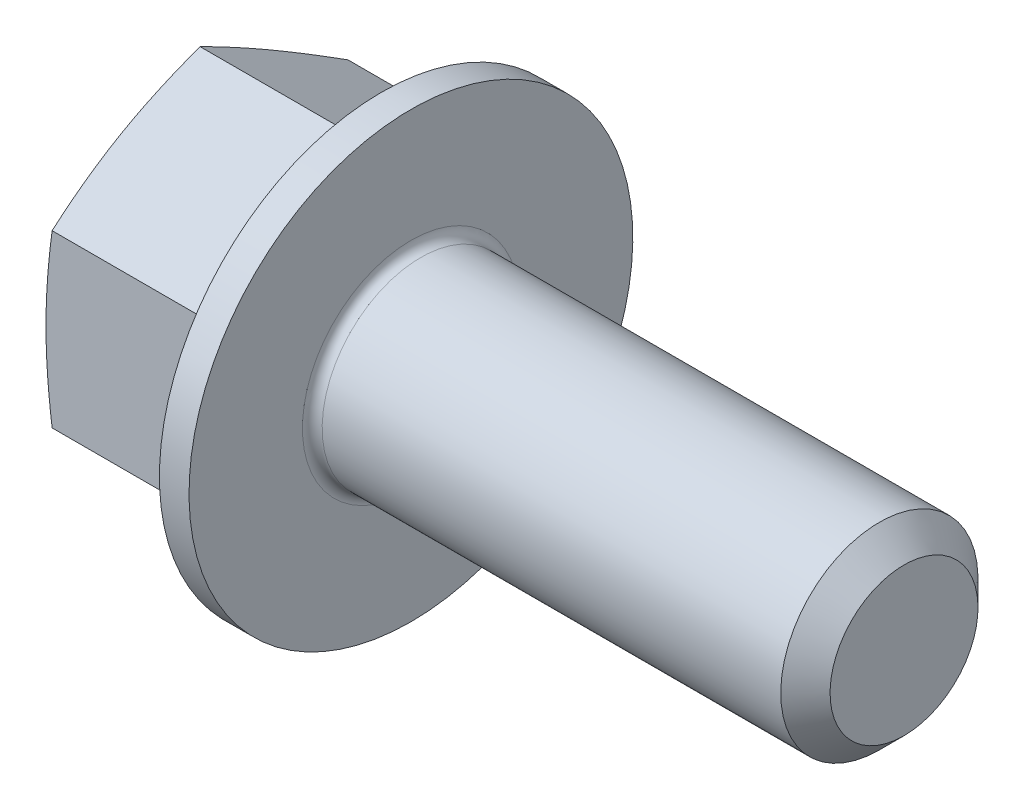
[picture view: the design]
ISO-10303-21;
HEADER;
FILE_DESCRIPTION(('STEP AP214'),'2;1');
FILE_NAME('part.step','',(''),(''),'','','');
FILE_SCHEMA(('AUTOMOTIVE_DESIGN { 1 0 10303 214 1 1 1 1 }'));
ENDSEC;
DATA;
#1=APPLICATION_CONTEXT('core data for automotive mechanical design processes');
#2=APPLICATION_PROTOCOL_DEFINITION('international standard','automotive_design',2000,#1);
#3=PRODUCT_CONTEXT('',#1,'mechanical');
#4=PRODUCT('Part','Part','',(#3));
#5=PRODUCT_RELATED_PRODUCT_CATEGORY('part','',(#4));
#6=PRODUCT_DEFINITION_FORMATION('','',#4);
#7=PRODUCT_DEFINITION_CONTEXT('part definition',#1,'design');
#8=PRODUCT_DEFINITION('design','',#6,#7);
#9=PRODUCT_DEFINITION_SHAPE('','',#8);
#10=(LENGTH_UNIT() NAMED_UNIT(*) SI_UNIT(.MILLI.,.METRE.));
#11=(NAMED_UNIT(*) PLANE_ANGLE_UNIT() SI_UNIT($,.RADIAN.));
#12=(NAMED_UNIT(*) SI_UNIT($,.STERADIAN.) SOLID_ANGLE_UNIT());
#13=UNCERTAINTY_MEASURE_WITH_UNIT(LENGTH_MEASURE(1.E-05),#10,'distance_accuracy_value','');
#14=(GEOMETRIC_REPRESENTATION_CONTEXT(3) GLOBAL_UNCERTAINTY_ASSIGNED_CONTEXT((#13)) GLOBAL_UNIT_ASSIGNED_CONTEXT((#10,
#11,#12)) REPRESENTATION_CONTEXT('',''));
#15=CARTESIAN_POINT('',(0.,0.,0.));
#16=DIRECTION('',(0.,0.,1.));
#17=DIRECTION('',(1.,0.,0.));
#18=AXIS2_PLACEMENT_3D('',#15,#16,#17);
#19=CARTESIAN_POINT('',(-0.3,0.,0.));
#20=DIRECTION('',(1.,0.,0.));
#21=DIRECTION('',(0.,1.,0.));
#22=AXIS2_PLACEMENT_3D('',#19,#20,#21);
#23=CONICAL_SURFACE('',#22,2.25,1.30899693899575);
#24=CARTESIAN_POINT('',(1.16852533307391,-2.67982443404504,7.64159207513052));
#25=CARTESIAN_POINT('',(1.26042918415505,-2.6677532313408,7.62068413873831));
#26=CARTESIAN_POINT('',(1.26511791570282,-2.58495311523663,7.66706657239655));
#27=CARTESIAN_POINT('',(1.08120608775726,-2.51357832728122,7.35364537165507));
#28=CARTESIAN_POINT('',(1.17299052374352,-2.50166546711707,7.3330116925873));
#29=CARTESIAN_POINT('',(1.17779867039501,-2.41890785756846,7.37905319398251));
#30=CARTESIAN_POINT('',(0.994043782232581,-2.34731143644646,7.06566266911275));
#31=CARTESIAN_POINT('',(1.08567092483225,-2.33552666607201,7.04525084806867));
#32=CARTESIAN_POINT('',(1.09063636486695,-2.25286120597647,7.09099799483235));
#33=CARTESIAN_POINT('',(0.820261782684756,-2.0145973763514,6.48938501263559));
#34=CARTESIAN_POINT('',(0.91144791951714,-2.00295342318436,6.46921709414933));
#35=CARTESIAN_POINT('',(0.916854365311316,-1.9206620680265,6.51456185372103));
#36=CARTESIAN_POINT('',(0.733642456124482,-1.84815015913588,6.20108997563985));
#37=CARTESIAN_POINT('',(0.824601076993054,-1.83662898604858,6.18113471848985));
#38=CARTESIAN_POINT('',(0.830235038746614,-1.75450957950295,6.22618082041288));
#39=CARTESIAN_POINT('',(0.559145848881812,-1.51101153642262,5.6171487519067));
#40=CARTESIAN_POINT('',(0.649509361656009,-1.49966816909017,5.59750146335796));
#41=CARTESIAN_POINT('',(0.655738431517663,-1.41807903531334,5.64205001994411));
#42=CARTESIAN_POINT('',(0.471290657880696,-1.34031726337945,5.32149759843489));
#43=CARTESIAN_POINT('',(0.561360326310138,-1.32918114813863,5.30220928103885));
#44=CARTESIAN_POINT('',(0.567883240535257,-1.24780087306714,5.34629490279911));
#45=CARTESIAN_POINT('',(0.297201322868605,-0.998834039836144,4.73003130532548));
#46=CARTESIAN_POINT('',(0.38644593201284,-0.987956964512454,4.71119165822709));
#47=CARTESIAN_POINT('',(0.393793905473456,-0.907344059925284,4.75460965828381));
#48=CARTESIAN_POINT('',(0.210966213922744,-0.828045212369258,4.43421637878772));
#49=CARTESIAN_POINT('',(0.299811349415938,-0.817490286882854,4.41593471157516));
#50=CARTESIAN_POINT('',(0.307558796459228,-0.737165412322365,4.45867975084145));
#51=CARTESIAN_POINT('',(0.0457052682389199,-0.494940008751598,3.85726124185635));
#52=CARTESIAN_POINT('',(0.133379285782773,-0.484748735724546,3.83960943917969));
#53=CARTESIAN_POINT('',(0.142297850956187,-0.405587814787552,3.88151329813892));
#54=CARTESIAN_POINT('',(-0.0334628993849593,-0.332641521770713,3.5761520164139));
#55=CARTESIAN_POINT('',(0.0536678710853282,-0.322953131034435,3.55937123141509));
#56=CARTESIAN_POINT('',(0.0631296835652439,-0.244189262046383,3.60030708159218));
#57=CARTESIAN_POINT('',(-0.148311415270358,-0.0885639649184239,3.15339728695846));
#58=CARTESIAN_POINT('',(-0.0626738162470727,-0.0788132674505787,3.13650858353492));
#59=CARTESIAN_POINT('',(-0.0517188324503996,-0.00191934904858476,3.17750894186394));
#60=CARTESIAN_POINT('',(-0.185978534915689,-0.00701979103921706,3.01215863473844));
#61=CARTESIAN_POINT('',(-0.100766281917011,0.0024789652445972,2.99570630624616));
#62=CARTESIAN_POINT('',(-0.0893859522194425,0.0789450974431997,3.03627288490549));
#63=CARTESIAN_POINT('',(-0.25925503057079,0.156298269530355,2.72928345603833));
#64=CARTESIAN_POINT('',(-0.175024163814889,0.165307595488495,2.71367884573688));
#65=CARTESIAN_POINT('',(-0.162662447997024,0.240685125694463,2.75348409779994));
#66=CARTESIAN_POINT('',(-0.294864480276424,0.238072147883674,2.58764694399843));
#67=CARTESIAN_POINT('',(-0.211154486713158,0.246741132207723,2.57263182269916));
#68=CARTESIAN_POINT('',(-0.19827189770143,0.321560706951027,2.61193137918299));
#69=CARTESIAN_POINT('',(-0.362403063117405,0.400818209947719,2.30576249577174));
#70=CARTESIAN_POINT('',(-0.279864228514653,0.408806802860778,2.29192584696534));
#71=CARTESIAN_POINT('',(-0.265810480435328,0.482225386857,2.33038553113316));
#72=CARTESIAN_POINT('',(-0.394376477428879,0.481785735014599,2.1655226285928));
#73=CARTESIAN_POINT('',(-0.312456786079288,0.489314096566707,2.1524831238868));
#74=CARTESIAN_POINT('',(-0.297783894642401,0.562013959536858,2.19039807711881));
#75=CARTESIAN_POINT('',(-0.453314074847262,0.644206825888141,1.88420104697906));
#76=CARTESIAN_POINT('',(-0.372713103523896,0.650745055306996,1.87287650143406));
#77=CARTESIAN_POINT('',(-0.356721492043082,0.721717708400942,1.90992625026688));
#78=CARTESIAN_POINT('',(-0.480277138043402,0.725660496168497,1.74311915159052));
#79=CARTESIAN_POINT('',(-0.400383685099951,0.731580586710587,1.73286525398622));
#80=CARTESIAN_POINT('',(-0.383684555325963,0.801632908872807,1.76944177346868));
#81=CARTESIAN_POINT('',(-0.526067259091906,0.888881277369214,1.4604124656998));
#82=CARTESIAN_POINT('',(-0.447482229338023,0.893400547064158,1.45258486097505));
#83=CARTESIAN_POINT('',(-0.429474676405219,0.961477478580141,1.48856472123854));
#84=CARTESIAN_POINT('',(-0.544921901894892,0.970646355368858,1.31879119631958));
#85=CARTESIAN_POINT('',(-0.467016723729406,0.974422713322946,1.31225035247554));
#86=CARTESIAN_POINT('',(-0.448329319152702,1.04140585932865,1.348173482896));
#87=CARTESIAN_POINT('',(-0.570718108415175,1.13462632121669,1.03476956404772));
#88=CARTESIAN_POINT('',(-0.493671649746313,1.13649888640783,1.03152618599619));
#89=CARTESIAN_POINT('',(-0.474125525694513,1.20184772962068,1.06745641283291));
#90=CARTESIAN_POINT('',(-0.577669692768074,1.21684077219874,0.892369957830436));
#91=CARTESIAN_POINT('',(-0.500930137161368,1.2179038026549,0.890528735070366));
#92=CARTESIAN_POINT('',(-0.48107711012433,1.28236066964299,0.92713062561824));
#93=CARTESIAN_POINT('',(-0.577704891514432,1.33303362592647,0.69111803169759));
#94=CARTESIAN_POINT('',(-0.500975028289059,1.33259321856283,0.691880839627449));
#95=CARTESIAN_POINT('',(-0.481112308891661,1.3966709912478,0.729127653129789));
#96=CARTESIAN_POINT('',(-0.57653036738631,1.36702621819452,0.63224113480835));
#97=CARTESIAN_POINT('',(-0.499753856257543,1.36616942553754,0.633725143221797));
#98=CARTESIAN_POINT('',(-0.479937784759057,1.43017604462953,0.671239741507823));
#99=CARTESIAN_POINT('',(-0.571921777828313,1.43498768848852,0.51452841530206));
#100=CARTESIAN_POINT('',(-0.494976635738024,1.4332771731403,0.517491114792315));
#101=CARTESIAN_POINT('',(-0.47532919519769,1.49730148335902,0.555523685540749));
#102=CARTESIAN_POINT('',(-0.568486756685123,1.46895655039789,0.455692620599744));
#103=CARTESIAN_POINT('',(-0.491414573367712,1.46684337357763,0.459352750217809));
#104=CARTESIAN_POINT('',(-0.471894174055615,1.53092191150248,0.497695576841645));
#105=CARTESIAN_POINT('',(-0.554993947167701,1.57088921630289,0.279140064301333));
#106=CARTESIAN_POINT('',(-0.477436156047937,1.56765525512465,0.284741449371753));
#107=CARTESIAN_POINT('',(-0.458401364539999,1.6320177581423,0.324121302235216));
#108=CARTESIAN_POINT('',(-0.541749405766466,1.63874915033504,0.161603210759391));
#109=CARTESIAN_POINT('',(-0.463703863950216,1.63485041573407,0.168356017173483));
#110=CARTESIAN_POINT('',(-0.445156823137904,1.69959991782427,0.208506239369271));
#111=CARTESIAN_POINT('',(-0.508739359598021,1.77462324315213,-0.0737376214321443));
#112=CARTESIAN_POINT('',(-0.429692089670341,1.76940488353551,-0.0646991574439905));
#113=CARTESIAN_POINT('',(-0.412146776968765,1.83528458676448,-0.0233483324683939));
#114=CARTESIAN_POINT('',(-0.48892003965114,1.84263391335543,-0.191535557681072));
#115=CARTESIAN_POINT('',(-0.40929760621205,1.83683303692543,-0.181488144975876));
#116=CARTESIAN_POINT('',(-0.392327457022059,1.90338670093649,-0.139584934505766));
#117=CARTESIAN_POINT('',(-0.444775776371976,1.97811547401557,-0.426196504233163));
#118=CARTESIAN_POINT('',(-0.364005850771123,1.97135383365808,-0.414484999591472));
#119=CARTESIAN_POINT('',(-0.348183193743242,2.039233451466,-0.371492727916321));
#120=CARTESIAN_POINT('',(-0.420462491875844,2.04558730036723,-0.543061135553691));
#121=CARTESIAN_POINT('',(-0.339090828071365,2.03843783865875,-0.530677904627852));
#122=CARTESIAN_POINT('',(-0.323869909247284,2.10697855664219,-0.48716460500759));
#123=CARTESIAN_POINT('',(-0.394836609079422,2.11290400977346,-0.659657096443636));
#124=CARTESIAN_POINT('',(-0.313077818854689,2.10509238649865,-0.646126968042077));
#125=CARTESIAN_POINT('',(-0.298244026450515,2.17456502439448,-0.602743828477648));
#126=(BOUNDED_SURFACE() B_SPLINE_SURFACE(3,2,((#24,#25,#26),(#27,#28,#29),(#30,#31,#32),(#33,
#34,#35),(#36,#37,#38),(#39,#40,#41),(#42,#43,#44),(#45,#46,#47),(#48,#49,#50),(#51,#52,#53),
(#54,#55,#56),(#57,#58,#59),(#60,#61,#62),(#63,#64,#65),(#66,#67,#68),(#69,#70,#71),(#72,#73,
#74),(#75,#76,#77),(#78,#79,#80),(#81,#82,#83),(#84,#85,#86),(#87,#88,#89),(#90,#91,#92),(#93,
#94,#95),(#96,#97,#98),(#99,#100,#101),(#102,#103,#104),(#105,#106,#107),(#108,#109,#110),(#111,
#112,#113),(#114,#115,#116),(#117,#118,#119),(#120,#121,#122),(#123,#124,#125)),.UNSPECIFIED.,
.F.,.F.,.F.) B_SPLINE_SURFACE_WITH_KNOTS((4,2,2,2,2,2,2,2,2,2,2,2,2,2,2,2,4),(3,3),(0.,
1.03130129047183,2.06323808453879,3.12077118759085,4.17765305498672,5.17996149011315,
5.6820983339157,6.18421718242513,6.67935566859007,7.17460469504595,7.66815528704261,
8.1612901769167,8.36524298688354,8.56928208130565,8.97813846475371,9.39042752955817,
9.80166162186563),(0.,1.),
.UNSPECIFIED.) GEOMETRIC_REPRESENTATION_ITEM() RATIONAL_B_SPLINE_SURFACE(((1.,0.724919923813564,
1.),(1.,0.725634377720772,1.),(1.,0.726416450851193,1.),(1.,0.728221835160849,1.),(1.,
0.729245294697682,1.),(1.,0.731668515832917,1.),(1.,0.733076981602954,1.),(1.,0.736473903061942,
1.),(1.,0.738462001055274,1.),(1.,0.74328290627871,1.),(1.,0.746066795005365,1.),(1.,
0.751359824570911,1.),(1.,0.75331282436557,1.),(1.,0.757692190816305,1.),(1.,0.760118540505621,
1.),(1.,0.765471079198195,1.),(1.,0.768389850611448,1.),(1.,0.774638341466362,1.),(1.,
0.777968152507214,1.),(1.,0.784396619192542,1.),(1.,0.78749602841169,1.),(1.,0.791967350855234,
1.),(1.,0.793340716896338,1.),(1.,0.793358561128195,1.),(1.,0.79313102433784,1.),(1.,
0.792266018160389,1.),(1.,0.791628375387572,1.),(1.,0.789211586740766,1.),(1.,0.786929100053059,
1.),(1.,0.781896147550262,1.),(1.,0.779141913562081,1.),(1.,0.773692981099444,1.),(1.,
0.770998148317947,1.),(1.,0.768581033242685,1.))) REPRESENTATION_ITEM('') SURFACE());
#127=CARTESIAN_POINT('',(-0.298244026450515,2.17456502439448,-0.602743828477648));
#128=CARTESIAN_POINT('',(-0.323869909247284,2.10697855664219,-0.48716460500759));
#129=CARTESIAN_POINT('',(-0.348183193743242,2.039233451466,-0.371492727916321));
#130=CARTESIAN_POINT('',(-0.392327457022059,1.90338670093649,-0.139584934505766));
#131=CARTESIAN_POINT('',(-0.412146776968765,1.83528458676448,-0.0233483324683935));
#132=CARTESIAN_POINT('',(-0.445156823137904,1.69959991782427,0.208506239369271));
#133=CARTESIAN_POINT('',(-0.458401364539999,1.6320177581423,0.324121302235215));
#134=CARTESIAN_POINT('',(-0.471894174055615,1.53092191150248,0.497695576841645));
#135=CARTESIAN_POINT('',(-0.47532919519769,1.49730148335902,0.555523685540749));
#136=CARTESIAN_POINT('',(-0.479937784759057,1.43017604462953,0.671239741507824));
#137=CARTESIAN_POINT('',(-0.481112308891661,1.3966709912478,0.729127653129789));
#138=CARTESIAN_POINT('',(-0.48107711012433,1.28236066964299,0.92713062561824));
#139=CARTESIAN_POINT('',(-0.474125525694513,1.20184772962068,1.06745641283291));
#140=CARTESIAN_POINT('',(-0.448329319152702,1.04140585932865,1.348173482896));
#141=CARTESIAN_POINT('',(-0.429474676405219,0.961477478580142,1.48856472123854));
#142=CARTESIAN_POINT('',(-0.383684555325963,0.801632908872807,1.76944177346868));
#143=CARTESIAN_POINT('',(-0.356721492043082,0.721717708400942,1.90992625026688));
#144=CARTESIAN_POINT('',(-0.297783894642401,0.562013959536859,2.19039807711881));
#145=CARTESIAN_POINT('',(-0.265810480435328,0.482225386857,2.33038553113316));
#146=CARTESIAN_POINT('',(-0.19827189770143,0.321560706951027,2.61193137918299));
#147=CARTESIAN_POINT('',(-0.162662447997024,0.240685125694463,2.75348409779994));
#148=CARTESIAN_POINT('',(-0.0893859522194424,0.0789450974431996,3.03627288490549));
#149=CARTESIAN_POINT('',(-0.0517188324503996,-0.0019193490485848,3.17750894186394));
#150=CARTESIAN_POINT('',(0.0631296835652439,-0.244189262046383,3.60030708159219));
#151=CARTESIAN_POINT('',(0.142297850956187,-0.405587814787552,3.88151329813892));
#152=CARTESIAN_POINT('',(0.307558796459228,-0.737165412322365,4.45867975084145));
#153=CARTESIAN_POINT('',(0.393793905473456,-0.907344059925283,4.75460965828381));
#154=CARTESIAN_POINT('',(0.567883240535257,-1.24780087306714,5.34629490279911));
#155=CARTESIAN_POINT('',(0.655738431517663,-1.41807903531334,5.64205001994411));
#156=CARTESIAN_POINT('',(0.830235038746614,-1.75450957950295,6.22618082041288));
#157=CARTESIAN_POINT('',(0.916854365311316,-1.9206620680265,6.51456185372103));
#158=CARTESIAN_POINT('',(1.09063636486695,-2.25286120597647,7.09099799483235));
#159=CARTESIAN_POINT('',(1.17779867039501,-2.41890785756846,7.37905319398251));
#160=CARTESIAN_POINT('',(1.26511791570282,-2.58495311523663,7.66706657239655));
#161=B_SPLINE_CURVE_WITH_KNOTS('',3,(#127,#128,#129,#130,#131,#132,#133,#134,#135,#136,#137,
#138,#139,#140,#141,#142,#143,#144,#145,#146,#147,#148,#149,#150,#151,#152,#153,#154,#155,#156,
#157,#158,#159,#160),.UNSPECIFIED.,.F.,.F.,(4,2,2,2,2,2,2,2,2,2,2,2,2,2,2,2,4),(0.,
0.411234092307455,0.823523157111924,1.23237954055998,1.43641863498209,1.64037144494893,
2.13350633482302,2.62705692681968,3.12230595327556,3.6174444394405,4.11956328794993,
4.62170013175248,5.62400856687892,6.68089043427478,7.73842353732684,8.7703603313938,
9.80166162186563),.UNSPECIFIED.);
#162=CARTESIAN_POINT('',(-0.414778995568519,1.82163895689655,0.));
#163=VERTEX_POINT('',#162);
#164=CARTESIAN_POINT('',(-0.414778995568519,0.910819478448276,1.5775856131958));
#165=VERTEX_POINT('',#164);
#166=EDGE_CURVE('E454',#163,#165,#161,.T.);
#167=ORIENTED_EDGE('',*,*,#166,.T.);
#168=CARTESIAN_POINT('',(1.16815629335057,-7.95632023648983,1.5));
#169=CARTESIAN_POINT('',(1.26005938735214,-7.93217819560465,1.5));
#170=CARTESIAN_POINT('',(1.26474887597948,-7.93094631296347,1.59489735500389));
#171=CARTESIAN_POINT('',(1.08083726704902,-7.62382649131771,1.5));
#172=CARTESIAN_POINT('',(1.17262089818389,-7.60000121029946,1.5));
#173=CARTESIAN_POINT('',(1.1774298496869,-7.59849527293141,1.59469000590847));
#174=CARTESIAN_POINT('',(0.993675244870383,-7.29129116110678,1.5));
#175=CARTESIAN_POINT('',(1.08530154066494,-7.26772219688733,1.5));
#176=CARTESIAN_POINT('',(1.09026782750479,-7.26600730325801,1.594462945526));
#177=CARTESIAN_POINT('',(0.819894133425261,-6.62585972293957,1.5));
#178=CARTESIAN_POINT('',(0.911079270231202,-6.6025725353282,1.5));
#179=CARTESIAN_POINT('',(0.91648671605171,-6.6006961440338,1.59393756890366));
#180=CARTESIAN_POINT('',(0.733275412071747,-6.29296351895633,1.5));
#181=CARTESIAN_POINT('',(0.82423295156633,-6.26992201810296,1.5));
#182=CARTESIAN_POINT('',(0.829867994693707,-6.26787287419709,1.59363920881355));
#183=CARTESIAN_POINT('',(0.558777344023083,-5.61866988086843,1.5));
#184=CARTESIAN_POINT('',(0.649139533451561,-5.59598422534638,1.5));
#185=CARTESIAN_POINT('',(0.65536992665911,-5.59376922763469,1.59293088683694));
#186=CARTESIAN_POINT('',(0.470920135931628,-5.27726669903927,1.5));
#187=CARTESIAN_POINT('',(0.560988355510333,-5.25499582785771,1.5));
#188=CARTESIAN_POINT('',(0.567512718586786,-5.2524841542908,1.59251833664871));
#189=CARTESIAN_POINT('',(0.296828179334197,-4.59427079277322,1.5));
#190=CARTESIAN_POINT('',(0.38607092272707,-4.57251836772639,1.5));
#191=CARTESIAN_POINT('',(0.393420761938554,-4.56981210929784,1.59151941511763));
#192=CARTESIAN_POINT('',(0.210592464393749,-4.25267831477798,1.5));
#193=CARTESIAN_POINT('',(0.299435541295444,-4.2315707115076,1.5));
#194=CARTESIAN_POINT('',(0.307185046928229,-4.22842533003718,1.59093315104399));
#195=CARTESIAN_POINT('',(0.0453368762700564,-3.58645304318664,1.5));
#196=CARTESIAN_POINT('',(0.133008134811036,-3.56607324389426,1.5));
#197=CARTESIAN_POINT('',(0.141929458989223,-3.56278144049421,1.5895036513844));
#198=CARTESIAN_POINT('',(-0.0338255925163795,-3.26185609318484,1.5));
#199=CARTESIAN_POINT('',(0.0533021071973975,-3.2424828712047,1.5));
#200=CARTESIAN_POINT('',(0.0627669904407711,-3.23855083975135,1.58867526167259));
#201=CARTESIAN_POINT('',(-0.148660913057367,-2.7736997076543,1.5));
#202=CARTESIAN_POINT('',(-0.0630272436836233,-2.7542021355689,1.5));
#203=CARTESIAN_POINT('',(-0.0520683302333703,-2.7512617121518,1.58708701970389));
#204=CARTESIAN_POINT('',(-0.18632288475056,-2.61061056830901,1.5));
#205=CARTESIAN_POINT('',(-0.101114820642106,-2.59161735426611,1.5));
#206=CARTESIAN_POINT('',(-0.089730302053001,-2.58851510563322,1.58649925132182));
#207=CARTESIAN_POINT('',(-0.25958637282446,-2.28397234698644,1.5));
#208=CARTESIAN_POINT('',(-0.175360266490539,-2.26595901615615,1.5));
#209=CARTESIAN_POINT('',(-0.162993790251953,-2.26274184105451,1.58517492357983));
#210=CARTESIAN_POINT('',(-0.2951879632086,-2.12042328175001,1.5));
#211=CARTESIAN_POINT('',(-0.211483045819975,-2.10309130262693,1.5));
#212=CARTESIAN_POINT('',(-0.198595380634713,-2.09971519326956,1.58443836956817));
#213=CARTESIAN_POINT('',(-0.362705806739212,-1.79493051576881,1.5));
#214=CARTESIAN_POINT('',(-0.280172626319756,-1.77896083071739,1.5));
#215=CARTESIAN_POINT('',(-0.266113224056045,-1.7755582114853,1.58280412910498));
#216=CARTESIAN_POINT('',(-0.39466645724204,-1.63299615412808,1.5));
#217=CARTESIAN_POINT('',(-0.312752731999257,-1.61794780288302,1.5));
#218=CARTESIAN_POINT('',(-0.298073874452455,-1.61443306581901,1.58190882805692));
#219=CARTESIAN_POINT('',(-0.453571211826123,-1.30815460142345,1.5));
#220=CARTESIAN_POINT('',(-0.372976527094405,-1.29508872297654,1.5));
#221=CARTESIAN_POINT('',(-0.356978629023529,-1.29168904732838,1.57997967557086));
#222=CARTESIAN_POINT('',(-0.480514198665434,-1.14524720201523,1.5));
#223=CARTESIAN_POINT('',(-0.400627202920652,-1.13341855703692,1.5));
#224=CARTESIAN_POINT('',(-0.383921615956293,-1.13007007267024,1.57894579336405));
#225=CARTESIAN_POINT('',(-0.526253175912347,-0.81880561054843,1.5));
#226=CARTESIAN_POINT('',(-0.447673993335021,-0.80978145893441,1.5));
#227=CARTESIAN_POINT('',(-0.429660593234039,-0.806905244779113,1.57693729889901));
#228=CARTESIAN_POINT('',(-0.545076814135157,-0.655275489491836,1.5));
#229=CARTESIAN_POINT('',(-0.467176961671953,-0.647737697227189,1.5));
#230=CARTESIAN_POINT('',(-0.448484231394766,-0.645361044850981,1.57596249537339));
#231=CARTESIAN_POINT('',(-0.570800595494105,-0.327317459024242,1.5));
#232=CARTESIAN_POINT('',(-0.493757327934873,-0.323590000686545,1.5));
#233=CARTESIAN_POINT('',(-0.474208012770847,-0.322037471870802,1.57455395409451));
#234=CARTESIAN_POINT('',(-0.577710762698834,-0.162890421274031,1.5));
#235=CARTESIAN_POINT('',(-0.500972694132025,-0.160782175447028,1.5));
#236=CARTESIAN_POINT('',(-0.481118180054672,-0.160258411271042,1.57411976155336));
#237=CARTESIAN_POINT('',(-0.577687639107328,0.0694902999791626,1.5));
#238=CARTESIAN_POINT('',(-0.500957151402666,0.0685905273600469,1.5));
#239=CARTESIAN_POINT('',(-0.481095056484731,0.0683674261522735,1.57411742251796));
#240=CARTESIAN_POINT('',(-0.576496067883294,0.13747391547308,1.5));
#241=CARTESIAN_POINT('',(-0.499718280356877,0.135741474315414,1.5));
#242=CARTESIAN_POINT('',(-0.479903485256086,0.135251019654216,1.57419072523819));
#243=CARTESIAN_POINT('',(-0.57185435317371,0.273393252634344,1.5));
#244=CARTESIAN_POINT('',(-0.494906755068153,0.269953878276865,1.5));
#245=CARTESIAN_POINT('',(-0.475261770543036,0.269023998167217,1.57446693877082));
#246=CARTESIAN_POINT('',(-0.568403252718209,0.341328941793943,1.5));
#247=CARTESIAN_POINT('',(-0.491328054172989,0.337084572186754,1.5));
#248=CARTESIAN_POINT('',(-0.471810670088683,0.335913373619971,1.57466990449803));
#249=CARTESIAN_POINT('',(-0.554864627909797,0.545188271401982,1.5));
#250=CARTESIAN_POINT('',(-0.477302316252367,0.538704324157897,1.5));
#251=CARTESIAN_POINT('',(-0.45827204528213,0.536777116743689,1.57543658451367));
#252=CARTESIAN_POINT('',(-0.541592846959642,0.680903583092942,1.5));
#253=CARTESIAN_POINT('',(-0.463542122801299,0.673090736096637,1.5));
#254=CARTESIAN_POINT('',(-0.445000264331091,0.67069107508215,1.57615790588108));
#255=CARTESIAN_POINT('',(-0.508536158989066,0.952643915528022,1.5));
#256=CARTESIAN_POINT('',(-0.429482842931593,0.942194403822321,1.5));
#257=CARTESIAN_POINT('',(-0.4119435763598,0.93932106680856,1.57773806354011));
#258=CARTESIAN_POINT('',(-0.488697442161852,1.08866195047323,1.5));
#259=CARTESIAN_POINT('',(-0.409068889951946,1.0770483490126,1.5));
#260=CARTESIAN_POINT('',(-0.392104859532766,1.07403438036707,1.5785980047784));
#261=CARTESIAN_POINT('',(-0.444520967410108,1.35961767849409,1.5));
#262=CARTESIAN_POINT('',(-0.363744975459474,1.34608444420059,1.5));
#263=CARTESIAN_POINT('',(-0.347928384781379,1.34279142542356,1.58029056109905));
#264=CARTESIAN_POINT('',(-0.42019489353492,1.49455724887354,1.5));
#265=CARTESIAN_POINT('',(-0.338817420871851,1.48024883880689,1.5));
#266=CARTESIAN_POINT('',(-0.32360231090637,1.47683598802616,1.58112324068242));
#267=CARTESIAN_POINT('',(-0.394558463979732,1.62918706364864,1.5));
#268=CARTESIAN_POINT('',(-0.312793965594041,1.61355586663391,1.5));
#269=CARTESIAN_POINT('',(-0.297965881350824,1.61072113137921,1.58186488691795));
#270=(BOUNDED_SURFACE() B_SPLINE_SURFACE(3,2,((#168,#169,#170),(#171,#172,#173),(#174,#175,
#176),(#177,#178,#179),(#180,#181,#182),(#183,#184,#185),(#186,#187,#188),(#189,#190,#191),
(#192,#193,#194),(#195,#196,#197),(#198,#199,#200),(#201,#202,#203),(#204,#205,#206),(#207,#208,
#209),(#210,#211,#212),(#213,#214,#215),(#216,#217,#218),(#219,#220,#221),(#222,#223,#224),
(#225,#226,#227),(#228,#229,#230),(#231,#232,#233),(#234,#235,#236),(#237,#238,#239),(#240,#241,
#242),(#243,#244,#245),(#246,#247,#248),(#249,#250,#251),(#252,#253,#254),(#255,#256,#257),
(#258,#259,#260),(#261,#262,#263),(#264,#265,#266),(#267,#268,#269)),.UNSPECIFIED.,.F.,.F.,
.F.) B_SPLINE_SURFACE_WITH_KNOTS((4,2,2,2,2,2,2,2,2,2,2,2,2,2,2,2,4),(3,3),(0.,1.03130556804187,
2.06324704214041,3.12082417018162,4.17774959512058,5.1800538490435,5.68218951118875,
6.18430712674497,6.67943603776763,7.17467506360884,7.66821413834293,8.16133774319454,
8.36528677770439,8.56932224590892,8.97817344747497,9.39046133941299,9.80169050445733),(0.,1.),
.UNSPECIFIED.) GEOMETRIC_REPRESENTATION_ITEM() RATIONAL_B_SPLINE_SURFACE(((1.,0.724922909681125,
1.),(1.,0.725637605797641,1.),(1.,0.726419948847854,1.),(1.,0.728226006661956,1.),(1.,
0.72924986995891,1.),(1.,0.731674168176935,1.),(1.,0.733083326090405,1.),(1.,0.736482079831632,
1.),(1.,0.738471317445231,1.),(1.,0.743295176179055,1.),(1.,0.746080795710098,1.),(1.,
0.751377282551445,1.),(1.,0.753331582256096,1.),(1.,0.757713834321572,1.),(1.,0.760141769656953,
1.),(1.,0.765497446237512,1.),(1.,0.768417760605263,1.),(1.,0.774668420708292,1.),(1.,
0.777998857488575,1.),(1.,0.784425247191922,1.),(1.,0.787521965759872,1.),(1.,0.791982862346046,
1.),(1.,0.793348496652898,1.),(1.,0.793355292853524,1.),(1.,0.793124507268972,1.),(1.,
0.792253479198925,1.),(1.,0.791613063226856,1.),(1.,0.789189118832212,1.),(1.,0.786903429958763,
1.),(1.,0.781866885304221,1.),(1.,0.779112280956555,1.),(1.,0.773664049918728,1.),(1.,
0.770970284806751,1.),(1.,0.768554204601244,1.))) REPRESENTATION_ITEM('') SURFACE());
#271=CARTESIAN_POINT('',(-0.297965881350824,1.61072113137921,1.58186488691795));
#272=CARTESIAN_POINT('',(-0.32360231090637,1.47683598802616,1.58112324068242));
#273=CARTESIAN_POINT('',(-0.347928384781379,1.34279142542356,1.58029056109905));
#274=CARTESIAN_POINT('',(-0.392104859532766,1.07403438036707,1.5785980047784));
#275=CARTESIAN_POINT('',(-0.4119435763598,0.939321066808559,1.57773806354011));
#276=CARTESIAN_POINT('',(-0.445000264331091,0.67069107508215,1.57615790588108));
#277=CARTESIAN_POINT('',(-0.45827204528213,0.53677711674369,1.57543658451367));
#278=CARTESIAN_POINT('',(-0.471810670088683,0.335913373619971,1.57466990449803));
#279=CARTESIAN_POINT('',(-0.475261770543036,0.269023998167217,1.57446693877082));
#280=CARTESIAN_POINT('',(-0.479903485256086,0.135251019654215,1.57419072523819));
#281=CARTESIAN_POINT('',(-0.481095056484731,0.0683674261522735,1.57411742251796));
#282=CARTESIAN_POINT('',(-0.481118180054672,-0.160258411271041,1.57411976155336));
#283=CARTESIAN_POINT('',(-0.474208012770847,-0.322037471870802,1.57455395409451));
#284=CARTESIAN_POINT('',(-0.448484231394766,-0.645361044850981,1.57596249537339));
#285=CARTESIAN_POINT('',(-0.429660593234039,-0.806905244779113,1.57693729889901));
#286=CARTESIAN_POINT('',(-0.383921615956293,-1.13007007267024,1.57894579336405));
#287=CARTESIAN_POINT('',(-0.356978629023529,-1.29168904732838,1.57997967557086));
#288=CARTESIAN_POINT('',(-0.298073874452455,-1.61443306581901,1.58190882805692));
#289=CARTESIAN_POINT('',(-0.266113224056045,-1.7755582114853,1.58280412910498));
#290=CARTESIAN_POINT('',(-0.198595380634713,-2.09971519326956,1.58443836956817));
#291=CARTESIAN_POINT('',(-0.162993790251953,-2.26274184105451,1.58517492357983));
#292=CARTESIAN_POINT('',(-0.0897303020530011,-2.58851510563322,1.58649925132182));
#293=CARTESIAN_POINT('',(-0.0520683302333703,-2.7512617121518,1.58708701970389));
#294=CARTESIAN_POINT('',(0.0627669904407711,-3.23855083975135,1.58867526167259));
#295=CARTESIAN_POINT('',(0.141929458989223,-3.56278144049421,1.5895036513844));
#296=CARTESIAN_POINT('',(0.307185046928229,-4.22842533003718,1.59093315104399));
#297=CARTESIAN_POINT('',(0.393420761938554,-4.56981210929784,1.59151941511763));
#298=CARTESIAN_POINT('',(0.567512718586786,-5.2524841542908,1.59251833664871));
#299=CARTESIAN_POINT('',(0.65536992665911,-5.59376922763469,1.59293088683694));
#300=CARTESIAN_POINT('',(0.829867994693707,-6.26787287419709,1.59363920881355));
#301=CARTESIAN_POINT('',(0.91648671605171,-6.6006961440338,1.59393756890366));
#302=CARTESIAN_POINT('',(1.09026782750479,-7.26600730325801,1.594462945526));
#303=CARTESIAN_POINT('',(1.1774298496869,-7.59849527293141,1.59469000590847));
#304=CARTESIAN_POINT('',(1.26474887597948,-7.93094631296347,1.59489735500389));
#305=B_SPLINE_CURVE_WITH_KNOTS('',3,(#271,#272,#273,#274,#275,#276,#277,#278,#279,#280,#281,
#282,#283,#284,#285,#286,#287,#288,#289,#290,#291,#292,#293,#294,#295,#296,#297,#298,#299,#300,
#301,#302,#303,#304),.UNSPECIFIED.,.F.,.F.,(4,2,2,2,2,2,2,2,2,2,2,2,2,2,2,2,4),(0.,
0.41122916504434,0.823517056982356,1.23236825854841,1.43640372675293,1.64035276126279,
2.1334763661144,2.62701544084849,3.1222544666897,3.61738337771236,4.11950099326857,
4.62163665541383,5.62394090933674,6.68086633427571,7.73844346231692,8.77038493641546,
9.80169050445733),.UNSPECIFIED.);
#306=CARTESIAN_POINT('',(-0.414778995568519,-0.910819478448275,1.5775856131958));
#307=VERTEX_POINT('',#306);
#308=EDGE_CURVE('E376',#165,#307,#305,.T.);
#309=ORIENTED_EDGE('',*,*,#308,.T.);
#310=CARTESIAN_POINT('',(1.16852533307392,-5.27790064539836,-6.14159207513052));
#311=CARTESIAN_POINT('',(1.26042918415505,-5.26582944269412,-6.12068413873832));
#312=CARTESIAN_POINT('',(1.26511791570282,-5.34739786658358,-6.07216835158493));
#313=CARTESIAN_POINT('',(1.08120608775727,-5.11165453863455,-5.85364537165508));
#314=CARTESIAN_POINT('',(1.17299052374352,-5.09974167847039,-5.8330116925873));
#315=CARTESIAN_POINT('',(1.17779867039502,-5.18099359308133,-5.78436225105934));
#316=CARTESIAN_POINT('',(0.994043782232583,-4.94538764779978,-5.56566266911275));
#317=CARTESIAN_POINT('',(1.08567092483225,-4.93360287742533,-5.54525084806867));
#318=CARTESIAN_POINT('',(1.09063636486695,-5.0145537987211,-5.49653403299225));
#319=CARTESIAN_POINT('',(0.820261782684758,-4.61267358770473,-4.9893850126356));
#320=CARTESIAN_POINT('',(0.911447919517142,-4.60102963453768,-4.96921709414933));
#321=CARTESIAN_POINT('',(0.916854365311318,-4.68144502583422,-4.92062306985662));
#322=CARTESIAN_POINT('',(0.733642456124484,-4.4462263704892,-4.70108997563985));
#323=CARTESIAN_POINT('',(0.824601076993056,-4.4347051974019,-4.68113471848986));
#324=CARTESIAN_POINT('',(0.830235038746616,-4.51477596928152,-4.63254027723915));
#325=CARTESIAN_POINT('',(0.559145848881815,-4.10908774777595,-4.11714875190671));
#326=CARTESIAN_POINT('',(0.649509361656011,-4.09774438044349,-4.09750146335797));
#327=CARTESIAN_POINT('',(0.655738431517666,-4.17711912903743,-4.04911747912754));
#328=CARTESIAN_POINT('',(0.471290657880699,-3.93839347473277,-3.82149759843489));
#329=CARTESIAN_POINT('',(0.561360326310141,-3.92725735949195,-3.80220928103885));
#330=CARTESIAN_POINT('',(0.567883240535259,-4.00612676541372,-3.75377470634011));
#331=CARTESIAN_POINT('',(0.297201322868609,-3.59691025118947,-3.23003130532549));
#332=CARTESIAN_POINT('',(0.386445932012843,-3.58603317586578,-3.2111916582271));
#333=CARTESIAN_POINT('',(0.393793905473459,-3.66394071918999,-3.16308783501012));
#334=CARTESIAN_POINT('',(0.210966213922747,-3.42612142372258,-2.93421637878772));
#335=CARTESIAN_POINT('',(0.299811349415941,-3.41556649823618,-2.91593471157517));
#336=CARTESIAN_POINT('',(0.307558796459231,-3.49274722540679,-2.86774384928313));
#337=CARTESIAN_POINT('',(0.045705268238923,-3.09301622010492,-2.35726124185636));
#338=CARTESIAN_POINT('',(0.133379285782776,-3.08282494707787,-2.3396094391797));
#339=CARTESIAN_POINT('',(0.14229785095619,-3.15869521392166,-2.29200600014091));
#340=CARTESIAN_POINT('',(-0.0334628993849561,-2.93071773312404,-2.07615201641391));
#341=CARTESIAN_POINT('',(0.0536678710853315,-2.92102934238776,-2.0593712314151));
#342=CARTESIAN_POINT('',(0.0631296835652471,-2.99586276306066,-2.01162764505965));
#343=CARTESIAN_POINT('',(-0.148311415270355,-2.68664017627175,-1.65339728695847));
#344=CARTESIAN_POINT('',(-0.0626738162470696,-2.6768894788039,-1.63650858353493));
#345=CARTESIAN_POINT('',(-0.0517188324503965,-2.7508437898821,-1.59041667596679));
#346=CARTESIAN_POINT('',(-0.185978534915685,-2.60509600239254,-1.51215863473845));
#347=CARTESIAN_POINT('',(-0.100766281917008,-2.59559724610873,-1.49570630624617));
#348=CARTESIAN_POINT('',(-0.0893859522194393,-2.66896199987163,-1.44976798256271));
#349=CARTESIAN_POINT('',(-0.259255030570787,-2.44177794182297,-1.22928345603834));
#350=CARTESIAN_POINT('',(-0.175024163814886,-2.43276861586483,-1.21367884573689));
#351=CARTESIAN_POINT('',(-0.162662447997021,-2.50492974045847,-1.16830261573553));
#352=CARTESIAN_POINT('',(-0.294864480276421,-2.36000406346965,-1.08764694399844));
#353=CARTESIAN_POINT('',(-0.211154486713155,-2.3513350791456,-1.07263182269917));
#354=CARTESIAN_POINT('',(-0.198271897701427,-2.42277928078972,-1.02748594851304));
#355=CARTESIAN_POINT('',(-0.362403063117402,-2.1972580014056,-0.805762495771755));
#356=CARTESIAN_POINT('',(-0.27986422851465,-2.18926940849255,-0.791925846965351));
#357=CARTESIAN_POINT('',(-0.265810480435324,-2.25928576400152,-0.747573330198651));
#358=CARTESIAN_POINT('',(-0.394376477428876,-2.11629047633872,-0.665522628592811));
#359=CARTESIAN_POINT('',(-0.312456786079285,-2.10876211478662,-0.652483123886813));
#360=CARTESIAN_POINT('',(-0.297783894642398,-2.17794735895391,-0.608480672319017));
#361=CARTESIAN_POINT('',(-0.45331407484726,-1.95386938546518,-0.384201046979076));
#362=CARTESIAN_POINT('',(-0.372713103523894,-1.94733115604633,-0.372876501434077));
#363=CARTESIAN_POINT('',(-0.356721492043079,-2.01490350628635,-0.329937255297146));
#364=CARTESIAN_POINT('',(-0.4802771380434,-1.87241571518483,-0.243119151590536));
#365=CARTESIAN_POINT('',(-0.400383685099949,-1.86649562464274,-0.232865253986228));
#366=CARTESIAN_POINT('',(-0.383684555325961,-1.93319798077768,-0.190486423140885));
#367=CARTESIAN_POINT('',(-0.526067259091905,-1.70919493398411,0.0395875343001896));
#368=CARTESIAN_POINT('',(-0.447482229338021,-1.70467566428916,0.0474151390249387));
#369=CARTESIAN_POINT('',(-0.429474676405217,-1.76987360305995,0.0883815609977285));
#370=CARTESIAN_POINT('',(-0.54492190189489,-1.62742985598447,0.181208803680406));
#371=CARTESIAN_POINT('',(-0.467016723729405,-1.62365349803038,0.187749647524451));
#372=CARTESIAN_POINT('',(-0.448329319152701,-1.68825541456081,0.227797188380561));
#373=CARTESIAN_POINT('',(-0.570718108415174,-1.46344989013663,0.465230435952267));
#374=CARTESIAN_POINT('',(-0.493671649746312,-1.4615773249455,0.468473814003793));
#375=CARTESIAN_POINT('',(-0.474125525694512,-1.52536823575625,0.507102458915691));
#376=CARTESIAN_POINT('',(-0.577669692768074,-1.38123543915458,0.60763004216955));
#377=CARTESIAN_POINT('',(-0.500930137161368,-1.38017240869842,0.609471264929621));
#378=CARTESIAN_POINT('',(-0.481077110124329,-1.44409900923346,0.646991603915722));
#379=CARTESIAN_POINT('',(-0.577704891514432,-1.26504258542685,0.808881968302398));
#380=CARTESIAN_POINT('',(-0.500975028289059,-1.2654829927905,0.808119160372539));
#381=CARTESIAN_POINT('',(-0.481112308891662,-1.32977856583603,0.844988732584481));
#382=CARTESIAN_POINT('',(-0.57653036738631,-1.2310499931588,0.86775886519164));
#383=CARTESIAN_POINT('',(-0.499753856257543,-1.23190678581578,0.866274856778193));
#384=CARTESIAN_POINT('',(-0.479937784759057,-1.29639869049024,0.902948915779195));
#385=CARTESIAN_POINT('',(-0.571921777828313,-1.1630885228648,0.98547158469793));
#386=CARTESIAN_POINT('',(-0.494976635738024,-1.16479903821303,0.982508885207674));
#387=CARTESIAN_POINT('',(-0.47532919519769,-1.22974836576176,1.01893927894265));
#388=CARTESIAN_POINT('',(-0.568486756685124,-1.12911966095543,1.04430737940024));
#389=CARTESIAN_POINT('',(-0.491414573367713,-1.13123283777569,1.04064724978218));
#390=CARTESIAN_POINT('',(-0.471894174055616,-1.19647796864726,1.07696947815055));
#391=CARTESIAN_POINT('',(-0.554993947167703,-1.02718699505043,1.22085993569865));
#392=CARTESIAN_POINT('',(-0.477436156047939,-1.03042095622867,1.21525855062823));
#393=CARTESIAN_POINT('',(-0.45840136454,-1.09670616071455,1.25130818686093));
#394=CARTESIAN_POINT('',(-0.541749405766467,-0.959327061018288,1.3383967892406));
#395=CARTESIAN_POINT('',(-0.463703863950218,-0.963225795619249,1.3316439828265));
#396=CARTESIAN_POINT('',(-0.445156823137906,-1.03037165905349,1.36764358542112));
#397=CARTESIAN_POINT('',(-0.508739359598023,-0.823452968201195,1.57373762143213));
#398=CARTESIAN_POINT('',(-0.429692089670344,-0.828671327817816,1.56469915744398));
#399=CARTESIAN_POINT('',(-0.412146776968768,-0.897422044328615,1.60107724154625));
#400=CARTESIAN_POINT('',(-0.488920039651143,-0.755442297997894,1.69153555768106));
#401=CARTESIAN_POINT('',(-0.409297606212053,-0.761243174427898,1.68148814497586));
#402=CARTESIAN_POINT('',(-0.392327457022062,-0.830809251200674,1.71817370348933));
#403=CARTESIAN_POINT('',(-0.444775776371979,-0.619960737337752,1.92619650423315));
#404=CARTESIAN_POINT('',(-0.364005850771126,-0.626722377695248,1.91448499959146));
#405=CARTESIAN_POINT('',(-0.348183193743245,-0.697894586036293,1.95177433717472));
#406=CARTESIAN_POINT('',(-0.420462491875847,-0.552488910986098,2.04306113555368));
#407=CARTESIAN_POINT('',(-0.339090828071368,-0.559638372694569,2.03067790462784));
#408=CARTESIAN_POINT('',(-0.323869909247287,-0.631592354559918,2.06827925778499));
#409=CARTESIAN_POINT('',(-0.394836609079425,-0.485172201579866,2.15965709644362));
#410=CARTESIAN_POINT('',(-0.313077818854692,-0.492983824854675,2.14612696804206));
#411=CARTESIAN_POINT('',(-0.298244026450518,-0.565291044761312,2.18460046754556));
#412=(BOUNDED_SURFACE() B_SPLINE_SURFACE(3,2,((#310,#311,#312),(#313,#314,#315),(#316,#317,
#318),(#319,#320,#321),(#322,#323,#324),(#325,#326,#327),(#328,#329,#330),(#331,#332,#333),
(#334,#335,#336),(#337,#338,#339),(#340,#341,#342),(#343,#344,#345),(#346,#347,#348),(#349,#350,
#351),(#352,#353,#354),(#355,#356,#357),(#358,#359,#360),(#361,#362,#363),(#364,#365,#366),
(#367,#368,#369),(#370,#371,#372),(#373,#374,#375),(#376,#377,#378),(#379,#380,#381),(#382,#383,
#384),(#385,#386,#387),(#388,#389,#390),(#391,#392,#393),(#394,#395,#396),(#397,#398,#399),
(#400,#401,#402),(#403,#404,#405),(#406,#407,#408),(#409,#410,#411)),.UNSPECIFIED.,.F.,.F.,
.F.) B_SPLINE_SURFACE_WITH_KNOTS((4,2,2,2,2,2,2,2,2,2,2,2,2,2,2,2,4),(3,3),(0.,1.03130129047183,
2.06323808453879,3.12077118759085,4.17765305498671,5.17996149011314,5.68209833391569,
6.18421718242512,6.67935566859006,7.17460469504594,7.6681552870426,8.16129017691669,
8.36524298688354,8.56928208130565,8.97813846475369,9.39042752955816,9.80166162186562),(0.,1.),
.UNSPECIFIED.) GEOMETRIC_REPRESENTATION_ITEM() RATIONAL_B_SPLINE_SURFACE(((1.,0.724919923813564,
1.),(1.,0.725634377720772,1.),(1.,0.726416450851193,1.),(1.,0.728221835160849,1.),(1.,
0.729245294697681,1.),(1.,0.731668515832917,1.),(1.,0.733076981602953,1.),(1.,0.736473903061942,
1.),(1.,0.738462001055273,1.),(1.,0.743282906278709,1.),(1.,0.746066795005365,1.),(1.,
0.751359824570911,1.),(1.,0.75331282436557,1.),(1.,0.757692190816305,1.),(1.,0.760118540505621,
1.),(1.,0.765471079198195,1.),(1.,0.768389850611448,1.),(1.,0.774638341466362,1.),(1.,
0.777968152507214,1.),(1.,0.784396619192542,1.),(1.,0.78749602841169,1.),(1.,0.791967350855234,
1.),(1.,0.793340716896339,1.),(1.,0.793358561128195,1.),(1.,0.79313102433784,1.),(1.,
0.792266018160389,1.),(1.,0.791628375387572,1.),(1.,0.789211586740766,1.),(1.,0.786929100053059,
1.),(1.,0.781896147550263,1.),(1.,0.779141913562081,1.),(1.,0.773692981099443,1.),(1.,
0.770998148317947,1.),(1.,0.768581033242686,1.))) REPRESENTATION_ITEM('') SURFACE());
#413=CARTESIAN_POINT('',(-0.298244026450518,-0.565291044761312,2.18460046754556));
#414=CARTESIAN_POINT('',(-0.323869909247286,-0.631592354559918,2.06827925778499));
#415=CARTESIAN_POINT('',(-0.348183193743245,-0.697894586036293,1.95177433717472));
#416=CARTESIAN_POINT('',(-0.392327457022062,-0.830809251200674,1.71817370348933));
#417=CARTESIAN_POINT('',(-0.412146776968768,-0.897422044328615,1.60107724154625));
#418=CARTESIAN_POINT('',(-0.445156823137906,-1.03037165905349,1.36764358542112));
#419=CARTESIAN_POINT('',(-0.45840136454,-1.09670616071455,1.25130818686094));
#420=CARTESIAN_POINT('',(-0.471894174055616,-1.19647796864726,1.07696947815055));
#421=CARTESIAN_POINT('',(-0.47532919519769,-1.22974836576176,1.01893927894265));
#422=CARTESIAN_POINT('',(-0.479937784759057,-1.29639869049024,0.902948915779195));
#423=CARTESIAN_POINT('',(-0.481112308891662,-1.32977856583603,0.844988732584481));
#424=CARTESIAN_POINT('',(-0.481077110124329,-1.44409900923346,0.646991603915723));
#425=CARTESIAN_POINT('',(-0.474125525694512,-1.52536823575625,0.507102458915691));
#426=CARTESIAN_POINT('',(-0.448329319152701,-1.68825541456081,0.22779718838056));
#427=CARTESIAN_POINT('',(-0.429474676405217,-1.76987360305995,0.0883815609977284));
#428=CARTESIAN_POINT('',(-0.383684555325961,-1.93319798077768,-0.190486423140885));
#429=CARTESIAN_POINT('',(-0.356721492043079,-2.01490350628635,-0.329937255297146));
#430=CARTESIAN_POINT('',(-0.297783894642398,-2.17794735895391,-0.608480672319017));
#431=CARTESIAN_POINT('',(-0.265810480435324,-2.25928576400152,-0.747573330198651));
#432=CARTESIAN_POINT('',(-0.198271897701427,-2.42277928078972,-1.02748594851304));
#433=CARTESIAN_POINT('',(-0.162662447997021,-2.50492974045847,-1.16830261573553));
#434=CARTESIAN_POINT('',(-0.0893859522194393,-2.66896199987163,-1.44976798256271));
#435=CARTESIAN_POINT('',(-0.0517188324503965,-2.7508437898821,-1.59041667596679));
#436=CARTESIAN_POINT('',(0.0631296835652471,-2.99586276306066,-2.01162764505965));
#437=CARTESIAN_POINT('',(0.14229785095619,-3.15869521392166,-2.29200600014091));
#438=CARTESIAN_POINT('',(0.307558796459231,-3.49274722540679,-2.86774384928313));
#439=CARTESIAN_POINT('',(0.393793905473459,-3.66394071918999,-3.16308783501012));
#440=CARTESIAN_POINT('',(0.567883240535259,-4.00612676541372,-3.75377470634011));
#441=CARTESIAN_POINT('',(0.655738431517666,-4.17711912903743,-4.04911747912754));
#442=CARTESIAN_POINT('',(0.830235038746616,-4.51477596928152,-4.63254027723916));
#443=CARTESIAN_POINT('',(0.916854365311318,-4.68144502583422,-4.92062306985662));
#444=CARTESIAN_POINT('',(1.09063636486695,-5.0145537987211,-5.49653403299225));
#445=CARTESIAN_POINT('',(1.17779867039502,-5.18099359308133,-5.78436225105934));
#446=CARTESIAN_POINT('',(1.26511791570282,-5.34739786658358,-6.07216835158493));
#447=B_SPLINE_CURVE_WITH_KNOTS('',3,(#413,#414,#415,#416,#417,#418,#419,#420,#421,#422,#423,
#424,#425,#426,#427,#428,#429,#430,#431,#432,#433,#434,#435,#436,#437,#438,#439,#440,#441,#442,
#443,#444,#445,#446),.UNSPECIFIED.,.F.,.F.,(4,2,2,2,2,2,2,2,2,2,2,2,2,2,2,2,4),(0.,
0.411234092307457,0.823523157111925,1.23237954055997,1.43641863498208,1.64037144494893,
2.13350633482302,2.62705692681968,3.12230595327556,3.6174444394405,4.11956328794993,
4.62170013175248,5.62400856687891,6.68089043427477,7.73842353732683,8.77036033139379,
9.80166162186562),.UNSPECIFIED.);
#448=CARTESIAN_POINT('',(-0.414778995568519,-1.82163895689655,0.));
#449=VERTEX_POINT('',#448);
#450=EDGE_CURVE('E364',#307,#449,#447,.T.);
#451=ORIENTED_EDGE('',*,*,#450,.T.);
#452=CARTESIAN_POINT('',(1.16852533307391,2.67982443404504,-7.64159207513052));
#453=CARTESIAN_POINT('',(1.26042918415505,2.6677532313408,-7.62068413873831));
#454=CARTESIAN_POINT('',(1.26511791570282,2.58495311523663,-7.66706657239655));
#455=CARTESIAN_POINT('',(1.08120608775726,2.51357832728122,-7.35364537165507));
#456=CARTESIAN_POINT('',(1.17299052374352,2.50166546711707,-7.3330116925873));
#457=CARTESIAN_POINT('',(1.17779867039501,2.41890785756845,-7.37905319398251));
#458=CARTESIAN_POINT('',(0.994043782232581,2.34731143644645,-7.06566266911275));
#459=CARTESIAN_POINT('',(1.08567092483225,2.33552666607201,-7.04525084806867));
#460=CARTESIAN_POINT('',(1.09063636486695,2.25286120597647,-7.09099799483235));
#461=CARTESIAN_POINT('',(0.820261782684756,2.0145973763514,-6.48938501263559));
#462=CARTESIAN_POINT('',(0.91144791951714,2.00295342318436,-6.46921709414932));
#463=CARTESIAN_POINT('',(0.916854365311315,1.92066206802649,-6.51456185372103));
#464=CARTESIAN_POINT('',(0.733642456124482,1.84815015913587,-6.20108997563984));
#465=CARTESIAN_POINT('',(0.824601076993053,1.83662898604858,-6.18113471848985));
#466=CARTESIAN_POINT('',(0.830235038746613,1.75450957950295,-6.22618082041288));
#467=CARTESIAN_POINT('',(0.559145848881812,1.51101153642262,-5.6171487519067));
#468=CARTESIAN_POINT('',(0.649509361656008,1.49966816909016,-5.59750146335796));
#469=CARTESIAN_POINT('',(0.655738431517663,1.41807903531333,-5.6420500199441));
#470=CARTESIAN_POINT('',(0.471290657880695,1.34031726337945,-5.32149759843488));
#471=CARTESIAN_POINT('',(0.561360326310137,1.32918114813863,-5.30220928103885));
#472=CARTESIAN_POINT('',(0.567883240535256,1.24780087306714,-5.34629490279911));
#473=CARTESIAN_POINT('',(0.297201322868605,0.998834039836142,-4.73003130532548));
#474=CARTESIAN_POINT('',(0.38644593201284,0.987956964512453,-4.71119165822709));
#475=CARTESIAN_POINT('',(0.393793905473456,0.907344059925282,-4.75460965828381));
#476=CARTESIAN_POINT('',(0.210966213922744,0.828045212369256,-4.43421637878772));
#477=CARTESIAN_POINT('',(0.299811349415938,0.817490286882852,-4.41593471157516));
#478=CARTESIAN_POINT('',(0.307558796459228,0.737165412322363,-4.45867975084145));
#479=CARTESIAN_POINT('',(0.04570526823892,0.494940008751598,-3.85726124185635));
#480=CARTESIAN_POINT('',(0.133379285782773,0.484748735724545,-3.83960943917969));
#481=CARTESIAN_POINT('',(0.142297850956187,0.405587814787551,-3.88151329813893));
#482=CARTESIAN_POINT('',(-0.0334628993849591,0.332641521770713,-3.57615201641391));
#483=CARTESIAN_POINT('',(0.0536678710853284,0.322953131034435,-3.55937123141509));
#484=CARTESIAN_POINT('',(0.063129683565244,0.244189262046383,-3.60030708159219));
#485=CARTESIAN_POINT('',(-0.148311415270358,0.0885639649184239,-3.15339728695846));
#486=CARTESIAN_POINT('',(-0.0626738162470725,0.0788132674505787,-3.13650858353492));
#487=CARTESIAN_POINT('',(-0.0517188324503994,0.00191934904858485,-3.17750894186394));
#488=CARTESIAN_POINT('',(-0.185978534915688,0.00701979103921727,-3.01215863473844));
#489=CARTESIAN_POINT('',(-0.100766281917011,-0.00247896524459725,-2.99570630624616));
#490=CARTESIAN_POINT('',(-0.0893859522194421,-0.0789450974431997,-3.03627288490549));
#491=CARTESIAN_POINT('',(-0.259255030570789,-0.156298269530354,-2.72928345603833));
#492=CARTESIAN_POINT('',(-0.175024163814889,-0.165307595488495,-2.71367884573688));
#493=CARTESIAN_POINT('',(-0.162662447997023,-0.240685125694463,-2.75348409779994));
#494=CARTESIAN_POINT('',(-0.294864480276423,-0.238072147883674,-2.58764694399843));
#495=CARTESIAN_POINT('',(-0.211154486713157,-0.246741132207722,-2.57263182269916));
#496=CARTESIAN_POINT('',(-0.19827189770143,-0.321560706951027,-2.61193137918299));
#497=CARTESIAN_POINT('',(-0.362403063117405,-0.400818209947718,-2.30576249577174));
#498=CARTESIAN_POINT('',(-0.279864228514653,-0.408806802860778,-2.29192584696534));
#499=CARTESIAN_POINT('',(-0.265810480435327,-0.482225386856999,-2.33038553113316));
#500=CARTESIAN_POINT('',(-0.394376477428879,-0.481785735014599,-2.1655226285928));
#501=CARTESIAN_POINT('',(-0.312456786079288,-0.489314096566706,-2.1524831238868));
#502=CARTESIAN_POINT('',(-0.2977838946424,-0.562013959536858,-2.19039807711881));
#503=CARTESIAN_POINT('',(-0.453314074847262,-0.64420682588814,-1.88420104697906));
#504=CARTESIAN_POINT('',(-0.372713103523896,-0.650745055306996,-1.87287650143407));
#505=CARTESIAN_POINT('',(-0.356721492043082,-0.721717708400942,-1.90992625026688));
#506=CARTESIAN_POINT('',(-0.480277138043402,-0.725660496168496,-1.74311915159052));
#507=CARTESIAN_POINT('',(-0.400383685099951,-0.731580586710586,-1.73286525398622));
#508=CARTESIAN_POINT('',(-0.383684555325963,-0.801632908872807,-1.76944177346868));
#509=CARTESIAN_POINT('',(-0.526067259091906,-0.888881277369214,-1.4604124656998));
#510=CARTESIAN_POINT('',(-0.447482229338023,-0.893400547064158,-1.45258486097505));
#511=CARTESIAN_POINT('',(-0.429474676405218,-0.961477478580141,-1.48856472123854));
#512=CARTESIAN_POINT('',(-0.544921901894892,-0.970646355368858,-1.31879119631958));
#513=CARTESIAN_POINT('',(-0.467016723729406,-0.974422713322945,-1.31225035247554));
#514=CARTESIAN_POINT('',(-0.448329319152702,-1.04140585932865,-1.348173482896));
#515=CARTESIAN_POINT('',(-0.570718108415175,-1.13462632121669,-1.03476956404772));
#516=CARTESIAN_POINT('',(-0.493671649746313,-1.13649888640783,-1.0315261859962));
#517=CARTESIAN_POINT('',(-0.474125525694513,-1.20184772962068,-1.06745641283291));
#518=CARTESIAN_POINT('',(-0.577669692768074,-1.21684077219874,-0.892369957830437));
#519=CARTESIAN_POINT('',(-0.500930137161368,-1.2179038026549,-0.890528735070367));
#520=CARTESIAN_POINT('',(-0.48107711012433,-1.28236066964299,-0.927130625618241));
#521=CARTESIAN_POINT('',(-0.577704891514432,-1.33303362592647,-0.69111803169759));
#522=CARTESIAN_POINT('',(-0.500975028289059,-1.33259321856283,-0.691880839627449));
#523=CARTESIAN_POINT('',(-0.481112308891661,-1.3966709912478,-0.729127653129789));
#524=CARTESIAN_POINT('',(-0.57653036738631,-1.36702621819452,-0.632241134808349));
#525=CARTESIAN_POINT('',(-0.499753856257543,-1.36616942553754,-0.633725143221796));
#526=CARTESIAN_POINT('',(-0.479937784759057,-1.43017604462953,-0.671239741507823));
#527=CARTESIAN_POINT('',(-0.571921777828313,-1.43498768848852,-0.514528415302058));
#528=CARTESIAN_POINT('',(-0.494976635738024,-1.4332771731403,-0.517491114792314));
#529=CARTESIAN_POINT('',(-0.47532919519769,-1.49730148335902,-0.555523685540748));
#530=CARTESIAN_POINT('',(-0.568486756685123,-1.46895655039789,-0.455692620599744));
#531=CARTESIAN_POINT('',(-0.491414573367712,-1.46684337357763,-0.459352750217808));
#532=CARTESIAN_POINT('',(-0.471894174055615,-1.53092191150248,-0.497695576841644));
#533=CARTESIAN_POINT('',(-0.554993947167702,-1.57088921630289,-0.279140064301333));
#534=CARTESIAN_POINT('',(-0.477436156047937,-1.56765525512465,-0.284741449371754));
#535=CARTESIAN_POINT('',(-0.458401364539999,-1.6320177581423,-0.324121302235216));
#536=CARTESIAN_POINT('',(-0.541749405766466,-1.63874915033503,-0.161603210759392));
#537=CARTESIAN_POINT('',(-0.463703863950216,-1.63485041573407,-0.168356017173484));
#538=CARTESIAN_POINT('',(-0.445156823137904,-1.69959991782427,-0.208506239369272));
#539=CARTESIAN_POINT('',(-0.508739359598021,-1.77462324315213,0.0737376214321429));
#540=CARTESIAN_POINT('',(-0.429692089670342,-1.76940488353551,0.0646991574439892));
#541=CARTESIAN_POINT('',(-0.412146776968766,-1.83528458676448,0.0233483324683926));
#542=CARTESIAN_POINT('',(-0.48892003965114,-1.84263391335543,0.191535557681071));
#543=CARTESIAN_POINT('',(-0.40929760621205,-1.83683303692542,0.181488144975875));
#544=CARTESIAN_POINT('',(-0.392327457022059,-1.90338670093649,0.139584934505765));
#545=CARTESIAN_POINT('',(-0.444775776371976,-1.97811547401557,0.426196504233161));
#546=CARTESIAN_POINT('',(-0.364005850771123,-1.97135383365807,0.414484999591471));
#547=CARTESIAN_POINT('',(-0.348183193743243,-2.039233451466,0.37149272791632));
#548=CARTESIAN_POINT('',(-0.420462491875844,-2.04558730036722,0.54306113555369));
#549=CARTESIAN_POINT('',(-0.339090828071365,-2.03843783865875,0.530677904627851));
#550=CARTESIAN_POINT('',(-0.323869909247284,-2.10697855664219,0.487164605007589));
#551=CARTESIAN_POINT('',(-0.394836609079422,-2.11290400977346,0.659657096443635));
#552=CARTESIAN_POINT('',(-0.31307781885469,-2.10509238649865,0.646126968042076));
#553=CARTESIAN_POINT('',(-0.298244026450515,-2.17456502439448,0.602743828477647));
#554=(BOUNDED_SURFACE() B_SPLINE_SURFACE(3,2,((#452,#453,#454),(#455,#456,#457),(#458,#459,
#460),(#461,#462,#463),(#464,#465,#466),(#467,#468,#469),(#470,#471,#472),(#473,#474,#475),
(#476,#477,#478),(#479,#480,#481),(#482,#483,#484),(#485,#486,#487),(#488,#489,#490),(#491,#492,
#493),(#494,#495,#496),(#497,#498,#499),(#500,#501,#502),(#503,#504,#505),(#506,#507,#508),
(#509,#510,#511),(#512,#513,#514),(#515,#516,#517),(#518,#519,#520),(#521,#522,#523),(#524,#525,
#526),(#527,#528,#529),(#530,#531,#532),(#533,#534,#535),(#536,#537,#538),(#539,#540,#541),
(#542,#543,#544),(#545,#546,#547),(#548,#549,#550),(#551,#552,#553)),.UNSPECIFIED.,.F.,.F.,
.F.) B_SPLINE_SURFACE_WITH_KNOTS((4,2,2,2,2,2,2,2,2,2,2,2,2,2,2,2,4),(3,3),(0.,1.03130129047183,
2.06323808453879,3.12077118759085,4.17765305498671,5.17996149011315,5.6820983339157,
6.18421718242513,6.67935566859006,7.17460469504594,7.6681552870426,8.1612901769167,
8.36524298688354,8.56928208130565,8.9781384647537,9.39042752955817,9.80166162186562),(0.,1.),
.UNSPECIFIED.) GEOMETRIC_REPRESENTATION_ITEM() RATIONAL_B_SPLINE_SURFACE(((1.,0.724919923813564,
1.),(1.,0.725634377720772,1.),(1.,0.726416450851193,1.),(1.,0.728221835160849,1.),(1.,
0.729245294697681,1.),(1.,0.731668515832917,1.),(1.,0.733076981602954,1.),(1.,0.736473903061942,
1.),(1.,0.738462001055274,1.),(1.,0.743282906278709,1.),(1.,0.746066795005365,1.),(1.,
0.751359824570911,1.),(1.,0.75331282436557,1.),(1.,0.757692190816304,1.),(1.,0.760118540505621,
1.),(1.,0.765471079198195,1.),(1.,0.768389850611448,1.),(1.,0.774638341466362,1.),(1.,
0.777968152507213,1.),(1.,0.784396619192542,1.),(1.,0.78749602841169,1.),(1.,0.791967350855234,
1.),(1.,0.793340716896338,1.),(1.,0.793358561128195,1.),(1.,0.79313102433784,1.),(1.,
0.792266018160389,1.),(1.,0.791628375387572,1.),(1.,0.789211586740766,1.),(1.,0.786929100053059,
1.),(1.,0.781896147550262,1.),(1.,0.779141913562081,1.),(1.,0.773692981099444,1.),(1.,
0.770998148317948,1.),(1.,0.768581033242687,1.))) REPRESENTATION_ITEM('') SURFACE());
#555=CARTESIAN_POINT('',(-0.298244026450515,-2.17456502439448,0.602743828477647));
#556=CARTESIAN_POINT('',(-0.323869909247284,-2.10697855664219,0.487164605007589));
#557=CARTESIAN_POINT('',(-0.348183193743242,-2.039233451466,0.37149272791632));
#558=CARTESIAN_POINT('',(-0.392327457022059,-1.90338670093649,0.139584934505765));
#559=CARTESIAN_POINT('',(-0.412146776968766,-1.83528458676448,0.0233483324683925));
#560=CARTESIAN_POINT('',(-0.445156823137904,-1.69959991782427,-0.208506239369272));
#561=CARTESIAN_POINT('',(-0.458401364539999,-1.6320177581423,-0.324121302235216));
#562=CARTESIAN_POINT('',(-0.471894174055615,-1.53092191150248,-0.497695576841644));
#563=CARTESIAN_POINT('',(-0.47532919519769,-1.49730148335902,-0.555523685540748));
#564=CARTESIAN_POINT('',(-0.479937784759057,-1.43017604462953,-0.671239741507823));
#565=CARTESIAN_POINT('',(-0.481112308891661,-1.3966709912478,-0.729127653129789));
#566=CARTESIAN_POINT('',(-0.48107711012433,-1.28236066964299,-0.927130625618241));
#567=CARTESIAN_POINT('',(-0.474125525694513,-1.20184772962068,-1.06745641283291));
#568=CARTESIAN_POINT('',(-0.448329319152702,-1.04140585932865,-1.348173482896));
#569=CARTESIAN_POINT('',(-0.429474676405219,-0.961477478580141,-1.48856472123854));
#570=CARTESIAN_POINT('',(-0.383684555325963,-0.801632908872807,-1.76944177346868));
#571=CARTESIAN_POINT('',(-0.356721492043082,-0.721717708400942,-1.90992625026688));
#572=CARTESIAN_POINT('',(-0.297783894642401,-0.562013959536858,-2.19039807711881));
#573=CARTESIAN_POINT('',(-0.265810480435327,-0.482225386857,-2.33038553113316));
#574=CARTESIAN_POINT('',(-0.19827189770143,-0.321560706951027,-2.61193137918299));
#575=CARTESIAN_POINT('',(-0.162662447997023,-0.240685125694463,-2.75348409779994));
#576=CARTESIAN_POINT('',(-0.0893859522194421,-0.0789450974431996,-3.03627288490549));
#577=CARTESIAN_POINT('',(-0.0517188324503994,0.00191934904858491,-3.17750894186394));
#578=CARTESIAN_POINT('',(0.063129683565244,0.244189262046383,-3.60030708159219));
#579=CARTESIAN_POINT('',(0.142297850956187,0.405587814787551,-3.88151329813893));
#580=CARTESIAN_POINT('',(0.307558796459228,0.737165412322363,-4.45867975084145));
#581=CARTESIAN_POINT('',(0.393793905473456,0.907344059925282,-4.75460965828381));
#582=CARTESIAN_POINT('',(0.567883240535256,1.24780087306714,-5.34629490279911));
#583=CARTESIAN_POINT('',(0.655738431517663,1.41807903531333,-5.6420500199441));
#584=CARTESIAN_POINT('',(0.830235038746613,1.75450957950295,-6.22618082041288));
#585=CARTESIAN_POINT('',(0.916854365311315,1.92066206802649,-6.51456185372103));
#586=CARTESIAN_POINT('',(1.09063636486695,2.25286120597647,-7.09099799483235));
#587=CARTESIAN_POINT('',(1.17779867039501,2.41890785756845,-7.37905319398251));
#588=CARTESIAN_POINT('',(1.26511791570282,2.58495311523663,-7.66706657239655));
#589=B_SPLINE_CURVE_WITH_KNOTS('',3,(#555,#556,#557,#558,#559,#560,#561,#562,#563,#564,#565,
#566,#567,#568,#569,#570,#571,#572,#573,#574,#575,#576,#577,#578,#579,#580,#581,#582,#583,#584,
#585,#586,#587,#588),.UNSPECIFIED.,.F.,.F.,(4,2,2,2,2,2,2,2,2,2,2,2,2,2,2,2,4),(0.,
0.411234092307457,0.823523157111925,1.23237954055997,1.43641863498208,1.64037144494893,
2.13350633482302,2.62705692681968,3.12230595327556,3.6174444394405,4.11956328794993,
4.62170013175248,5.62400856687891,6.68089043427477,7.73842353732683,8.7703603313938,
9.80166162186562),.UNSPECIFIED.);
#590=CARTESIAN_POINT('',(-0.414778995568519,-0.910819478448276,-1.5775856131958));
#591=VERTEX_POINT('',#590);
#592=EDGE_CURVE('E357',#449,#591,#589,.T.);
#593=ORIENTED_EDGE('',*,*,#592,.T.);
#594=CARTESIAN_POINT('',(1.16889621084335,7.95913690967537,-1.5));
#595=CARTESIAN_POINT('',(1.26080082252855,7.93499413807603,-1.5));
#596=CARTESIAN_POINT('',(1.26548879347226,7.93376263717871,-1.59489909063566));
#597=CARTESIAN_POINT('',(1.08157666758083,7.62664593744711,-1.5));
#598=CARTESIAN_POINT('',(1.17336191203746,7.60281977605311,-1.5));
#599=CARTESIAN_POINT('',(1.17816925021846,7.60131432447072,-1.59469188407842));
#600=CARTESIAN_POINT('',(0.994413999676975,7.29411341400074,-1.5));
#601=CARTESIAN_POINT('',(1.08604199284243,7.27054329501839,-1.5));
#602=CARTESIAN_POINT('',(1.09100658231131,7.26882911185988,-1.59446498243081));
#603=CARTESIAN_POINT('',(0.820630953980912,6.62868803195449,-1.5));
#604=CARTESIAN_POINT('',(0.911818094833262,6.60539940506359,-1.5));
#605=CARTESIAN_POINT('',(0.91722353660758,6.60352386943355,-1.59394000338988));
#606=CARTESIAN_POINT('',(0.734010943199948,6.29579507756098,-1.5));
#607=CARTESIAN_POINT('',(0.824970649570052,6.27275188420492,-1.5));
#608=CARTESIAN_POINT('',(0.830603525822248,6.27070375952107,-1.59364188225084));
#609=CARTESIAN_POINT('',(0.55951563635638,5.62153363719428,-1.5));
#610=CARTESIAN_POINT('',(0.649880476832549,5.598845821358,-1.5));
#611=CARTESIAN_POINT('',(0.656108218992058,5.59663204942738,-1.59293419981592));
#612=CARTESIAN_POINT('',(0.471662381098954,5.28015942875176,-1.5));
#613=CARTESIAN_POINT('',(0.561733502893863,5.25788583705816,-1.5));
#614=CARTESIAN_POINT('',(0.568254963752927,5.25537577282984,-1.59252206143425));
#615=CARTESIAN_POINT('',(0.297575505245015,4.59722184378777,-1.5));
#616=CARTESIAN_POINT('',(0.386821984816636,4.57546596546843,-1.5));
#617=CARTESIAN_POINT('',(0.394168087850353,4.5727615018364,-1.59152423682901));
#618=CARTESIAN_POINT('',(0.211340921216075,4.25565871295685,-1.5));
#619=CARTESIAN_POINT('',(0.300188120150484,4.23454661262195,-1.5));
#620=CARTESIAN_POINT('',(0.307933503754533,4.23140369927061,-1.59093865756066));
#621=CARTESIAN_POINT('',(0.0460744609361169,3.58946258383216,-1.5));
#622=CARTESIAN_POINT('',(0.133751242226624,3.56907728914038,-1.5));
#623=CARTESIAN_POINT('',(0.142667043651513,3.56578778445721,-1.58951095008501));
#624=CARTESIAN_POINT('',(-0.0330994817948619,3.2648652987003,-1.5));
#625=CARTESIAN_POINT('',(0.0540343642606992,3.24548495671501,-1.5));
#626=CARTESIAN_POINT('',(0.0634931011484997,3.24155609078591,-1.58868361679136));
#627=CARTESIAN_POINT('',(-0.147961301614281,2.77671102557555,-1.5));
#628=CARTESIAN_POINT('',(-0.0623197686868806,2.75720580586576,-1.5));
#629=CARTESIAN_POINT('',(-0.0513687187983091,2.75426701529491,-1.58709751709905));
#630=CARTESIAN_POINT('',(-0.185633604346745,2.61362332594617,-1.5));
#631=CARTESIAN_POINT('',(-0.100417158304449,2.59462151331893,-1.5));
#632=CARTESIAN_POINT('',(-0.0890410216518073,2.59152100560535,-1.58651055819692));
#633=CARTESIAN_POINT('',(-0.258923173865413,2.2869890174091,-1.5));
#634=CARTESIAN_POINT('',(-0.174687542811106,2.26896504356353,-1.5));
#635=CARTESIAN_POINT('',(-0.162330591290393,2.26574940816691,-1.5851880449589));
#636=CARTESIAN_POINT('',(-0.29454051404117,2.12344242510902,-1.5));
#637=CARTESIAN_POINT('',(-0.210825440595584,2.10609846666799,-1.5));
#638=CARTESIAN_POINT('',(-0.197947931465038,2.10272383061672,-1.58445249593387));
#639=CARTESIAN_POINT('',(-0.362099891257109,1.79795065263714,-1.5));
#640=CARTESIAN_POINT('',(-0.279555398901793,1.78196596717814,-1.5));
#641=CARTESIAN_POINT('',(-0.265507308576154,1.77856413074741,-1.5828202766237));
#642=CARTESIAN_POINT('',(-0.394086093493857,1.63601476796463,-1.5));
#643=CARTESIAN_POINT('',(-0.312160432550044,1.62094967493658,-1.5));
#644=CARTESIAN_POINT('',(-0.297493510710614,1.61743517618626,-1.58192598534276));
#645=CARTESIAN_POINT('',(-0.453056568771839,1.31117166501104,-1.5));
#646=CARTESIAN_POINT('',(-0.372449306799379,1.29808462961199,-1.5));
#647=CARTESIAN_POINT('',(-0.356463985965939,1.29468370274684,-1.57999831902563));
#648=CARTESIAN_POINT('',(-0.480039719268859,1.14826423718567,-1.5));
#649=CARTESIAN_POINT('',(-0.400139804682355,1.13641252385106,-1.5));
#650=CARTESIAN_POINT('',(-0.383447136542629,1.13306108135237,-1.57896491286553));
#651=CARTESIAN_POINT('',(-0.525880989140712,0.821822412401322,-1.5));
#652=CARTESIAN_POINT('',(-0.447290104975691,0.81276949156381,-1.5));
#653=CARTESIAN_POINT('',(-0.429288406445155,0.809887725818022,-1.57695527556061));
#654=CARTESIAN_POINT('',(-0.544766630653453,0.658292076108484,-1.5));
#655=CARTESIAN_POINT('',(-0.466856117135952,0.650724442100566,-1.5));
#656=CARTESIAN_POINT('',(-0.44817404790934,0.64833864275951,-1.57597886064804));
#657=CARTESIAN_POINT('',(-0.570635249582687,0.330329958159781,-1.5));
#658=CARTESIAN_POINT('',(-0.493585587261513,0.326567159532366,-1.5));
#659=CARTESIAN_POINT('',(-0.474042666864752,0.325003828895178,-1.57456380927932));
#660=CARTESIAN_POINT('',(-0.577628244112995,0.165899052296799,-1.5));
#661=CARTESIAN_POINT('',(-0.50088718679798,0.163755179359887,-1.5));
#662=CARTESIAN_POINT('',(-0.481035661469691,0.163218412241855,-1.57412472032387));
#663=CARTESIAN_POINT('',(-0.577721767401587,-0.0664918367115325,-1.5));
#664=CARTESIAN_POINT('',(-0.500992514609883,-0.0656299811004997,-1.5));
#665=CARTESIAN_POINT('',(-0.481129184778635,-0.0654174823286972,-1.57411537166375));
#666=CARTESIAN_POINT('',(-0.576564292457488,-0.134478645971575,-1.5));
#667=CARTESIAN_POINT('',(-0.499789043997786,-0.132783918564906,-1.5));
#668=CARTESIAN_POINT('',(-0.479971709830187,-0.132303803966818,-1.57418661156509));
#669=CARTESIAN_POINT('',(-0.571988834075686,-0.270405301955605,-1.5));
#670=CARTESIAN_POINT('',(-0.495046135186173,-0.267002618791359,-1.5));
#671=CARTESIAN_POINT('',(-0.475396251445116,-0.26608246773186,-1.57445901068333));
#672=CARTESIAN_POINT('',(-0.56856989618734,-0.338345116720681,-1.5));
#673=CARTESIAN_POINT('',(-0.49150071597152,-0.334136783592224,-1.5));
#674=CARTESIAN_POINT('',(-0.47197731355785,-0.332974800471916,-1.574660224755));
#675=CARTESIAN_POINT('',(-0.555122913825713,-0.542216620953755,-1.5));
#676=CARTESIAN_POINT('',(-0.477569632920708,-0.535764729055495,-1.5));
#677=CARTESIAN_POINT('',(-0.458530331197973,-0.5338465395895,-1.57542240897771));
#678=CARTESIAN_POINT('',(-0.541905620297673,-0.677941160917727,-1.5));
#679=CARTESIAN_POINT('',(-0.463865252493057,-0.670159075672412,-1.5));
#680=CARTESIAN_POINT('',(-0.445313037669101,-0.667766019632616,-1.57614175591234));
#681=CARTESIAN_POINT('',(-0.508942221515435,-0.949697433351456,-1.5));
#682=CARTESIAN_POINT('',(-0.429900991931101,-0.939273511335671,-1.5));
#683=CARTESIAN_POINT('',(-0.41234963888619,-0.93640482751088,-1.57771976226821));
#684=CARTESIAN_POINT('',(-0.489142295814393,-1.08572219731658,-1.5));
#685=CARTESIAN_POINT('',(-0.409525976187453,-1.07413229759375,-1.5));
#686=CARTESIAN_POINT('',(-0.392549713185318,-1.07112144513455,-1.57857953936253));
#687=CARTESIAN_POINT('',(-0.445030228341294,-1.35669295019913,-1.5));
#688=CARTESIAN_POINT('',(-0.364266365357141,-1.34317962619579,-1.5));
#689=CARTESIAN_POINT('',(-0.348437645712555,-1.33988746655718,-1.58027266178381));
#690=CARTESIAN_POINT('',(-0.42072972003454,-1.49164080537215,-1.5));
#691=CARTESIAN_POINT('',(-0.33936386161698,-1.47735137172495,-1.5));
#692=CARTESIAN_POINT('',(-0.324137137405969,-1.47393769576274,-1.58110606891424));
#693=CARTESIAN_POINT('',(-0.395114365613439,-1.62627794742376,-1.5));
#694=CARTESIAN_POINT('',(-0.31336127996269,-1.610662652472,-1.5));
#695=CARTESIAN_POINT('',(-0.298521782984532,-1.60782822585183,-1.58184839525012));
#696=(BOUNDED_SURFACE() B_SPLINE_SURFACE(3,2,((#594,#595,#596),(#597,#598,#599),(#600,#601,
#602),(#603,#604,#605),(#606,#607,#608),(#609,#610,#611),(#612,#613,#614),(#615,#616,#617),
(#618,#619,#620),(#621,#622,#623),(#624,#625,#626),(#627,#628,#629),(#630,#631,#632),(#633,#634,
#635),(#636,#637,#638),(#639,#640,#641),(#642,#643,#644),(#645,#646,#647),(#648,#649,#650),
(#651,#652,#653),(#654,#655,#656),(#657,#658,#659),(#660,#661,#662),(#663,#664,#665),(#666,#667,
#668),(#669,#670,#671),(#672,#673,#674),(#675,#676,#677),(#678,#679,#680),(#681,#682,#683),
(#684,#685,#686),(#687,#688,#689),(#690,#691,#692),(#693,#694,#695)),.UNSPECIFIED.,.F.,.F.,
.F.) B_SPLINE_SURFACE_WITH_KNOTS((4,2,2,2,2,2,2,2,2,2,2,2,2,2,2,2,4),(3,3),(0.,1.03129791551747,
2.06323092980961,3.12072093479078,4.17756017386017,5.17987368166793,5.68201215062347,
6.18413267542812,6.67928118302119,7.17454065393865,7.66810321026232,8.1612498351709,
8.36520660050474,8.56924950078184,8.97811142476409,9.390402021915,9.8016414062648),(0.,1.),
.UNSPECIFIED.) GEOMETRIC_REPRESENTATION_ITEM() RATIONAL_B_SPLINE_SURFACE(((1.,0.724916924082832,
1.),(1.,0.725631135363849,1.),(1.,0.726412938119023,1.),(1.,0.728217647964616,1.),(1.,
0.72924070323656,1.),(1.,0.731662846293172,1.),(1.,0.733070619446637,1.),(1.,0.736465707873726,
1.),(1.,0.738452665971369,1.),(1.,0.743270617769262,1.),(1.,0.746052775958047,1.),(1.,
0.751342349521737,1.),(1.,0.753294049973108,1.),(1.,0.757670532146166,1.),(1.,0.760095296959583,
1.),(1.,0.765444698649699,1.),(1.,0.76836192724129,1.),(1.,0.774608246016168,1.),(1.,
0.777937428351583,1.),(1.,0.784367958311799,1.),(1.,0.787470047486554,1.),(1.,0.791951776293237,
1.),(1.,0.793332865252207,1.),(1.,0.793361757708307,1.),(1.,0.793137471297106,1.),(1.,
0.792278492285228,1.),(1.,0.791643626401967,1.),(1.,0.78923400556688,1.),(1.,0.786954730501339,
1.),(1.,0.781925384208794,1.),(1.,0.779171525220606,1.),(1.,0.773721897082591,1.),(1.,
0.771025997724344,1.),(1.,0.768607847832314,1.))) REPRESENTATION_ITEM('') SURFACE());
#697=CARTESIAN_POINT('',(-0.298521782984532,-1.60782822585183,-1.58184839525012));
#698=CARTESIAN_POINT('',(-0.324137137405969,-1.47393769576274,-1.58110606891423));
#699=CARTESIAN_POINT('',(-0.348437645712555,-1.33988746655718,-1.58027266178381));
#700=CARTESIAN_POINT('',(-0.392549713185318,-1.07112144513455,-1.57857953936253));
#701=CARTESIAN_POINT('',(-0.41234963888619,-0.93640482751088,-1.57771976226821));
#702=CARTESIAN_POINT('',(-0.445313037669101,-0.667766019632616,-1.57614175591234));
#703=CARTESIAN_POINT('',(-0.458530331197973,-0.5338465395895,-1.57542240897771));
#704=CARTESIAN_POINT('',(-0.47197731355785,-0.332974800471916,-1.574660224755));
#705=CARTESIAN_POINT('',(-0.475396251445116,-0.26608246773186,-1.57445901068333));
#706=CARTESIAN_POINT('',(-0.479971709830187,-0.132303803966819,-1.57418661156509));
#707=CARTESIAN_POINT('',(-0.481129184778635,-0.0654174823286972,-1.57411537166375));
#708=CARTESIAN_POINT('',(-0.481035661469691,0.163218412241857,-1.57412472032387));
#709=CARTESIAN_POINT('',(-0.474042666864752,0.325003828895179,-1.57456380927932));
#710=CARTESIAN_POINT('',(-0.44817404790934,0.64833864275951,-1.57597886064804));
#711=CARTESIAN_POINT('',(-0.429288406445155,0.809887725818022,-1.57695527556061));
#712=CARTESIAN_POINT('',(-0.383447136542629,1.13306108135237,-1.57896491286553));
#713=CARTESIAN_POINT('',(-0.356463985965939,1.29468370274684,-1.57999831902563));
#714=CARTESIAN_POINT('',(-0.297493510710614,1.61743517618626,-1.58192598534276));
#715=CARTESIAN_POINT('',(-0.265507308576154,1.77856413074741,-1.5828202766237));
#716=CARTESIAN_POINT('',(-0.197947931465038,2.10272383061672,-1.58445249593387));
#717=CARTESIAN_POINT('',(-0.162330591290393,2.26574940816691,-1.5851880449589));
#718=CARTESIAN_POINT('',(-0.0890410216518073,2.59152100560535,-1.58651055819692));
#719=CARTESIAN_POINT('',(-0.0513687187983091,2.75426701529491,-1.58709751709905));
#720=CARTESIAN_POINT('',(0.0634931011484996,3.24155609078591,-1.58868361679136));
#721=CARTESIAN_POINT('',(0.142667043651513,3.56578778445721,-1.58951095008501));
#722=CARTESIAN_POINT('',(0.307933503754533,4.23140369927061,-1.59093865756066));
#723=CARTESIAN_POINT('',(0.394168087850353,4.5727615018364,-1.59152423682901));
#724=CARTESIAN_POINT('',(0.568254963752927,5.25537577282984,-1.59252206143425));
#725=CARTESIAN_POINT('',(0.656108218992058,5.59663204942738,-1.59293419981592));
#726=CARTESIAN_POINT('',(0.830603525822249,6.27070375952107,-1.59364188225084));
#727=CARTESIAN_POINT('',(0.91722353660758,6.60352386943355,-1.59394000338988));
#728=CARTESIAN_POINT('',(1.09100658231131,7.26882911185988,-1.59446498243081));
#729=CARTESIAN_POINT('',(1.17816925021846,7.60131432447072,-1.59469188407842));
#730=CARTESIAN_POINT('',(1.26548879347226,7.93376263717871,-1.59489909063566));
#731=B_SPLINE_CURVE_WITH_KNOTS('',3,(#697,#698,#699,#700,#701,#702,#703,#704,#705,#706,#707,
#708,#709,#710,#711,#712,#713,#714,#715,#716,#717,#718,#719,#720,#721,#722,#723,#724,#725,#726,
#727,#728,#729,#730),.UNSPECIFIED.,.F.,.F.,(4,2,2,2,2,2,2,2,2,2,2,2,2,2,2,2,4),(0.,
0.411239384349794,0.823529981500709,1.23239190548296,1.43643480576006,1.6403915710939,
2.13353819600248,2.62710075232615,3.1223602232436,3.61750873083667,4.11962925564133,
4.62176772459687,5.62408123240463,6.68092047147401,7.73841047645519,8.77034349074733,
9.8016414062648),.UNSPECIFIED.);
#732=CARTESIAN_POINT('',(-0.414778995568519,0.910819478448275,-1.5775856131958));
#733=VERTEX_POINT('',#732);
#734=EDGE_CURVE('E365',#591,#733,#731,.T.);
#735=ORIENTED_EDGE('',*,*,#734,.T.);
#736=CARTESIAN_POINT('',(1.16852533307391,5.27790064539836,6.14159207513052));
#737=CARTESIAN_POINT('',(1.26042918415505,5.26582944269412,6.12068413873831));
#738=CARTESIAN_POINT('',(1.26511791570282,5.34739786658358,6.07216835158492));
#739=CARTESIAN_POINT('',(1.08120608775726,5.11165453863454,5.85364537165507));
#740=CARTESIAN_POINT('',(1.17299052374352,5.09974167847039,5.8330116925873));
#741=CARTESIAN_POINT('',(1.17779867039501,5.18099359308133,5.78436225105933));
#742=CARTESIAN_POINT('',(0.994043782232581,4.94538764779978,5.56566266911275));
#743=CARTESIAN_POINT('',(1.08567092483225,4.93360287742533,5.54525084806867));
#744=CARTESIAN_POINT('',(1.09063636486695,5.0145537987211,5.49653403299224));
#745=CARTESIAN_POINT('',(0.820261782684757,4.61267358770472,4.98938501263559));
#746=CARTESIAN_POINT('',(0.911447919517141,4.60102963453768,4.96921709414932));
#747=CARTESIAN_POINT('',(0.916854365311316,4.68144502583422,4.92062306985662));
#748=CARTESIAN_POINT('',(0.733642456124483,4.4462263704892,4.70108997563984));
#749=CARTESIAN_POINT('',(0.824601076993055,4.4347051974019,4.68113471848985));
#750=CARTESIAN_POINT('',(0.830235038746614,4.51477596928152,4.63254027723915));
#751=CARTESIAN_POINT('',(0.559145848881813,4.10908774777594,4.1171487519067));
#752=CARTESIAN_POINT('',(0.64950936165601,4.09774438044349,4.09750146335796));
#753=CARTESIAN_POINT('',(0.655738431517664,4.17711912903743,4.04911747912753));
#754=CARTESIAN_POINT('',(0.471290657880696,3.93839347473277,3.82149759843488));
#755=CARTESIAN_POINT('',(0.561360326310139,3.92725735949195,3.80220928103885));
#756=CARTESIAN_POINT('',(0.567883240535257,4.00612676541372,3.7537747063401));
#757=CARTESIAN_POINT('',(0.297201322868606,3.59691025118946,3.23003130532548));
#758=CARTESIAN_POINT('',(0.386445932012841,3.58603317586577,3.21119165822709));
#759=CARTESIAN_POINT('',(0.393793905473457,3.66394071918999,3.16308783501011));
#760=CARTESIAN_POINT('',(0.210966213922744,3.42612142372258,2.93421637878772));
#761=CARTESIAN_POINT('',(0.299811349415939,3.41556649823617,2.91593471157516));
#762=CARTESIAN_POINT('',(0.307558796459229,3.49274722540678,2.86774384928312));
#763=CARTESIAN_POINT('',(0.0457052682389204,3.09301622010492,2.35726124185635));
#764=CARTESIAN_POINT('',(0.133379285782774,3.08282494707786,2.33960943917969));
#765=CARTESIAN_POINT('',(0.142297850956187,3.15869521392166,2.2920060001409));
#766=CARTESIAN_POINT('',(-0.0334628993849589,2.93071773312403,2.0761520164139));
#767=CARTESIAN_POINT('',(0.0536678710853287,2.92102934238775,2.05937123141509));
#768=CARTESIAN_POINT('',(0.0631296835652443,2.99586276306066,2.01162764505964));
#769=CARTESIAN_POINT('',(-0.148311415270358,2.68664017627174,1.65339728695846));
#770=CARTESIAN_POINT('',(-0.0626738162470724,2.6768894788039,1.63650858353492));
#771=CARTESIAN_POINT('',(-0.0517188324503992,2.75084378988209,1.59041667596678));
#772=CARTESIAN_POINT('',(-0.185978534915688,2.60509600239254,1.51215863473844));
#773=CARTESIAN_POINT('',(-0.100766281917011,2.59559724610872,1.49570630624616));
#774=CARTESIAN_POINT('',(-0.089385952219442,2.66896199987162,1.4497679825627));
#775=CARTESIAN_POINT('',(-0.259255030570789,2.44177794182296,1.22928345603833));
#776=CARTESIAN_POINT('',(-0.175024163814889,2.43276861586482,1.21367884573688));
#777=CARTESIAN_POINT('',(-0.162662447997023,2.50492974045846,1.16830261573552));
#778=CARTESIAN_POINT('',(-0.294864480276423,2.36000406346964,1.08764694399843));
#779=CARTESIAN_POINT('',(-0.211154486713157,2.3513350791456,1.07263182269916));
#780=CARTESIAN_POINT('',(-0.198271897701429,2.42277928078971,1.02748594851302));
#781=CARTESIAN_POINT('',(-0.362403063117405,2.1972580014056,0.805762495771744));
#782=CARTESIAN_POINT('',(-0.279864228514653,2.18926940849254,0.79192584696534));
#783=CARTESIAN_POINT('',(-0.265810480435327,2.25928576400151,0.74757333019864));
#784=CARTESIAN_POINT('',(-0.394376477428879,2.11629047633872,0.6655226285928));
#785=CARTESIAN_POINT('',(-0.312456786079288,2.10876211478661,0.652483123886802));
#786=CARTESIAN_POINT('',(-0.2977838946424,2.1779473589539,0.608480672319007));
#787=CARTESIAN_POINT('',(-0.453314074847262,1.95386938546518,0.384201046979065));
#788=CARTESIAN_POINT('',(-0.372713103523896,1.94733115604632,0.372876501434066));
#789=CARTESIAN_POINT('',(-0.356721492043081,2.01490350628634,0.329937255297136));
#790=CARTESIAN_POINT('',(-0.480277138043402,1.87241571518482,0.243119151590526));
#791=CARTESIAN_POINT('',(-0.40038368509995,1.86649562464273,0.232865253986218));
#792=CARTESIAN_POINT('',(-0.383684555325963,1.93319798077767,0.190486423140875));
#793=CARTESIAN_POINT('',(-0.526067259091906,1.7091949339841,-0.0395875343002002));
#794=CARTESIAN_POINT('',(-0.447482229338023,1.70467566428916,-0.0474151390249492));
#795=CARTESIAN_POINT('',(-0.429474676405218,1.76987360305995,-0.0883815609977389));
#796=CARTESIAN_POINT('',(-0.544921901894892,1.62742985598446,-0.181208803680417));
#797=CARTESIAN_POINT('',(-0.467016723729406,1.62365349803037,-0.187749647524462));
#798=CARTESIAN_POINT('',(-0.448329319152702,1.68825541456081,-0.227797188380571));
#799=CARTESIAN_POINT('',(-0.570718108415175,1.46344989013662,-0.465230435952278));
#800=CARTESIAN_POINT('',(-0.493671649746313,1.46157732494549,-0.468473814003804));
#801=CARTESIAN_POINT('',(-0.474125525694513,1.52536823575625,-0.507102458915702));
#802=CARTESIAN_POINT('',(-0.577669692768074,1.38123543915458,-0.607630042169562));
#803=CARTESIAN_POINT('',(-0.500930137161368,1.38017240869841,-0.609471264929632));
#804=CARTESIAN_POINT('',(-0.48107711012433,1.44409900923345,-0.646991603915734));
#805=CARTESIAN_POINT('',(-0.577704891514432,1.26504258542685,-0.808881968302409));
#806=CARTESIAN_POINT('',(-0.500975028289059,1.26548299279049,-0.80811916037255));
#807=CARTESIAN_POINT('',(-0.481112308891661,1.32977856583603,-0.844988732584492));
#808=CARTESIAN_POINT('',(-0.57653036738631,1.23104999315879,-0.86775886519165));
#809=CARTESIAN_POINT('',(-0.499753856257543,1.23190678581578,-0.866274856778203));
#810=CARTESIAN_POINT('',(-0.479937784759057,1.29639869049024,-0.902948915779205));
#811=CARTESIAN_POINT('',(-0.571921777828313,1.16308852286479,-0.98547158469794));
#812=CARTESIAN_POINT('',(-0.494976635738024,1.16479903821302,-0.982508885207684));
#813=CARTESIAN_POINT('',(-0.47532919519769,1.22974836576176,-1.01893927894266));
#814=CARTESIAN_POINT('',(-0.568486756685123,1.12911966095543,-1.04430737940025));
#815=CARTESIAN_POINT('',(-0.491414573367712,1.13123283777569,-1.04064724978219));
#816=CARTESIAN_POINT('',(-0.471894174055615,1.19647796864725,-1.07696947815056));
#817=CARTESIAN_POINT('',(-0.554993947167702,1.02718699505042,-1.22085993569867));
#818=CARTESIAN_POINT('',(-0.477436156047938,1.03042095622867,-1.21525855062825));
#819=CARTESIAN_POINT('',(-0.458401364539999,1.09670616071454,-1.25130818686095));
#820=CARTESIAN_POINT('',(-0.541749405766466,0.959327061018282,-1.33839678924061));
#821=CARTESIAN_POINT('',(-0.463703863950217,0.963225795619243,-1.33164398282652));
#822=CARTESIAN_POINT('',(-0.445156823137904,1.03037165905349,-1.36764358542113));
#823=CARTESIAN_POINT('',(-0.508739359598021,0.823452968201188,-1.57373762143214));
#824=CARTESIAN_POINT('',(-0.429692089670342,0.828671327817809,-1.56469915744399));
#825=CARTESIAN_POINT('',(-0.412146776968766,0.897422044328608,-1.60107724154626));
#826=CARTESIAN_POINT('',(-0.48892003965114,0.755442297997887,-1.69153555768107));
#827=CARTESIAN_POINT('',(-0.40929760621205,0.761243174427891,-1.68148814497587));
#828=CARTESIAN_POINT('',(-0.392327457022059,0.830809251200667,-1.71817370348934));
#829=CARTESIAN_POINT('',(-0.444775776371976,0.619960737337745,-1.92619650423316));
#830=CARTESIAN_POINT('',(-0.364005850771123,0.62672237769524,-1.91448499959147));
#831=CARTESIAN_POINT('',(-0.348183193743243,0.697894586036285,-1.95177433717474));
#832=CARTESIAN_POINT('',(-0.420462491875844,0.552488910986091,-2.04306113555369));
#833=CARTESIAN_POINT('',(-0.339090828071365,0.559638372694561,-2.03067790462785));
#834=CARTESIAN_POINT('',(-0.323869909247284,0.631592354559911,-2.068279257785));
#835=CARTESIAN_POINT('',(-0.394836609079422,0.485172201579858,-2.15965709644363));
#836=CARTESIAN_POINT('',(-0.31307781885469,0.492983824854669,-2.14612696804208));
#837=CARTESIAN_POINT('',(-0.298244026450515,0.565291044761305,-2.18460046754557));
#838=(BOUNDED_SURFACE() B_SPLINE_SURFACE(3,2,((#736,#737,#738),(#739,#740,#741),(#742,#743,
#744),(#745,#746,#747),(#748,#749,#750),(#751,#752,#753),(#754,#755,#756),(#757,#758,#759),
(#760,#761,#762),(#763,#764,#765),(#766,#767,#768),(#769,#770,#771),(#772,#773,#774),(#775,#776,
#777),(#778,#779,#780),(#781,#782,#783),(#784,#785,#786),(#787,#788,#789),(#790,#791,#792),
(#793,#794,#795),(#796,#797,#798),(#799,#800,#801),(#802,#803,#804),(#805,#806,#807),(#808,#809,
#810),(#811,#812,#813),(#814,#815,#816),(#817,#818,#819),(#820,#821,#822),(#823,#824,#825),
(#826,#827,#828),(#829,#830,#831),(#832,#833,#834),(#835,#836,#837)),.UNSPECIFIED.,.F.,.F.,
.F.) B_SPLINE_SURFACE_WITH_KNOTS((4,2,2,2,2,2,2,2,2,2,2,2,2,2,2,2,4),(3,3),(0.,1.03130129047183,
2.06323808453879,3.12077118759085,4.17765305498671,5.17996149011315,5.6820983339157,
6.18421718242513,6.67935566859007,7.17460469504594,7.6681552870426,8.1612901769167,
8.36524298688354,8.56928208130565,8.97813846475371,9.39042752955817,9.80166162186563),(0.,1.),
.UNSPECIFIED.) GEOMETRIC_REPRESENTATION_ITEM() RATIONAL_B_SPLINE_SURFACE(((1.,0.724919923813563,
1.),(1.,0.725634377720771,1.),(1.,0.726416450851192,1.),(1.,0.728221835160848,1.),(1.,
0.729245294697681,1.),(1.,0.731668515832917,1.),(1.,0.733076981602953,1.),(1.,0.736473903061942,
1.),(1.,0.738462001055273,1.),(1.,0.743282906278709,1.),(1.,0.746066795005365,1.),(1.,
0.751359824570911,1.),(1.,0.75331282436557,1.),(1.,0.757692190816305,1.),(1.,0.760118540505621,
1.),(1.,0.765471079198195,1.),(1.,0.768389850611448,1.),(1.,0.774638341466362,1.),(1.,
0.777968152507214,1.),(1.,0.784396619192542,1.),(1.,0.78749602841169,1.),(1.,0.791967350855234,
1.),(1.,0.793340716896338,1.),(1.,0.793358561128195,1.),(1.,0.79313102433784,1.),(1.,
0.792266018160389,1.),(1.,0.791628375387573,1.),(1.,0.789211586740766,1.),(1.,0.786929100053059,
1.),(1.,0.781896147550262,1.),(1.,0.779141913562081,1.),(1.,0.773692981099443,1.),(1.,
0.770998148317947,1.),(1.,0.768581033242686,1.))) REPRESENTATION_ITEM('') SURFACE());
#839=CARTESIAN_POINT('',(-0.298244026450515,0.565291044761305,-2.18460046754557));
#840=CARTESIAN_POINT('',(-0.323869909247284,0.631592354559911,-2.068279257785));
#841=CARTESIAN_POINT('',(-0.348183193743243,0.697894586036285,-1.95177433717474));
#842=CARTESIAN_POINT('',(-0.392327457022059,0.830809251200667,-1.71817370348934));
#843=CARTESIAN_POINT('',(-0.412146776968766,0.897422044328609,-1.60107724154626));
#844=CARTESIAN_POINT('',(-0.445156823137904,1.03037165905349,-1.36764358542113));
#845=CARTESIAN_POINT('',(-0.458401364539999,1.09670616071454,-1.25130818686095));
#846=CARTESIAN_POINT('',(-0.471894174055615,1.19647796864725,-1.07696947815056));
#847=CARTESIAN_POINT('',(-0.47532919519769,1.22974836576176,-1.01893927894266));
#848=CARTESIAN_POINT('',(-0.479937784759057,1.29639869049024,-0.902948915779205));
#849=CARTESIAN_POINT('',(-0.481112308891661,1.32977856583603,-0.844988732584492));
#850=CARTESIAN_POINT('',(-0.48107711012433,1.44409900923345,-0.646991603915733));
#851=CARTESIAN_POINT('',(-0.474125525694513,1.52536823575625,-0.507102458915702));
#852=CARTESIAN_POINT('',(-0.448329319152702,1.68825541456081,-0.227797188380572));
#853=CARTESIAN_POINT('',(-0.429474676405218,1.76987360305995,-0.0883815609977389));
#854=CARTESIAN_POINT('',(-0.383684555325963,1.93319798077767,0.190486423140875));
#855=CARTESIAN_POINT('',(-0.356721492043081,2.01490350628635,0.329937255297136));
#856=CARTESIAN_POINT('',(-0.2977838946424,2.1779473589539,0.608480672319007));
#857=CARTESIAN_POINT('',(-0.265810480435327,2.25928576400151,0.74757333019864));
#858=CARTESIAN_POINT('',(-0.198271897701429,2.42277928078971,1.02748594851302));
#859=CARTESIAN_POINT('',(-0.162662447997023,2.50492974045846,1.16830261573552));
#860=CARTESIAN_POINT('',(-0.089385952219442,2.66896199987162,1.4497679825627));
#861=CARTESIAN_POINT('',(-0.0517188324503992,2.75084378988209,1.59041667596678));
#862=CARTESIAN_POINT('',(0.0631296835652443,2.99586276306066,2.01162764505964));
#863=CARTESIAN_POINT('',(0.142297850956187,3.15869521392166,2.2920060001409));
#864=CARTESIAN_POINT('',(0.307558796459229,3.49274722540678,2.86774384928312));
#865=CARTESIAN_POINT('',(0.393793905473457,3.66394071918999,3.16308783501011));
#866=CARTESIAN_POINT('',(0.567883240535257,4.00612676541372,3.7537747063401));
#867=CARTESIAN_POINT('',(0.655738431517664,4.17711912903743,4.04911747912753));
#868=CARTESIAN_POINT('',(0.830235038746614,4.51477596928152,4.63254027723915));
#869=CARTESIAN_POINT('',(0.916854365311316,4.68144502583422,4.92062306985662));
#870=CARTESIAN_POINT('',(1.09063636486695,5.0145537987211,5.49653403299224));
#871=CARTESIAN_POINT('',(1.17779867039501,5.18099359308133,5.78436225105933));
#872=CARTESIAN_POINT('',(1.26511791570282,5.34739786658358,6.07216835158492));
#873=B_SPLINE_CURVE_WITH_KNOTS('',3,(#839,#840,#841,#842,#843,#844,#845,#846,#847,#848,#849,
#850,#851,#852,#853,#854,#855,#856,#857,#858,#859,#860,#861,#862,#863,#864,#865,#866,#867,#868,
#869,#870,#871,#872),.UNSPECIFIED.,.F.,.F.,(4,2,2,2,2,2,2,2,2,2,2,2,2,2,2,2,4),(0.,
0.411234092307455,0.823523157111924,1.23237954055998,1.43641863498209,1.64037144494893,
2.13350633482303,2.62705692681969,3.12230595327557,3.6174444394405,4.11956328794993,
4.62170013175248,5.62400856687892,6.68089043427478,7.73842353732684,8.7703603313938,
9.80166162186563),.UNSPECIFIED.);
#874=EDGE_CURVE('E500',#733,#163,#873,.T.);
#875=ORIENTED_EDGE('',*,*,#874,.T.);
#876=EDGE_LOOP('',(#167,#309,#451,#593,#735,#875));
#877=FACE_BOUND('',#876,.T.);
#878=CARTESIAN_POINT('',(-0.3,0.,0.));
#879=DIRECTION('',(-1.,0.,0.));
#880=DIRECTION('',(0.,-1.,0.));
#881=AXIS2_PLACEMENT_3D('',#878,#879,#880);
#882=CIRCLE('',#881,2.25);
#883=CARTESIAN_POINT('',(-0.3,-2.25,0.));
#884=VERTEX_POINT('',#883);
#885=EDGE_CURVE('E458',#884,#884,#882,.T.);
#886=ORIENTED_EDGE('',*,*,#885,.T.);
#887=EDGE_LOOP('',(#886));
#888=FACE_BOUND('',#887,.T.);
#889=ADVANCED_FACE('F54',(#877,#888),#23,.T.);
#890=CARTESIAN_POINT('',(-1.925,0.,0.));
#891=DIRECTION('',(-1.,0.,0.));
#892=DIRECTION('',(0.,-1.,0.));
#893=AXIS2_PLACEMENT_3D('',#890,#891,#892);
#894=CYLINDRICAL_SURFACE('',#893,2.25);
#895=ORIENTED_EDGE('',*,*,#885,.F.);
#896=EDGE_LOOP('',(#895));
#897=FACE_BOUND('',#896,.T.);
#898=CARTESIAN_POINT('',(0.,0.,0.));
#899=DIRECTION('',(-1.,0.,0.));
#900=DIRECTION('',(0.,-1.,0.));
#901=AXIS2_PLACEMENT_3D('',#898,#899,#900);
#902=CIRCLE('',#901,2.25);
#903=CARTESIAN_POINT('',(0.,-2.25,0.));
#904=VERTEX_POINT('',#903);
#905=EDGE_CURVE('E460',#904,#904,#902,.T.);
#906=ORIENTED_EDGE('',*,*,#905,.T.);
#907=EDGE_LOOP('',(#906));
#908=FACE_BOUND('',#907,.T.);
#909=ADVANCED_FACE('F445',(#897,#908),#894,.T.);
#910=CARTESIAN_POINT('',(0.,1.1,0.));
#911=DIRECTION('',(-1.,0.,0.));
#912=DIRECTION('',(0.,-1.,0.));
#913=AXIS2_PLACEMENT_3D('',#910,#911,#912);
#914=PLANE('',#913);
#915=ORIENTED_EDGE('',*,*,#905,.F.);
#916=EDGE_LOOP('',(#915));
#917=FACE_BOUND('',#916,.T.);
#918=CARTESIAN_POINT('',(0.,0.,0.));
#919=DIRECTION('',(-1.,0.,0.));
#920=DIRECTION('',(0.,-1.,0.));
#921=AXIS2_PLACEMENT_3D('',#918,#919,#920);
#922=CIRCLE('',#921,1.1);
#923=CARTESIAN_POINT('',(0.,-1.1,0.));
#924=VERTEX_POINT('',#923);
#925=EDGE_CURVE('E465',#924,#924,#922,.T.);
#926=ORIENTED_EDGE('',*,*,#925,.T.);
#927=EDGE_LOOP('',(#926));
#928=FACE_BOUND('',#927,.T.);
#929=ADVANCED_FACE('F450',(#917,#928),#914,.F.);
#930=CARTESIAN_POINT('',(0.1,0.,0.));
#931=DIRECTION('',(-1.,0.,0.));
#932=DIRECTION('',(0.,-1.,0.));
#933=AXIS2_PLACEMENT_3D('',#930,#931,#932);
#934=TOROIDAL_SURFACE('',#933,1.1,0.1);
#935=ORIENTED_EDGE('',*,*,#925,.F.);
#936=EDGE_LOOP('',(#935));
#937=FACE_BOUND('',#936,.T.);
#938=CARTESIAN_POINT('',(0.100000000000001,0.,0.));
#939=DIRECTION('',(-1.,0.,0.));
#940=DIRECTION('',(0.,-1.,0.));
#941=AXIS2_PLACEMENT_3D('',#938,#939,#940);
#942=CIRCLE('',#941,1.);
#943=CARTESIAN_POINT('',(0.100000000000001,-1.,0.));
#944=VERTEX_POINT('',#943);
#945=EDGE_CURVE('E572',#944,#944,#942,.T.);
#946=ORIENTED_EDGE('',*,*,#945,.T.);
#947=EDGE_LOOP('',(#946));
#948=FACE_BOUND('',#947,.T.);
#949=ADVANCED_FACE('F578',(#937,#948),#934,.F.);
#950=CARTESIAN_POINT('',(-1.925,0.,0.));
#951=DIRECTION('',(-1.,0.,0.));
#952=DIRECTION('',(0.,-1.,0.));
#953=AXIS2_PLACEMENT_3D('',#950,#951,#952);
#954=CYLINDRICAL_SURFACE('',#953,1.);
#955=ORIENTED_EDGE('',*,*,#945,.F.);
#956=EDGE_LOOP('',(#955));
#957=FACE_BOUND('',#956,.T.);
#958=CARTESIAN_POINT('',(4.75,0.,0.));
#959=DIRECTION('',(-1.,0.,0.));
#960=DIRECTION('',(0.,-1.,0.));
#961=AXIS2_PLACEMENT_3D('',#958,#959,#960);
#962=CIRCLE('',#961,1.);
#963=CARTESIAN_POINT('',(4.75,-1.,0.));
#964=VERTEX_POINT('',#963);
#965=EDGE_CURVE('E564',#964,#964,#962,.T.);
#966=ORIENTED_EDGE('',*,*,#965,.T.);
#967=EDGE_LOOP('',(#966));
#968=FACE_BOUND('',#967,.T.);
#969=ADVANCED_FACE('F581',(#957,#968),#954,.T.);
#970=CARTESIAN_POINT('',(5.,0.,0.));
#971=DIRECTION('',(-1.,0.,0.));
#972=DIRECTION('',(0.,-1.,0.));
#973=AXIS2_PLACEMENT_3D('',#970,#971,#972);
#974=CONICAL_SURFACE('',#973,0.750000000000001,0.785398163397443);
#975=ORIENTED_EDGE('',*,*,#965,.F.);
#976=EDGE_LOOP('',(#975));
#977=FACE_BOUND('',#976,.T.);
#978=CARTESIAN_POINT('',(5.,0.,0.));
#979=DIRECTION('',(-1.,0.,0.));
#980=DIRECTION('',(0.,-1.,0.));
#981=AXIS2_PLACEMENT_3D('',#978,#979,#980);
#982=CIRCLE('',#981,0.750000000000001);
#983=CARTESIAN_POINT('',(5.,-0.750000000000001,0.));
#984=VERTEX_POINT('',#983);
#985=EDGE_CURVE('E560',#984,#984,#982,.T.);
#986=ORIENTED_EDGE('',*,*,#985,.T.);
#987=EDGE_LOOP('',(#986));
#988=FACE_BOUND('',#987,.T.);
#989=ADVANCED_FACE('F587',(#977,#988),#974,.T.);
#990=CARTESIAN_POINT('',(5.,0.,0.));
#991=DIRECTION('',(-1.,0.,0.));
#992=DIRECTION('',(0.,-1.,0.));
#993=AXIS2_PLACEMENT_3D('',#990,#991,#992);
#994=PLANE('',#993);
#995=ORIENTED_EDGE('',*,*,#985,.F.);
#996=EDGE_LOOP('',(#995));
#997=FACE_BOUND('',#996,.T.);
#998=ADVANCED_FACE('F593',(#997),#994,.F.);
#999=CARTESIAN_POINT('',(500000.,-1.73205080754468,0.));
#1000=DIRECTION('',(0.,-0.866025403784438,0.5));
#1001=DIRECTION('',(0.,-0.5,-0.866025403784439));
#1002=AXIS2_PLACEMENT_3D('',#999,#1000,#1001);
#1003=PLANE('',#1002);
#1004=DIRECTION('',(-1.,0.,0.));
#1005=VECTOR('',#1004,1.);
#1006=CARTESIAN_POINT('',(500000.,-1.73205080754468,0.));
#1007=LINE('',#1006,#1005);
#1008=CARTESIAN_POINT('',(-0.518922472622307,-1.73205080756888,0.));
#1009=VERTEX_POINT('',#1008);
#1010=CARTESIAN_POINT('',(-2.13782217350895,-1.7320508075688,1.29347825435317E-13));
#1011=VERTEX_POINT('',#1010);
#1012=EDGE_CURVE('E553',#1009,#1011,#1007,.T.);
#1013=ORIENTED_EDGE('',*,*,#1012,.F.);
#1014=CARTESIAN_POINT('',(1.16852533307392,-5.27790064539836,-6.14159207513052));
#1015=CARTESIAN_POINT('',(1.08120608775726,-5.11165453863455,-5.85364537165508));
#1016=CARTESIAN_POINT('',(0.994043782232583,-4.94538764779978,-5.56566266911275));
#1017=CARTESIAN_POINT('',(0.820261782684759,-4.61267358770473,-4.9893850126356));
#1018=CARTESIAN_POINT('',(0.733642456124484,-4.4462263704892,-4.70108997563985));
#1019=CARTESIAN_POINT('',(0.559145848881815,-4.10908774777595,-4.1171487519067));
#1020=CARTESIAN_POINT('',(0.471290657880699,-3.93839347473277,-3.82149759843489));
#1021=CARTESIAN_POINT('',(0.297201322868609,-3.59691025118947,-3.23003130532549));
#1022=CARTESIAN_POINT('',(0.210966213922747,-3.42612142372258,-2.93421637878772));
#1023=CARTESIAN_POINT('',(0.045705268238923,-3.09301622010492,-2.35726124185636));
#1024=CARTESIAN_POINT('',(-0.0334628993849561,-2.93071773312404,-2.07615201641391));
#1025=CARTESIAN_POINT('',(-0.148311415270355,-2.68664017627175,-1.65339728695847));
#1026=CARTESIAN_POINT('',(-0.185978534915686,-2.60509600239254,-1.51215863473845));
#1027=CARTESIAN_POINT('',(-0.259255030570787,-2.44177794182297,-1.22928345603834));
#1028=CARTESIAN_POINT('',(-0.29486448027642,-2.36000406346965,-1.08764694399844));
#1029=CARTESIAN_POINT('',(-0.362403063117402,-2.19725800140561,-0.805762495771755));
#1030=CARTESIAN_POINT('',(-0.394376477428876,-2.11629047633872,-0.665522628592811));
#1031=CARTESIAN_POINT('',(-0.45331407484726,-1.95386938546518,-0.384201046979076));
#1032=CARTESIAN_POINT('',(-0.4802771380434,-1.87241571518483,-0.243119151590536));
#1033=CARTESIAN_POINT('',(-0.526067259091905,-1.70919493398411,0.0395875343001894));
#1034=CARTESIAN_POINT('',(-0.54492190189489,-1.62742985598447,0.181208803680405));
#1035=CARTESIAN_POINT('',(-0.570718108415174,-1.46344989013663,0.465230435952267));
#1036=CARTESIAN_POINT('',(-0.577669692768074,-1.38123543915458,0.607630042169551));
#1037=CARTESIAN_POINT('',(-0.577704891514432,-1.26504258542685,0.808881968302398));
#1038=CARTESIAN_POINT('',(-0.57653036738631,-1.2310499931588,0.867758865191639));
#1039=CARTESIAN_POINT('',(-0.571921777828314,-1.1630885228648,0.98547158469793));
#1040=CARTESIAN_POINT('',(-0.568486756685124,-1.12911966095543,1.04430737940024));
#1041=CARTESIAN_POINT('',(-0.554993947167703,-1.02718699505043,1.22085993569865));
#1042=CARTESIAN_POINT('',(-0.541749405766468,-0.959327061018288,1.3383967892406));
#1043=CARTESIAN_POINT('',(-0.508739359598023,-0.823452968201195,1.57373762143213));
#1044=CARTESIAN_POINT('',(-0.488920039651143,-0.755442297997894,1.69153555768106));
#1045=CARTESIAN_POINT('',(-0.444775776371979,-0.619960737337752,1.92619650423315));
#1046=CARTESIAN_POINT('',(-0.420462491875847,-0.552488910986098,2.04306113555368));
#1047=CARTESIAN_POINT('',(-0.394836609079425,-0.485172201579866,2.15965709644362));
#1048=B_SPLINE_CURVE_WITH_KNOTS('',3,(#1014,#1015,#1016,#1017,#1018,#1019,#1020,#1021,#1022,
#1023,#1024,#1025,#1026,#1027,#1028,#1029,#1030,#1031,#1032,#1033,#1034,#1035,#1036,#1037,#1038,
#1039,#1040,#1041,#1042,#1043,#1044,#1045,#1046,#1047),.UNSPECIFIED.,.F.,.F.,(4,2,2,2,2,2,2,2,2,
2,2,2,2,2,2,2,4),(0.,1.03130129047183,2.06323808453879,3.12077118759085,4.17765305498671,
5.17996149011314,5.68209833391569,6.18421718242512,6.67935566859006,7.17460469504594,
7.6681552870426,8.16129017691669,8.36524298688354,8.56928208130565,8.97813846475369,
9.39042752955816,9.80166162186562),.UNSPECIFIED.);
#1049=CARTESIAN_POINT('',(-0.518922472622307,-0.866025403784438,1.5));
#1050=VERTEX_POINT('',#1049);
#1051=EDGE_CURVE('E383',#1009,#1050,#1048,.T.);
#1052=ORIENTED_EDGE('',*,*,#1051,.T.);
#1053=DIRECTION('',(-1.,0.,0.));
#1054=VECTOR('',#1053,1.);
#1055=CARTESIAN_POINT('',(500000.,-0.866025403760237,1.5));
#1056=LINE('',#1055,#1054);
#1057=CARTESIAN_POINT('',(-2.13782217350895,-0.866025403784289,1.5));
#1058=VERTEX_POINT('',#1057);
#1059=EDGE_CURVE('E552',#1050,#1058,#1056,.T.);
#1060=ORIENTED_EDGE('',*,*,#1059,.T.);
#1061=CARTESIAN_POINT('',(-2.13779123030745,-1.73216627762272,-0.000199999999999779));
#1062=CARTESIAN_POINT('',(-2.14743584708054,-1.69619286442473,0.0621077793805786));
#1063=CARTESIAN_POINT('',(-2.15619167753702,-1.66015421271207,0.124528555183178));
#1064=CARTESIAN_POINT('',(-2.17157498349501,-1.58794959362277,0.249590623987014));
#1065=CARTESIAN_POINT('',(-2.17820159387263,-1.55178358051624,0.312231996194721));
#1066=CARTESIAN_POINT('',(-2.18893948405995,-1.47954358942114,0.437355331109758));
#1067=CARTESIAN_POINT('',(-2.19306357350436,-1.44347010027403,0.499836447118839));
#1068=CARTESIAN_POINT('',(-2.19859356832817,-1.37127710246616,0.624878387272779));
#1069=CARTESIAN_POINT('',(-2.2,-1.33515760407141,0.68743919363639));
#1070=CARTESIAN_POINT('',(-2.2,-1.26291860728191,0.81256080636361));
#1071=CARTESIAN_POINT('',(-2.19859356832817,-1.22679910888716,0.875121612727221));
#1072=CARTESIAN_POINT('',(-2.19306357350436,-1.15460611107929,1.00016355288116));
#1073=CARTESIAN_POINT('',(-2.18893948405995,-1.11853262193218,1.06264466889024));
#1074=CARTESIAN_POINT('',(-2.17820159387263,-1.04629263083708,1.18776800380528));
#1075=CARTESIAN_POINT('',(-2.17157498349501,-1.01012661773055,1.25040937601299));
#1076=CARTESIAN_POINT('',(-2.15619167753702,-0.937921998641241,1.37547144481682));
#1077=CARTESIAN_POINT('',(-2.14743584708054,-0.901883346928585,1.43789222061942));
#1078=CARTESIAN_POINT('',(-2.13779123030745,-0.865909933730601,1.5002));
#1079=B_SPLINE_CURVE_WITH_KNOTS('',3,(#1061,#1062,#1063,#1064,#1065,#1066,#1067,#1068,#1069,
#1070,#1071,#1072,#1073,#1074,#1075,#1076,#1077,#1078),.UNSPECIFIED.,.F.,.F.,(4,2,2,2,2,2,2,2,
4),(0.,0.217782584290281,0.435653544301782,0.652399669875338,0.869103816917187,1.08580796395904,
1.30255408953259,1.52042504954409,1.73820763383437),.UNSPECIFIED.);
#1080=CARTESIAN_POINT('',(-2.2,-1.29903810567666,0.75));
#1081=VERTEX_POINT('',#1080);
#1082=EDGE_CURVE('E203',#1081,#1058,#1079,.T.);
#1083=ORIENTED_EDGE('',*,*,#1082,.F.);
#1084=EDGE_CURVE('E200',#1011,#1081,#1079,.T.);
#1085=ORIENTED_EDGE('',*,*,#1084,.F.);
#1086=EDGE_LOOP('',(#1013,#1052,#1060,#1083,#1085));
#1087=FACE_BOUND('',#1086,.T.);
#1088=ADVANCED_FACE('F219',(#1087),#1003,.T.);
#1089=CARTESIAN_POINT('',(500000.,-0.866025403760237,1.5));
#1090=DIRECTION('',(0.,0.,1.));
#1091=DIRECTION('',(0.,-1.,0.));
#1092=AXIS2_PLACEMENT_3D('',#1089,#1090,#1091);
#1093=PLANE('',#1092);
#1094=ORIENTED_EDGE('',*,*,#1059,.F.);
#1095=CARTESIAN_POINT('',(1.16815629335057,-7.95632023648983,1.5));
#1096=CARTESIAN_POINT('',(1.08083726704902,-7.62382649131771,1.5));
#1097=CARTESIAN_POINT('',(0.993675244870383,-7.29129116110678,1.5));
#1098=CARTESIAN_POINT('',(0.819894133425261,-6.62585972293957,1.5));
#1099=CARTESIAN_POINT('',(0.733275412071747,-6.29296351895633,1.5));
#1100=CARTESIAN_POINT('',(0.558777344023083,-5.61866988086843,1.5));
#1101=CARTESIAN_POINT('',(0.470920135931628,-5.27726669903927,1.5));
#1102=CARTESIAN_POINT('',(0.296828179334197,-4.59427079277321,1.5));
#1103=CARTESIAN_POINT('',(0.210592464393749,-4.25267831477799,1.5));
#1104=CARTESIAN_POINT('',(0.0453368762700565,-3.58645304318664,1.5));
#1105=CARTESIAN_POINT('',(-0.0338255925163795,-3.26185609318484,1.5));
#1106=CARTESIAN_POINT('',(-0.148660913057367,-2.7736997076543,1.5));
#1107=CARTESIAN_POINT('',(-0.18632288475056,-2.61061056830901,1.5));
#1108=CARTESIAN_POINT('',(-0.25958637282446,-2.28397234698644,1.5));
#1109=CARTESIAN_POINT('',(-0.2951879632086,-2.12042328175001,1.5));
#1110=CARTESIAN_POINT('',(-0.362705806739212,-1.79493051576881,1.5));
#1111=CARTESIAN_POINT('',(-0.39466645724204,-1.63299615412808,1.5));
#1112=CARTESIAN_POINT('',(-0.453571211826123,-1.30815460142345,1.5));
#1113=CARTESIAN_POINT('',(-0.480514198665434,-1.14524720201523,1.5));
#1114=CARTESIAN_POINT('',(-0.526253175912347,-0.81880561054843,1.5));
#1115=CARTESIAN_POINT('',(-0.545076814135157,-0.655275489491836,1.5));
#1116=CARTESIAN_POINT('',(-0.570800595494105,-0.327317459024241,1.5));
#1117=CARTESIAN_POINT('',(-0.577710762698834,-0.16289042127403,1.5));
#1118=CARTESIAN_POINT('',(-0.577687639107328,0.0694902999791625,1.5));
#1119=CARTESIAN_POINT('',(-0.576496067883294,0.13747391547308,1.5));
#1120=CARTESIAN_POINT('',(-0.57185435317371,0.273393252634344,1.5));
#1121=CARTESIAN_POINT('',(-0.568403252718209,0.341328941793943,1.5));
#1122=CARTESIAN_POINT('',(-0.554864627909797,0.545188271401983,1.5));
#1123=CARTESIAN_POINT('',(-0.541592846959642,0.680903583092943,1.5));
#1124=CARTESIAN_POINT('',(-0.508536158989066,0.952643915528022,1.5));
#1125=CARTESIAN_POINT('',(-0.488697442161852,1.08866195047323,1.5));
#1126=CARTESIAN_POINT('',(-0.444520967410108,1.35961767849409,1.5));
#1127=CARTESIAN_POINT('',(-0.42019489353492,1.49455724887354,1.5));
#1128=CARTESIAN_POINT('',(-0.394558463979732,1.62918706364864,1.5));
#1129=B_SPLINE_CURVE_WITH_KNOTS('',3,(#1095,#1096,#1097,#1098,#1099,#1100,#1101,#1102,#1103,
#1104,#1105,#1106,#1107,#1108,#1109,#1110,#1111,#1112,#1113,#1114,#1115,#1116,#1117,#1118,#1119,
#1120,#1121,#1122,#1123,#1124,#1125,#1126,#1127,#1128),.UNSPECIFIED.,.F.,.F.,(4,2,2,2,2,2,2,2,2,
2,2,2,2,2,2,2,4),(0.,1.03130556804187,2.06324704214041,3.12082417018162,4.17774959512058,
5.1800538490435,5.68218951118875,6.18430712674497,6.67943603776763,7.17467506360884,
7.66821413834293,8.16133774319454,8.36528677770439,8.56932224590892,8.97817344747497,
9.39046133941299,9.80169050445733),.UNSPECIFIED.);
#1130=CARTESIAN_POINT('',(-0.518922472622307,0.866025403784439,1.5));
#1131=VERTEX_POINT('',#1130);
#1132=EDGE_CURVE('E489',#1050,#1131,#1129,.T.);
#1133=ORIENTED_EDGE('',*,*,#1132,.T.);
#1134=DIRECTION('',(-1.,0.,0.));
#1135=VECTOR('',#1134,1.);
#1136=CARTESIAN_POINT('',(500000.,0.86602540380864,1.5));
#1137=LINE('',#1136,#1135);
#1138=CARTESIAN_POINT('',(-2.13782217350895,0.866025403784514,1.49999999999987));
#1139=VERTEX_POINT('',#1138);
#1140=EDGE_CURVE('E155',#1131,#1139,#1137,.T.);
#1141=ORIENTED_EDGE('',*,*,#1140,.T.);
#1142=CARTESIAN_POINT('',(-1.86623775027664,-2.29965571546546,1.5));
#1143=CARTESIAN_POINT('',(-1.88153031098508,-2.23150460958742,1.5));
#1144=CARTESIAN_POINT('',(-1.89663474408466,-2.16331125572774,1.5));
#1145=CARTESIAN_POINT('',(-1.92637231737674,-2.0268189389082,1.5));
#1146=CARTESIAN_POINT('',(-1.94100543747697,-1.95851997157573,1.5));
#1147=CARTESIAN_POINT('',(-1.98408041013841,-1.75331264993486,1.5));
#1148=CARTESIAN_POINT('',(-2.01166864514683,-1.6162224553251,1.5));
#1149=CARTESIAN_POINT('',(-2.06316551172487,-1.34247346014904,1.5));
#1150=CARTESIAN_POINT('',(-2.08710177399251,-1.20581996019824,1.5));
#1151=CARTESIAN_POINT('',(-2.12972601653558,-0.931694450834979,1.5));
#1152=CARTESIAN_POINT('',(-2.14841483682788,-0.794222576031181,1.5));
#1153=CARTESIAN_POINT('',(-2.17817768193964,-0.516813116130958,1.5));
#1154=CARTESIAN_POINT('',(-2.18916286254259,-0.376865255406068,1.5));
#1155=CARTESIAN_POINT('',(-2.19795675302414,-0.166660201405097,1.5));
#1156=CARTESIAN_POINT('',(-2.19960778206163,-0.0965568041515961,1.5));
#1157=CARTESIAN_POINT('',(-2.20026729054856,0.0436641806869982,1.5));
#1158=CARTESIAN_POINT('',(-2.19927577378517,0.11378176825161,1.5));
#1159=CARTESIAN_POINT('',(-2.19470009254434,0.254185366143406,1.5));
#1160=CARTESIAN_POINT('',(-2.19110652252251,0.324471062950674,1.5));
#1161=CARTESIAN_POINT('',(-2.18153352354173,0.46488223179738,1.5));
#1162=CARTESIAN_POINT('',(-2.1755538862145,0.535007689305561,1.5));
#1163=CARTESIAN_POINT('',(-2.15449355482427,0.745148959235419,1.5));
#1164=CARTESIAN_POINT('',(-2.13629462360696,0.884851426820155,1.5));
#1165=CARTESIAN_POINT('',(-2.09534151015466,1.15595764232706,1.5));
#1166=CARTESIAN_POINT('',(-2.0728805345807,1.28740813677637,1.5));
#1167=CARTESIAN_POINT('',(-2.02458746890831,1.54969883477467,1.5));
#1168=CARTESIAN_POINT('',(-1.99875492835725,1.68053895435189,1.5));
#1169=CARTESIAN_POINT('',(-1.94484270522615,1.94177924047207,1.5));
#1170=CARTESIAN_POINT('',(-1.91676252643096,2.07217930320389,1.5));
#1171=CARTESIAN_POINT('',(-1.85907780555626,2.33264275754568,1.5));
#1172=CARTESIAN_POINT('',(-1.82947323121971,2.46270614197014,1.5));
#1173=CARTESIAN_POINT('',(-1.76950037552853,2.72128516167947,1.5));
#1174=CARTESIAN_POINT('',(-1.73914269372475,2.84980326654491,1.5));
#1175=CARTESIAN_POINT('',(-1.67767322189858,3.10666116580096,1.5));
#1176=CARTESIAN_POINT('',(-1.64656141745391,3.23500095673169,1.5));
#1177=CARTESIAN_POINT('',(-1.58382254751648,3.49138024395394,1.5));
#1178=CARTESIAN_POINT('',(-1.55219619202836,3.61941991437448,1.5));
#1179=CARTESIAN_POINT('',(-1.48851703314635,3.87538864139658,1.5));
#1180=CARTESIAN_POINT('',(-1.45646424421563,4.00331770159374,1.5));
#1181=CARTESIAN_POINT('',(-1.42426093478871,4.13120841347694,1.5));
#1182=B_SPLINE_CURVE_WITH_KNOTS('',3,(#1142,#1143,#1144,#1145,#1146,#1147,#1148,#1149,#1150,
#1151,#1152,#1153,#1154,#1155,#1156,#1157,#1158,#1159,#1160,#1161,#1162,#1163,#1164,#1165,#1166,
#1167,#1168,#1169,#1170,#1171,#1172,#1173,#1174,#1175,#1176,#1177,#1178,#1179,#1180,#1181),
.UNSPECIFIED.,.F.,.F.,(4,2,2,2,2,2,2,2,2,2,2,2,2,2,2,2,2,2,2,4),(0.,0.209536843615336,
0.419082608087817,0.838569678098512,1.25470609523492,1.67077585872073,2.09156846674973,
2.30189193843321,2.51221510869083,2.72330234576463,2.93440802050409,3.35685386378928,
3.7568672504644,4.15693413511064,4.55708958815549,4.95725351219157,5.35341519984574,
5.74958446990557,6.14524697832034,6.54089610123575),.UNSPECIFIED.);
#1183=CARTESIAN_POINT('',(-2.2,0.,1.5));
#1184=VERTEX_POINT('',#1183);
#1185=EDGE_CURVE('E171',#1184,#1139,#1182,.T.);
#1186=ORIENTED_EDGE('',*,*,#1185,.F.);
#1187=EDGE_CURVE('E174',#1058,#1184,#1182,.T.);
#1188=ORIENTED_EDGE('',*,*,#1187,.F.);
#1189=EDGE_LOOP('',(#1094,#1133,#1141,#1186,#1188));
#1190=FACE_BOUND('',#1189,.T.);
#1191=ADVANCED_FACE('F407',(#1190),#1093,.T.);
#1192=CARTESIAN_POINT('',(500000.,-0.866025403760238,-1.5));
#1193=DIRECTION('',(0.,-0.866025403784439,-0.5));
#1194=DIRECTION('',(0.,0.5,-0.866025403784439));
#1195=AXIS2_PLACEMENT_3D('',#1192,#1193,#1194);
#1196=PLANE('',#1195);
#1197=DIRECTION('',(-1.,0.,0.));
#1198=VECTOR('',#1197,1.);
#1199=CARTESIAN_POINT('',(500000.,-0.866025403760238,-1.5));
#1200=LINE('',#1199,#1198);
#1201=CARTESIAN_POINT('',(-0.518922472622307,-0.866025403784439,-1.5));
#1202=VERTEX_POINT('',#1201);
#1203=CARTESIAN_POINT('',(-2.13782217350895,-0.866025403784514,-1.49999999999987));
#1204=VERTEX_POINT('',#1203);
#1205=EDGE_CURVE('E566',#1202,#1204,#1200,.T.);
#1206=ORIENTED_EDGE('',*,*,#1205,.F.);
#1207=CARTESIAN_POINT('',(1.16852533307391,2.67982443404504,-7.64159207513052));
#1208=CARTESIAN_POINT('',(1.08120608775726,2.51357832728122,-7.35364537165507));
#1209=CARTESIAN_POINT('',(0.994043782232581,2.34731143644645,-7.06566266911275));
#1210=CARTESIAN_POINT('',(0.820261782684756,2.0145973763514,-6.48938501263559));
#1211=CARTESIAN_POINT('',(0.733642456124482,1.84815015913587,-6.20108997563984));
#1212=CARTESIAN_POINT('',(0.559145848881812,1.51101153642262,-5.6171487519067));
#1213=CARTESIAN_POINT('',(0.471290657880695,1.34031726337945,-5.32149759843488));
#1214=CARTESIAN_POINT('',(0.297201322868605,0.998834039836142,-4.73003130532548));
#1215=CARTESIAN_POINT('',(0.210966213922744,0.828045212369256,-4.43421637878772));
#1216=CARTESIAN_POINT('',(0.04570526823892,0.494940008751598,-3.85726124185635));
#1217=CARTESIAN_POINT('',(-0.0334628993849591,0.332641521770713,-3.5761520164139));
#1218=CARTESIAN_POINT('',(-0.148311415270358,0.088563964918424,-3.15339728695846));
#1219=CARTESIAN_POINT('',(-0.185978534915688,0.00701979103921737,-3.01215863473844));
#1220=CARTESIAN_POINT('',(-0.259255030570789,-0.156298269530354,-2.72928345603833));
#1221=CARTESIAN_POINT('',(-0.294864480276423,-0.238072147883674,-2.58764694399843));
#1222=CARTESIAN_POINT('',(-0.362403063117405,-0.400818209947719,-2.30576249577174));
#1223=CARTESIAN_POINT('',(-0.394376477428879,-0.481785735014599,-2.1655226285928));
#1224=CARTESIAN_POINT('',(-0.453314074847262,-0.64420682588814,-1.88420104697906));
#1225=CARTESIAN_POINT('',(-0.480277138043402,-0.725660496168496,-1.74311915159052));
#1226=CARTESIAN_POINT('',(-0.526067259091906,-0.888881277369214,-1.4604124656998));
#1227=CARTESIAN_POINT('',(-0.544921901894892,-0.970646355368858,-1.31879119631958));
#1228=CARTESIAN_POINT('',(-0.570718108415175,-1.13462632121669,-1.03476956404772));
#1229=CARTESIAN_POINT('',(-0.577669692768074,-1.21684077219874,-0.892369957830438));
#1230=CARTESIAN_POINT('',(-0.577704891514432,-1.33303362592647,-0.69111803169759));
#1231=CARTESIAN_POINT('',(-0.57653036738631,-1.36702621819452,-0.632241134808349));
#1232=CARTESIAN_POINT('',(-0.571921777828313,-1.43498768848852,-0.514528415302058));
#1233=CARTESIAN_POINT('',(-0.568486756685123,-1.46895655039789,-0.455692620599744));
#1234=CARTESIAN_POINT('',(-0.554993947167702,-1.57088921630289,-0.279140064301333));
#1235=CARTESIAN_POINT('',(-0.541749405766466,-1.63874915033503,-0.161603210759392));
#1236=CARTESIAN_POINT('',(-0.508739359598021,-1.77462324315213,0.073737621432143));
#1237=CARTESIAN_POINT('',(-0.48892003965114,-1.84263391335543,0.191535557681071));
#1238=CARTESIAN_POINT('',(-0.444775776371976,-1.97811547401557,0.426196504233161));
#1239=CARTESIAN_POINT('',(-0.420462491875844,-2.04558730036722,0.54306113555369));
#1240=CARTESIAN_POINT('',(-0.394836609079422,-2.11290400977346,0.659657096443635));
#1241=B_SPLINE_CURVE_WITH_KNOTS('',3,(#1207,#1208,#1209,#1210,#1211,#1212,#1213,#1214,#1215,
#1216,#1217,#1218,#1219,#1220,#1221,#1222,#1223,#1224,#1225,#1226,#1227,#1228,#1229,#1230,#1231,
#1232,#1233,#1234,#1235,#1236,#1237,#1238,#1239,#1240),.UNSPECIFIED.,.F.,.F.,(4,2,2,2,2,2,2,2,2,
2,2,2,2,2,2,2,4),(0.,1.03130129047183,2.06323808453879,3.12077118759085,4.17765305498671,
5.17996149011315,5.6820983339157,6.18421718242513,6.67935566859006,7.17460469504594,
7.6681552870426,8.1612901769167,8.36524298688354,8.56928208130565,8.9781384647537,
9.39042752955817,9.80166162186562),.UNSPECIFIED.);
#1242=EDGE_CURVE('E539',#1202,#1009,#1241,.T.);
#1243=ORIENTED_EDGE('',*,*,#1242,.T.);
#1244=ORIENTED_EDGE('',*,*,#1012,.T.);
#1245=CARTESIAN_POINT('',(-2.13779123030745,-0.865909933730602,-1.5002));
#1246=CARTESIAN_POINT('',(-2.14743584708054,-0.901883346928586,-1.43789222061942));
#1247=CARTESIAN_POINT('',(-2.15619167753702,-0.937921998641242,-1.37547144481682));
#1248=CARTESIAN_POINT('',(-2.17157498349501,-1.01012661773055,-1.25040937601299));
#1249=CARTESIAN_POINT('',(-2.17820159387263,-1.04629263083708,-1.18776800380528));
#1250=CARTESIAN_POINT('',(-2.18893948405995,-1.11853262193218,-1.06264466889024));
#1251=CARTESIAN_POINT('',(-2.19306357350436,-1.15460611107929,-1.00016355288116));
#1252=CARTESIAN_POINT('',(-2.19859356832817,-1.22679910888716,-0.87512161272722));
#1253=CARTESIAN_POINT('',(-2.2,-1.26291860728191,-0.81256080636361));
#1254=CARTESIAN_POINT('',(-2.2,-1.33515760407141,-0.687439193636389));
#1255=CARTESIAN_POINT('',(-2.19859356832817,-1.37127710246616,-0.624878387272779));
#1256=CARTESIAN_POINT('',(-2.19306357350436,-1.44347010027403,-0.499836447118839));
#1257=CARTESIAN_POINT('',(-2.18893948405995,-1.47954358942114,-0.437355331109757));
#1258=CARTESIAN_POINT('',(-2.17820159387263,-1.55178358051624,-0.312231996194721));
#1259=CARTESIAN_POINT('',(-2.17157498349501,-1.58794959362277,-0.249590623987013));
#1260=CARTESIAN_POINT('',(-2.15619167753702,-1.66015421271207,-0.124528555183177));
#1261=CARTESIAN_POINT('',(-2.14743584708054,-1.69619286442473,-0.0621077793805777));
#1262=CARTESIAN_POINT('',(-2.13779123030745,-1.73216627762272,0.00020000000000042));
#1263=B_SPLINE_CURVE_WITH_KNOTS('',3,(#1245,#1246,#1247,#1248,#1249,#1250,#1251,#1252,#1253,
#1254,#1255,#1256,#1257,#1258,#1259,#1260,#1261,#1262),.UNSPECIFIED.,.F.,.F.,(4,2,2,2,2,2,2,2,
4),(0.,0.217782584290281,0.435653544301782,0.652399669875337,0.869103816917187,1.08580796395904,
1.30255408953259,1.52042504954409,1.73820763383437),.UNSPECIFIED.);
#1264=CARTESIAN_POINT('',(-2.2,-1.29903810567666,-0.75));
#1265=VERTEX_POINT('',#1264);
#1266=EDGE_CURVE('E189',#1265,#1011,#1263,.T.);
#1267=ORIENTED_EDGE('',*,*,#1266,.F.);
#1268=EDGE_CURVE('E610',#1204,#1265,#1263,.T.);
#1269=ORIENTED_EDGE('',*,*,#1268,.F.);
#1270=EDGE_LOOP('',(#1206,#1243,#1244,#1267,#1269));
#1271=FACE_BOUND('',#1270,.T.);
#1272=ADVANCED_FACE('F256',(#1271),#1196,.T.);
#1273=CARTESIAN_POINT('',(500000.,0.866025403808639,-1.5));
#1274=DIRECTION('',(0.,0.,-1.));
#1275=DIRECTION('',(0.,1.,0.));
#1276=AXIS2_PLACEMENT_3D('',#1273,#1274,#1275);
#1277=PLANE('',#1276);
#1278=DIRECTION('',(-1.,0.,0.));
#1279=VECTOR('',#1278,1.);
#1280=CARTESIAN_POINT('',(500000.,0.866025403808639,-1.5));
#1281=LINE('',#1280,#1279);
#1282=CARTESIAN_POINT('',(-0.518922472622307,0.866025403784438,-1.5));
#1283=VERTEX_POINT('',#1282);
#1284=CARTESIAN_POINT('',(-2.13782217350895,0.866025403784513,-1.49999999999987));
#1285=VERTEX_POINT('',#1284);
#1286=EDGE_CURVE('E154',#1283,#1285,#1281,.T.);
#1287=ORIENTED_EDGE('',*,*,#1286,.F.);
#1288=CARTESIAN_POINT('',(1.16889621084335,7.95913690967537,-1.5));
#1289=CARTESIAN_POINT('',(1.08157666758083,7.62664593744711,-1.5));
#1290=CARTESIAN_POINT('',(0.994413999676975,7.29411341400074,-1.5));
#1291=CARTESIAN_POINT('',(0.820630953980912,6.62868803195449,-1.5));
#1292=CARTESIAN_POINT('',(0.734010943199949,6.29579507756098,-1.5));
#1293=CARTESIAN_POINT('',(0.55951563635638,5.62153363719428,-1.5));
#1294=CARTESIAN_POINT('',(0.471662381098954,5.28015942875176,-1.5));
#1295=CARTESIAN_POINT('',(0.297575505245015,4.59722184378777,-1.5));
#1296=CARTESIAN_POINT('',(0.211340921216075,4.25565871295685,-1.5));
#1297=CARTESIAN_POINT('',(0.0460744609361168,3.58946258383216,-1.5));
#1298=CARTESIAN_POINT('',(-0.033099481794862,3.2648652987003,-1.5));
#1299=CARTESIAN_POINT('',(-0.147961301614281,2.77671102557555,-1.5));
#1300=CARTESIAN_POINT('',(-0.185633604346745,2.61362332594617,-1.5));
#1301=CARTESIAN_POINT('',(-0.258923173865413,2.2869890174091,-1.5));
#1302=CARTESIAN_POINT('',(-0.29454051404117,2.12344242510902,-1.5));
#1303=CARTESIAN_POINT('',(-0.362099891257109,1.79795065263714,-1.5));
#1304=CARTESIAN_POINT('',(-0.394086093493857,1.63601476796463,-1.5));
#1305=CARTESIAN_POINT('',(-0.453056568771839,1.31117166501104,-1.5));
#1306=CARTESIAN_POINT('',(-0.480039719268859,1.14826423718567,-1.5));
#1307=CARTESIAN_POINT('',(-0.525880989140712,0.821822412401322,-1.5));
#1308=CARTESIAN_POINT('',(-0.544766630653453,0.658292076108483,-1.5));
#1309=CARTESIAN_POINT('',(-0.570635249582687,0.330329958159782,-1.5));
#1310=CARTESIAN_POINT('',(-0.577628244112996,0.1658990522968,-1.5));
#1311=CARTESIAN_POINT('',(-0.577721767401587,-0.0664918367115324,-1.5));
#1312=CARTESIAN_POINT('',(-0.576564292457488,-0.134478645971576,-1.5));
#1313=CARTESIAN_POINT('',(-0.571988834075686,-0.270405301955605,-1.5));
#1314=CARTESIAN_POINT('',(-0.56856989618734,-0.338345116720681,-1.5));
#1315=CARTESIAN_POINT('',(-0.555122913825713,-0.542216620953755,-1.5));
#1316=CARTESIAN_POINT('',(-0.541905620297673,-0.677941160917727,-1.5));
#1317=CARTESIAN_POINT('',(-0.508942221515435,-0.949697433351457,-1.5));
#1318=CARTESIAN_POINT('',(-0.489142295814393,-1.08572219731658,-1.5));
#1319=CARTESIAN_POINT('',(-0.445030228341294,-1.35669295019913,-1.5));
#1320=CARTESIAN_POINT('',(-0.42072972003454,-1.49164080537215,-1.5));
#1321=CARTESIAN_POINT('',(-0.395114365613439,-1.62627794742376,-1.5));
#1322=B_SPLINE_CURVE_WITH_KNOTS('',3,(#1288,#1289,#1290,#1291,#1292,#1293,#1294,#1295,#1296,
#1297,#1298,#1299,#1300,#1301,#1302,#1303,#1304,#1305,#1306,#1307,#1308,#1309,#1310,#1311,#1312,
#1313,#1314,#1315,#1316,#1317,#1318,#1319,#1320,#1321),.UNSPECIFIED.,.F.,.F.,(4,2,2,2,2,2,2,2,2,
2,2,2,2,2,2,2,4),(0.,1.03129791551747,2.06323092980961,3.12072093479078,4.17756017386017,
5.17987368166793,5.68201215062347,6.18413267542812,6.67928118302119,7.17454065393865,
7.66810321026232,8.1612498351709,8.36520660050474,8.56924950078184,8.97811142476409,
9.390402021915,9.8016414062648),.UNSPECIFIED.);
#1323=EDGE_CURVE('E263',#1283,#1202,#1322,.T.);
#1324=ORIENTED_EDGE('',*,*,#1323,.T.);
#1325=ORIENTED_EDGE('',*,*,#1205,.T.);
#1326=CARTESIAN_POINT('',(-1.86623775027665,-2.2996557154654,-1.5));
#1327=CARTESIAN_POINT('',(-1.8815303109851,-2.23150460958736,-1.5));
#1328=CARTESIAN_POINT('',(-1.89663474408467,-2.16331125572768,-1.5));
#1329=CARTESIAN_POINT('',(-1.92637231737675,-2.02681893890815,-1.5));
#1330=CARTESIAN_POINT('',(-1.94100543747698,-1.95851997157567,-1.5));
#1331=CARTESIAN_POINT('',(-1.98408041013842,-1.7533126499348,-1.5));
#1332=CARTESIAN_POINT('',(-2.01166864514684,-1.61622245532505,-1.5));
#1333=CARTESIAN_POINT('',(-2.06316551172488,-1.34247346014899,-1.5));
#1334=CARTESIAN_POINT('',(-2.08710177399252,-1.20581996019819,-1.5));
#1335=CARTESIAN_POINT('',(-2.12972601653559,-0.931694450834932,-1.5));
#1336=CARTESIAN_POINT('',(-2.14841483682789,-0.794222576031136,-1.5));
#1337=CARTESIAN_POINT('',(-2.17817768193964,-0.516813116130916,-1.5));
#1338=CARTESIAN_POINT('',(-2.18916286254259,-0.376865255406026,-1.5));
#1339=CARTESIAN_POINT('',(-2.19795675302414,-0.166660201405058,-1.5));
#1340=CARTESIAN_POINT('',(-2.19960778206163,-0.0965568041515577,-1.5));
#1341=CARTESIAN_POINT('',(-2.20026729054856,0.0436641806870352,-1.5));
#1342=CARTESIAN_POINT('',(-2.19927577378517,0.113781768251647,-1.5));
#1343=CARTESIAN_POINT('',(-2.19470009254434,0.254185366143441,-1.5));
#1344=CARTESIAN_POINT('',(-2.19110652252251,0.324471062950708,-1.5));
#1345=CARTESIAN_POINT('',(-2.18153352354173,0.464882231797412,-1.5));
#1346=CARTESIAN_POINT('',(-2.1755538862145,0.535007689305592,-1.5));
#1347=CARTESIAN_POINT('',(-2.15449355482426,0.745148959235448,-1.5));
#1348=CARTESIAN_POINT('',(-2.13629462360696,0.884851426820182,-1.5));
#1349=CARTESIAN_POINT('',(-2.09534151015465,1.15595764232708,-1.5));
#1350=CARTESIAN_POINT('',(-2.0728805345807,1.28740813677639,-1.5));
#1351=CARTESIAN_POINT('',(-2.02458746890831,1.54969883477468,-1.5));
#1352=CARTESIAN_POINT('',(-1.99875492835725,1.6805389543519,-1.5));
#1353=CARTESIAN_POINT('',(-1.94484270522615,1.94177924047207,-1.5));
#1354=CARTESIAN_POINT('',(-1.91676252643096,2.07217930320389,-1.5));
#1355=CARTESIAN_POINT('',(-1.85907780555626,2.33264275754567,-1.5));
#1356=CARTESIAN_POINT('',(-1.82947323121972,2.46270614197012,-1.5));
#1357=CARTESIAN_POINT('',(-1.76950037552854,2.72128516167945,-1.5));
#1358=CARTESIAN_POINT('',(-1.73914269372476,2.84980326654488,-1.5));
#1359=CARTESIAN_POINT('',(-1.67767322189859,3.10666116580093,-1.5));
#1360=CARTESIAN_POINT('',(-1.64656141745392,3.23500095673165,-1.5));
#1361=CARTESIAN_POINT('',(-1.58382254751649,3.49138024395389,-1.5));
#1362=CARTESIAN_POINT('',(-1.55219619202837,3.61941991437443,-1.5));
#1363=CARTESIAN_POINT('',(-1.48851703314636,3.87538864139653,-1.5));
#1364=CARTESIAN_POINT('',(-1.45646424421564,4.00331770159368,-1.5));
#1365=CARTESIAN_POINT('',(-1.42426093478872,4.13120841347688,-1.5));
#1366=B_SPLINE_CURVE_WITH_KNOTS('',3,(#1326,#1327,#1328,#1329,#1330,#1331,#1332,#1333,#1334,
#1335,#1336,#1337,#1338,#1339,#1340,#1341,#1342,#1343,#1344,#1345,#1346,#1347,#1348,#1349,#1350,
#1351,#1352,#1353,#1354,#1355,#1356,#1357,#1358,#1359,#1360,#1361,#1362,#1363,#1364,#1365),
.UNSPECIFIED.,.F.,.F.,(4,2,2,2,2,2,2,2,2,2,2,2,2,2,2,2,2,2,2,4),(0.,0.209536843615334,
0.419082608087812,0.838569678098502,1.2547060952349,1.67077585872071,2.09156846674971,
2.30189193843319,2.5122151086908,2.72330234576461,2.93440802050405,3.35685386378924,
3.75686725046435,4.15693413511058,4.55708958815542,4.95725351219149,5.35341519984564,
5.74958446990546,6.14524697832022,6.54089610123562),.UNSPECIFIED.);
#1367=CARTESIAN_POINT('',(-2.2,0.,-1.5));
#1368=VERTEX_POINT('',#1367);
#1369=EDGE_CURVE('E191',#1368,#1204,#1366,.F.);
#1370=ORIENTED_EDGE('',*,*,#1369,.F.);
#1371=EDGE_CURVE('E184',#1285,#1368,#1366,.F.);
#1372=ORIENTED_EDGE('',*,*,#1371,.F.);
#1373=EDGE_LOOP('',(#1287,#1324,#1325,#1370,#1372));
#1374=FACE_BOUND('',#1373,.T.);
#1375=ADVANCED_FACE('F253',(#1374),#1277,.T.);
#1376=CARTESIAN_POINT('',(500000.,1.73205080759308,0.));
#1377=DIRECTION('',(0.,0.866025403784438,-0.5));
#1378=DIRECTION('',(0.,0.5,0.866025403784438));
#1379=AXIS2_PLACEMENT_3D('',#1376,#1377,#1378);
#1380=PLANE('',#1379);
#1381=DIRECTION('',(-1.,0.,0.));
#1382=VECTOR('',#1381,1.);
#1383=CARTESIAN_POINT('',(500000.,1.73205080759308,0.));
#1384=LINE('',#1383,#1382);
#1385=CARTESIAN_POINT('',(-0.518922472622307,1.73205080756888,0.));
#1386=VERTEX_POINT('',#1385);
#1387=CARTESIAN_POINT('',(-2.13782217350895,1.7320508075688,1.29199902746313E-13));
#1388=VERTEX_POINT('',#1387);
#1389=EDGE_CURVE('E147',#1386,#1388,#1384,.T.);
#1390=ORIENTED_EDGE('',*,*,#1389,.F.);
#1391=CARTESIAN_POINT('',(1.16852533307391,5.27790064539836,6.14159207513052));
#1392=CARTESIAN_POINT('',(1.08120608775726,5.11165453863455,5.85364537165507));
#1393=CARTESIAN_POINT('',(0.994043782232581,4.94538764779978,5.56566266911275));
#1394=CARTESIAN_POINT('',(0.820261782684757,4.61267358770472,4.98938501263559));
#1395=CARTESIAN_POINT('',(0.733642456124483,4.4462263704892,4.70108997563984));
#1396=CARTESIAN_POINT('',(0.559145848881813,4.10908774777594,4.1171487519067));
#1397=CARTESIAN_POINT('',(0.471290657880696,3.93839347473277,3.82149759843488));
#1398=CARTESIAN_POINT('',(0.297201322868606,3.59691025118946,3.23003130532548));
#1399=CARTESIAN_POINT('',(0.210966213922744,3.42612142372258,2.93421637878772));
#1400=CARTESIAN_POINT('',(0.0457052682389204,3.09301622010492,2.35726124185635));
#1401=CARTESIAN_POINT('',(-0.0334628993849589,2.93071773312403,2.0761520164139));
#1402=CARTESIAN_POINT('',(-0.148311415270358,2.68664017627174,1.65339728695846));
#1403=CARTESIAN_POINT('',(-0.185978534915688,2.60509600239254,1.51215863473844));
#1404=CARTESIAN_POINT('',(-0.259255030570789,2.44177794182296,1.22928345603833));
#1405=CARTESIAN_POINT('',(-0.294864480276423,2.36000406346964,1.08764694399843));
#1406=CARTESIAN_POINT('',(-0.362403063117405,2.1972580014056,0.805762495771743));
#1407=CARTESIAN_POINT('',(-0.394376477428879,2.11629047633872,0.6655226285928));
#1408=CARTESIAN_POINT('',(-0.453314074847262,1.95386938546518,0.384201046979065));
#1409=CARTESIAN_POINT('',(-0.480277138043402,1.87241571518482,0.243119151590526));
#1410=CARTESIAN_POINT('',(-0.526067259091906,1.7091949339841,-0.0395875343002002));
#1411=CARTESIAN_POINT('',(-0.544921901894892,1.62742985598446,-0.181208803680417));
#1412=CARTESIAN_POINT('',(-0.570718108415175,1.46344989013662,-0.465230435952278));
#1413=CARTESIAN_POINT('',(-0.577669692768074,1.38123543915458,-0.607630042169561));
#1414=CARTESIAN_POINT('',(-0.577704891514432,1.26504258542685,-0.808881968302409));
#1415=CARTESIAN_POINT('',(-0.57653036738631,1.23104999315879,-0.86775886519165));
#1416=CARTESIAN_POINT('',(-0.571921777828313,1.16308852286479,-0.98547158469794));
#1417=CARTESIAN_POINT('',(-0.568486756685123,1.12911966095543,-1.04430737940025));
#1418=CARTESIAN_POINT('',(-0.554993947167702,1.02718699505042,-1.22085993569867));
#1419=CARTESIAN_POINT('',(-0.541749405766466,0.959327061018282,-1.33839678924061));
#1420=CARTESIAN_POINT('',(-0.508739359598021,0.823452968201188,-1.57373762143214));
#1421=CARTESIAN_POINT('',(-0.48892003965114,0.755442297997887,-1.69153555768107));
#1422=CARTESIAN_POINT('',(-0.444775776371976,0.619960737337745,-1.92619650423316));
#1423=CARTESIAN_POINT('',(-0.420462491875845,0.552488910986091,-2.04306113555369));
#1424=CARTESIAN_POINT('',(-0.394836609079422,0.485172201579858,-2.15965709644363));
#1425=B_SPLINE_CURVE_WITH_KNOTS('',3,(#1391,#1392,#1393,#1394,#1395,#1396,#1397,#1398,#1399,
#1400,#1401,#1402,#1403,#1404,#1405,#1406,#1407,#1408,#1409,#1410,#1411,#1412,#1413,#1414,#1415,
#1416,#1417,#1418,#1419,#1420,#1421,#1422,#1423,#1424),.UNSPECIFIED.,.F.,.F.,(4,2,2,2,2,2,2,2,2,
2,2,2,2,2,2,2,4),(0.,1.03130129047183,2.06323808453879,3.12077118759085,4.17765305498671,
5.17996149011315,5.6820983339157,6.18421718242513,6.67935566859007,7.17460469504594,
7.6681552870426,8.1612901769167,8.36524298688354,8.56928208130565,8.97813846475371,
9.39042752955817,9.80166162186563),.UNSPECIFIED.);
#1426=EDGE_CURVE('E69',#1386,#1283,#1425,.T.);
#1427=ORIENTED_EDGE('',*,*,#1426,.T.);
#1428=ORIENTED_EDGE('',*,*,#1286,.T.);
#1429=CARTESIAN_POINT('',(-2.13779123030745,1.73216627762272,0.000200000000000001));
#1430=CARTESIAN_POINT('',(-2.14743584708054,1.69619286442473,-0.0621077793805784));
#1431=CARTESIAN_POINT('',(-2.15619167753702,1.66015421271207,-0.124528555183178));
#1432=CARTESIAN_POINT('',(-2.17157498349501,1.58794959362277,-0.249590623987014));
#1433=CARTESIAN_POINT('',(-2.17820159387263,1.55178358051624,-0.312231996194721));
#1434=CARTESIAN_POINT('',(-2.18893948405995,1.47954358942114,-0.437355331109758));
#1435=CARTESIAN_POINT('',(-2.19306357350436,1.44347010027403,-0.499836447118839));
#1436=CARTESIAN_POINT('',(-2.19859356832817,1.37127710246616,-0.624878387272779));
#1437=CARTESIAN_POINT('',(-2.2,1.33515760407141,-0.68743919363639));
#1438=CARTESIAN_POINT('',(-2.2,1.26291860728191,-0.81256080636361));
#1439=CARTESIAN_POINT('',(-2.19859356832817,1.22679910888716,-0.875121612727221));
#1440=CARTESIAN_POINT('',(-2.19306357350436,1.15460611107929,-1.00016355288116));
#1441=CARTESIAN_POINT('',(-2.18893948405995,1.11853262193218,-1.06264466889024));
#1442=CARTESIAN_POINT('',(-2.17820159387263,1.04629263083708,-1.18776800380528));
#1443=CARTESIAN_POINT('',(-2.17157498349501,1.01012661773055,-1.25040937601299));
#1444=CARTESIAN_POINT('',(-2.15619167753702,0.937921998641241,-1.37547144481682));
#1445=CARTESIAN_POINT('',(-2.14743584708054,0.901883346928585,-1.43789222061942));
#1446=CARTESIAN_POINT('',(-2.13779123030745,0.865909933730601,-1.5002));
#1447=B_SPLINE_CURVE_WITH_KNOTS('',3,(#1429,#1430,#1431,#1432,#1433,#1434,#1435,#1436,#1437,
#1438,#1439,#1440,#1441,#1442,#1443,#1444,#1445,#1446),.UNSPECIFIED.,.F.,.F.,(4,2,2,2,2,2,2,2,
4),(0.,0.217782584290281,0.435653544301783,0.652399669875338,0.869103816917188,1.08580796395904,
1.30255408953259,1.52042504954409,1.73820763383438),.UNSPECIFIED.);
#1448=CARTESIAN_POINT('',(-2.2,1.29903810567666,-0.750000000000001));
#1449=VERTEX_POINT('',#1448);
#1450=EDGE_CURVE('E170',#1449,#1285,#1447,.T.);
#1451=ORIENTED_EDGE('',*,*,#1450,.F.);
#1452=EDGE_CURVE('E161',#1388,#1449,#1447,.T.);
#1453=ORIENTED_EDGE('',*,*,#1452,.F.);
#1454=EDGE_LOOP('',(#1390,#1427,#1428,#1451,#1453));
#1455=FACE_BOUND('',#1454,.T.);
#1456=ADVANCED_FACE('F168',(#1455),#1380,.T.);
#1457=CARTESIAN_POINT('',(500000.,0.86602540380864,1.5));
#1458=DIRECTION('',(0.,0.866025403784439,0.5));
#1459=DIRECTION('',(0.,-0.5,0.866025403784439));
#1460=AXIS2_PLACEMENT_3D('',#1457,#1458,#1459);
#1461=PLANE('',#1460);
#1462=ORIENTED_EDGE('',*,*,#1140,.F.);
#1463=CARTESIAN_POINT('',(1.16852533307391,-2.67982443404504,7.64159207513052));
#1464=CARTESIAN_POINT('',(1.08120608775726,-2.51357832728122,7.35364537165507));
#1465=CARTESIAN_POINT('',(0.994043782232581,-2.34731143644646,7.06566266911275));
#1466=CARTESIAN_POINT('',(0.820261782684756,-2.0145973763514,6.48938501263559));
#1467=CARTESIAN_POINT('',(0.733642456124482,-1.84815015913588,6.20108997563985));
#1468=CARTESIAN_POINT('',(0.559145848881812,-1.51101153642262,5.6171487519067));
#1469=CARTESIAN_POINT('',(0.471290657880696,-1.34031726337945,5.32149759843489));
#1470=CARTESIAN_POINT('',(0.297201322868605,-0.998834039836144,4.73003130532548));
#1471=CARTESIAN_POINT('',(0.210966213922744,-0.828045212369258,4.43421637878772));
#1472=CARTESIAN_POINT('',(0.0457052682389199,-0.494940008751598,3.85726124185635));
#1473=CARTESIAN_POINT('',(-0.0334628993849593,-0.332641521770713,3.5761520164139));
#1474=CARTESIAN_POINT('',(-0.148311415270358,-0.0885639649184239,3.15339728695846));
#1475=CARTESIAN_POINT('',(-0.185978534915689,-0.0070197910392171,3.01215863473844));
#1476=CARTESIAN_POINT('',(-0.25925503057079,0.156298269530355,2.72928345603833));
#1477=CARTESIAN_POINT('',(-0.294864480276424,0.238072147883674,2.58764694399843));
#1478=CARTESIAN_POINT('',(-0.362403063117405,0.400818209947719,2.30576249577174));
#1479=CARTESIAN_POINT('',(-0.394376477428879,0.4817857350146,2.1655226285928));
#1480=CARTESIAN_POINT('',(-0.453314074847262,0.644206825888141,1.88420104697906));
#1481=CARTESIAN_POINT('',(-0.480277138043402,0.725660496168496,1.74311915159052));
#1482=CARTESIAN_POINT('',(-0.526067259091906,0.888881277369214,1.4604124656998));
#1483=CARTESIAN_POINT('',(-0.544921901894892,0.970646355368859,1.31879119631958));
#1484=CARTESIAN_POINT('',(-0.570718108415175,1.13462632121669,1.03476956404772));
#1485=CARTESIAN_POINT('',(-0.577669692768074,1.21684077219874,0.892369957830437));
#1486=CARTESIAN_POINT('',(-0.577704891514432,1.33303362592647,0.69111803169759));
#1487=CARTESIAN_POINT('',(-0.57653036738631,1.36702621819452,0.63224113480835));
#1488=CARTESIAN_POINT('',(-0.571921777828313,1.43498768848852,0.514528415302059));
#1489=CARTESIAN_POINT('',(-0.568486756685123,1.46895655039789,0.455692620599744));
#1490=CARTESIAN_POINT('',(-0.554993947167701,1.57088921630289,0.279140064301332));
#1491=CARTESIAN_POINT('',(-0.541749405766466,1.63874915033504,0.161603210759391));
#1492=CARTESIAN_POINT('',(-0.508739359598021,1.77462324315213,-0.0737376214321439));
#1493=CARTESIAN_POINT('',(-0.48892003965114,1.84263391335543,-0.191535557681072));
#1494=CARTESIAN_POINT('',(-0.444775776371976,1.97811547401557,-0.426196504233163));
#1495=CARTESIAN_POINT('',(-0.420462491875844,2.04558730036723,-0.543061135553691));
#1496=CARTESIAN_POINT('',(-0.394836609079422,2.11290400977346,-0.659657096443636));
#1497=B_SPLINE_CURVE_WITH_KNOTS('',3,(#1463,#1464,#1465,#1466,#1467,#1468,#1469,#1470,#1471,
#1472,#1473,#1474,#1475,#1476,#1477,#1478,#1479,#1480,#1481,#1482,#1483,#1484,#1485,#1486,#1487,
#1488,#1489,#1490,#1491,#1492,#1493,#1494,#1495,#1496),.UNSPECIFIED.,.F.,.F.,(4,2,2,2,2,2,2,2,2,
2,2,2,2,2,2,2,4),(0.,1.03130129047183,2.06323808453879,3.12077118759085,4.17765305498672,
5.17996149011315,5.6820983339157,6.18421718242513,6.67935566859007,7.17460469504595,
7.66815528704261,8.1612901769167,8.36524298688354,8.56928208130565,8.97813846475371,
9.39042752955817,9.80166162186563),.UNSPECIFIED.);
#1498=EDGE_CURVE('E12',#1131,#1386,#1497,.T.);
#1499=ORIENTED_EDGE('',*,*,#1498,.T.);
#1500=ORIENTED_EDGE('',*,*,#1389,.T.);
#1501=CARTESIAN_POINT('',(-2.13779123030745,0.865909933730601,1.5002));
#1502=CARTESIAN_POINT('',(-2.14743584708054,0.901883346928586,1.43789222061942));
#1503=CARTESIAN_POINT('',(-2.15619167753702,0.937921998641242,1.37547144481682));
#1504=CARTESIAN_POINT('',(-2.17157498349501,1.01012661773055,1.25040937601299));
#1505=CARTESIAN_POINT('',(-2.17820159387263,1.04629263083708,1.18776800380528));
#1506=CARTESIAN_POINT('',(-2.18893948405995,1.11853262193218,1.06264466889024));
#1507=CARTESIAN_POINT('',(-2.19306357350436,1.15460611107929,1.00016355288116));
#1508=CARTESIAN_POINT('',(-2.19859356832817,1.22679910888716,0.875121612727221));
#1509=CARTESIAN_POINT('',(-2.2,1.26291860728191,0.81256080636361));
#1510=CARTESIAN_POINT('',(-2.2,1.33515760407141,0.687439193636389));
#1511=CARTESIAN_POINT('',(-2.19859356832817,1.37127710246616,0.624878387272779));
#1512=CARTESIAN_POINT('',(-2.19306357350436,1.44347010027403,0.499836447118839));
#1513=CARTESIAN_POINT('',(-2.18893948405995,1.47954358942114,0.437355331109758));
#1514=CARTESIAN_POINT('',(-2.17820159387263,1.55178358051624,0.312231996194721));
#1515=CARTESIAN_POINT('',(-2.17157498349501,1.58794959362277,0.249590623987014));
#1516=CARTESIAN_POINT('',(-2.15619167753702,1.66015421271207,0.124528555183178));
#1517=CARTESIAN_POINT('',(-2.14743584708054,1.69619286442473,0.0621077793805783));
#1518=CARTESIAN_POINT('',(-2.13779123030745,1.73216627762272,-0.000199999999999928));
#1519=B_SPLINE_CURVE_WITH_KNOTS('',3,(#1501,#1502,#1503,#1504,#1505,#1506,#1507,#1508,#1509,
#1510,#1511,#1512,#1513,#1514,#1515,#1516,#1517,#1518),.UNSPECIFIED.,.F.,.F.,(4,2,2,2,2,2,2,2,
4),(0.,0.217782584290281,0.435653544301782,0.652399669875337,0.869103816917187,1.08580796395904,
1.30255408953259,1.52042504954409,1.73820763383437),.UNSPECIFIED.);
#1520=CARTESIAN_POINT('',(-2.2,1.29903810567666,0.75));
#1521=VERTEX_POINT('',#1520);
#1522=EDGE_CURVE('E151',#1521,#1388,#1519,.T.);
#1523=ORIENTED_EDGE('',*,*,#1522,.F.);
#1524=EDGE_CURVE('E165',#1139,#1521,#1519,.T.);
#1525=ORIENTED_EDGE('',*,*,#1524,.F.);
#1526=EDGE_LOOP('',(#1462,#1499,#1500,#1523,#1525));
#1527=FACE_BOUND('',#1526,.T.);
#1528=ADVANCED_FACE('F149',(#1527),#1461,.T.);
#1529=CARTESIAN_POINT('',(-2.40096189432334,0.,0.));
#1530=DIRECTION('',(1.,0.,0.));
#1531=DIRECTION('',(0.,0.,-1.));
#1532=AXIS2_PLACEMENT_3D('',#1529,#1530,#1531);
#1533=CONICAL_SURFACE('',#1532,0.75,1.30899693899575);
#1534=ORIENTED_EDGE('',*,*,#1522,.T.);
#1535=ORIENTED_EDGE('',*,*,#1452,.T.);
#1536=CARTESIAN_POINT('',(-2.2,0.,0.));
#1537=DIRECTION('',(1.,0.,0.));
#1538=DIRECTION('',(0.,1.,0.));
#1539=AXIS2_PLACEMENT_3D('',#1536,#1537,#1538);
#1540=CIRCLE('',#1539,1.5);
#1541=EDGE_CURVE('E164',#1521,#1449,#1540,.F.);
#1542=ORIENTED_EDGE('',*,*,#1541,.F.);
#1543=EDGE_LOOP('',(#1534,#1535,#1542));
#1544=FACE_BOUND('',#1543,.T.);
#1545=ADVANCED_FACE('F160',(#1544),#1533,.T.);
#1546=ORIENTED_EDGE('',*,*,#1185,.T.);
#1547=ORIENTED_EDGE('',*,*,#1524,.T.);
#1548=EDGE_CURVE('E199',#1184,#1521,#1540,.F.);
#1549=ORIENTED_EDGE('',*,*,#1548,.F.);
#1550=EDGE_LOOP('',(#1546,#1547,#1549));
#1551=FACE_BOUND('',#1550,.T.);
#1552=ADVANCED_FACE('F618',(#1551),#1533,.T.);
#1553=ORIENTED_EDGE('',*,*,#1371,.T.);
#1554=EDGE_CURVE('E185',#1449,#1368,#1540,.F.);
#1555=ORIENTED_EDGE('',*,*,#1554,.F.);
#1556=ORIENTED_EDGE('',*,*,#1450,.T.);
#1557=EDGE_LOOP('',(#1553,#1555,#1556));
#1558=FACE_BOUND('',#1557,.T.);
#1559=ADVANCED_FACE('F227',(#1558),#1533,.T.);
#1560=ORIENTED_EDGE('',*,*,#1369,.T.);
#1561=ORIENTED_EDGE('',*,*,#1268,.T.);
#1562=EDGE_CURVE('E193',#1368,#1265,#1540,.F.);
#1563=ORIENTED_EDGE('',*,*,#1562,.F.);
#1564=EDGE_LOOP('',(#1560,#1561,#1563));
#1565=FACE_BOUND('',#1564,.T.);
#1566=ADVANCED_FACE('F222',(#1565),#1533,.T.);
#1567=ORIENTED_EDGE('',*,*,#1266,.T.);
#1568=ORIENTED_EDGE('',*,*,#1084,.T.);
#1569=EDGE_CURVE('E197',#1265,#1081,#1540,.F.);
#1570=ORIENTED_EDGE('',*,*,#1569,.F.);
#1571=EDGE_LOOP('',(#1567,#1568,#1570));
#1572=FACE_BOUND('',#1571,.T.);
#1573=ADVANCED_FACE('F226',(#1572),#1533,.T.);
#1574=ORIENTED_EDGE('',*,*,#1082,.T.);
#1575=ORIENTED_EDGE('',*,*,#1187,.T.);
#1576=EDGE_CURVE('E201',#1081,#1184,#1540,.F.);
#1577=ORIENTED_EDGE('',*,*,#1576,.F.);
#1578=EDGE_LOOP('',(#1574,#1575,#1577));
#1579=FACE_BOUND('',#1578,.T.);
#1580=ADVANCED_FACE('F485',(#1579),#1533,.T.);
#1581=CARTESIAN_POINT('',(-1.925,1.2,0.));
#1582=DIRECTION('',(1.,0.,0.));
#1583=DIRECTION('',(0.,1.,0.));
#1584=AXIS2_PLACEMENT_3D('',#1581,#1582,#1583);
#1585=PLANE('',#1584);
#1586=CARTESIAN_POINT('',(-1.925,0.,0.));
#1587=DIRECTION('',(-1.,0.,0.));
#1588=DIRECTION('',(0.,-1.,0.));
#1589=AXIS2_PLACEMENT_3D('',#1586,#1587,#1588);
#1590=CIRCLE('',#1589,1.2);
#1591=CARTESIAN_POINT('',(-1.925,-1.2,0.));
#1592=VERTEX_POINT('',#1591);
#1593=EDGE_CURVE('E166',#1592,#1592,#1590,.T.);
#1594=ORIENTED_EDGE('',*,*,#1593,.T.);
#1595=EDGE_LOOP('',(#1594));
#1596=FACE_BOUND('',#1595,.T.);
#1597=ADVANCED_FACE('F471',(#1596),#1585,.F.);
#1598=CARTESIAN_POINT('',(-1.925,0.,0.));
#1599=DIRECTION('',(-1.,0.,0.));
#1600=DIRECTION('',(0.,-1.,0.));
#1601=AXIS2_PLACEMENT_3D('',#1598,#1599,#1600);
#1602=CYLINDRICAL_SURFACE('',#1601,1.2);
#1603=ORIENTED_EDGE('',*,*,#1593,.F.);
#1604=EDGE_LOOP('',(#1603));
#1605=FACE_BOUND('',#1604,.T.);
#1606=CARTESIAN_POINT('',(-2.2,0.,0.));
#1607=DIRECTION('',(-1.,0.,0.));
#1608=DIRECTION('',(0.,-1.,0.));
#1609=AXIS2_PLACEMENT_3D('',#1606,#1607,#1608);
#1610=CIRCLE('',#1609,1.2);
#1611=CARTESIAN_POINT('',(-2.2,-1.2,0.));
#1612=VERTEX_POINT('',#1611);
#1613=EDGE_CURVE('E459',#1612,#1612,#1610,.T.);
#1614=ORIENTED_EDGE('',*,*,#1613,.T.);
#1615=EDGE_LOOP('',(#1614));
#1616=FACE_BOUND('',#1615,.T.);
#1617=ADVANCED_FACE('F473',(#1605,#1616),#1602,.F.);
#1618=CARTESIAN_POINT('',(-2.2,1.5,0.));
#1619=DIRECTION('',(1.,0.,0.));
#1620=DIRECTION('',(0.,1.,0.));
#1621=AXIS2_PLACEMENT_3D('',#1618,#1619,#1620);
#1622=PLANE('',#1621);
#1623=ORIENTED_EDGE('',*,*,#1613,.F.);
#1624=EDGE_LOOP('',(#1623));
#1625=FACE_BOUND('',#1624,.T.);
#1626=ORIENTED_EDGE('',*,*,#1541,.T.);
#1627=ORIENTED_EDGE('',*,*,#1554,.T.);
#1628=ORIENTED_EDGE('',*,*,#1562,.T.);
#1629=ORIENTED_EDGE('',*,*,#1569,.T.);
#1630=ORIENTED_EDGE('',*,*,#1576,.T.);
#1631=ORIENTED_EDGE('',*,*,#1548,.T.);
#1632=EDGE_LOOP('',(#1626,#1627,#1628,#1629,#1630,#1631));
#1633=FACE_BOUND('',#1632,.T.);
#1634=ADVANCED_FACE('F277',(#1625,#1633),#1622,.F.);
#1635=CARTESIAN_POINT('',(-0.518922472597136,0.866025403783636,-1.49999999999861));
#1636=CARTESIAN_POINT('',(-0.513508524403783,0.866024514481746,-1.49999480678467));
#1637=CARTESIAN_POINT('',(-0.508105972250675,0.866276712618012,-1.50043260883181));
#1638=CARTESIAN_POINT('',(-0.497499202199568,0.867244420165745,-1.50211151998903));
#1639=CARTESIAN_POINT('',(-0.492294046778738,0.867957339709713,-1.50334813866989));
#1640=CARTESIAN_POINT('',(-0.482205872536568,0.869802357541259,-1.50653995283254));
#1641=CARTESIAN_POINT('',(-0.477322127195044,0.870933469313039,-1.50849345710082));
#1642=CARTESIAN_POINT('',(-0.467950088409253,0.873547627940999,-1.5130241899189));
#1643=CARTESIAN_POINT('',(-0.463462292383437,0.875031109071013,-1.51560218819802));
#1644=CARTESIAN_POINT('',(-0.454566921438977,0.878467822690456,-1.5215466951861));
#1645=CARTESIAN_POINT('',(-0.450205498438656,0.88045188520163,-1.52496419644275));
#1646=CARTESIAN_POINT('',(-0.442097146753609,0.884694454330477,-1.53232053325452));
#1647=CARTESIAN_POINT('',(-0.438350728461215,0.886953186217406,-1.53625979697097));
#1648=CARTESIAN_POINT('',(-0.431027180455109,0.892092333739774,-1.54513570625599));
#1649=CARTESIAN_POINT('',(-0.427554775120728,0.895015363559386,-1.55013398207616));
#1650=CARTESIAN_POINT('',(-0.421519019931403,0.901026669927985,-1.56054836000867));
#1651=CARTESIAN_POINT('',(-0.418954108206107,0.904114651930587,-1.56596372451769));
#1652=CARTESIAN_POINT('',(-0.41632813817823,0.908128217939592,-1.57292649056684));
#1653=CARTESIAN_POINT('',(-0.415819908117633,0.908960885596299,-1.57436709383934));
#1654=CARTESIAN_POINT('',(-0.415150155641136,0.910137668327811,-1.57640441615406));
#1655=CARTESIAN_POINT('',(-0.414961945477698,0.910478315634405,-1.57699432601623));
#1656=CARTESIAN_POINT('',(-0.414778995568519,0.910819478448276,-1.5775856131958));
#1657=B_SPLINE_CURVE_WITH_KNOTS('',3,(#1635,#1636,#1637,#1638,#1639,#1640,#1641,#1642,#1643,
#1644,#1645,#1646,#1647,#1648,#1649,#1650,#1651,#1652,#1653,#1654,#1655,#1656),.UNSPECIFIED.,
.F.,.F.,(4,2,2,2,2,2,2,2,2,2,4),(0.,0.0162017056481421,0.0323131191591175,0.0483867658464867,
0.0644803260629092,0.0820684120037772,0.0996710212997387,0.119845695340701,0.139985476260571,
0.145204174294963,0.147324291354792),.UNSPECIFIED.);
#1658=EDGE_CURVE('E177',#733,#1283,#1657,.F.);
#1659=ORIENTED_EDGE('',*,*,#1658,.F.);
#1660=ORIENTED_EDGE('',*,*,#734,.F.);
#1661=CARTESIAN_POINT('',(-0.518922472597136,-0.866025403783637,-1.49999999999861));
#1662=CARTESIAN_POINT('',(-0.513508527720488,-0.866021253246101,-1.49999670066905));
#1663=CARTESIAN_POINT('',(-0.508105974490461,-0.866274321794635,-1.50043399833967));
#1664=CARTESIAN_POINT('',(-0.497499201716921,-0.867244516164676,-1.50211146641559));
#1665=CARTESIAN_POINT('',(-0.492294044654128,-0.867959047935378,-1.50334714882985));
#1666=CARTESIAN_POINT('',(-0.482205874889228,-0.869800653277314,-1.50654094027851));
#1667=CARTESIAN_POINT('',(-0.477322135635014,-0.870926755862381,-1.50849734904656));
#1668=CARTESIAN_POINT('',(-0.467950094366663,-0.873543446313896,-1.51302661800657));
#1669=CARTESIAN_POINT('',(-0.463462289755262,-0.875034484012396,-1.5156002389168));
#1670=CARTESIAN_POINT('',(-0.454566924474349,-0.878464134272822,-1.52154882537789));
#1671=CARTESIAN_POINT('',(-0.450205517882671,-0.880431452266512,-1.5249760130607));
#1672=CARTESIAN_POINT('',(-0.442097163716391,-0.884681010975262,-1.53232831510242));
#1673=CARTESIAN_POINT('',(-0.438350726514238,-0.886963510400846,-1.53625383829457));
#1674=CARTESIAN_POINT('',(-0.43102718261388,-0.892080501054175,-1.54514253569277));
#1675=CARTESIAN_POINT('',(-0.427554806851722,-0.894946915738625,-1.55017351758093));
#1676=CARTESIAN_POINT('',(-0.421519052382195,-0.900960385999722,-1.5605866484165));
#1677=CARTESIAN_POINT('',(-0.418954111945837,-0.904106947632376,-1.56596817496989));
#1678=CARTESIAN_POINT('',(-0.416328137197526,-0.908130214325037,-1.5729253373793));
#1679=CARTESIAN_POINT('',(-0.415819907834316,-0.908961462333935,-1.57436676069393));
#1680=CARTESIAN_POINT('',(-0.415150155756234,-0.910137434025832,-1.57640455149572));
#1681=CARTESIAN_POINT('',(-0.414961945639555,-0.910477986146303,-1.57699451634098));
#1682=CARTESIAN_POINT('',(-0.414778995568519,-0.910819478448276,-1.5775856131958));
#1683=B_SPLINE_CURVE_WITH_KNOTS('',3,(#1661,#1662,#1663,#1664,#1665,#1666,#1667,#1668,#1669,
#1670,#1671,#1672,#1673,#1674,#1675,#1676,#1677,#1678,#1679,#1680,#1681,#1682),.UNSPECIFIED.,
.F.,.F.,(4,2,2,2,2,2,2,2,2,2,4),(0.,0.0162017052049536,0.0323131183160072,0.0483867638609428,
0.064480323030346,0.0820684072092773,0.0996710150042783,0.119845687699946,0.139985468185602,
0.145204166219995,0.147324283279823),.UNSPECIFIED.);
#1684=EDGE_CURVE('E58',#1202,#591,#1683,.T.);
#1685=ORIENTED_EDGE('',*,*,#1684,.F.);
#1686=ORIENTED_EDGE('',*,*,#1323,.F.);
#1687=EDGE_LOOP('',(#1659,#1660,#1685,#1686));
#1688=FACE_BOUND('',#1687,.T.);
#1689=ADVANCED_FACE('F271',(#1688),#696,.F.);
#1690=ORIENTED_EDGE('',*,*,#1684,.T.);
#1691=ORIENTED_EDGE('',*,*,#592,.F.);
#1692=CARTESIAN_POINT('',(-0.518922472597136,-1.73205080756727,0.));
#1693=CARTESIAN_POINT('',(-0.51350851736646,-1.73204584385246,-1.87464339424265E-06));
#1694=CARTESIAN_POINT('',(-0.508105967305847,-1.73255109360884,-1.37416848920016E-06));
#1695=CARTESIAN_POINT('',(-0.497499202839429,-1.73448894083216,5.54598583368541E-08));
#1696=CARTESIAN_POINT('',(-0.492294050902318,-1.73591635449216,9.82208728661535E-07));
#1697=CARTESIAN_POINT('',(-0.482205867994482,-1.7396030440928,-9.79906412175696E-07));
#1698=CARTESIAN_POINT('',(-0.477322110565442,-1.74186036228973,-3.85983164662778E-06));
#1699=CARTESIAN_POINT('',(-0.467950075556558,-1.74709117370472,-2.40367474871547E-06));
#1700=CARTESIAN_POINT('',(-0.463462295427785,-1.75006555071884,1.94135162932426E-06));
#1701=CARTESIAN_POINT('',(-0.454566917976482,-1.75693200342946,-2.12163497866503E-06));
#1702=CARTESIAN_POINT('',(-0.450205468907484,-1.76088365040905,-1.17514281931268E-05));
#1703=CARTESIAN_POINT('',(-0.442097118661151,-1.76937570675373,-7.73030833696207E-06));
#1704=CARTESIAN_POINT('',(-0.438350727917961,-1.77391659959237,5.93983524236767E-06));
#1705=CARTESIAN_POINT('',(-0.431027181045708,-1.78417294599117,-6.80775439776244E-06));
#1706=CARTESIAN_POINT('',(-0.427554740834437,-1.78996307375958,-3.93749291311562E-05));
#1707=CARTESIAN_POINT('',(-0.42151898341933,-1.80198783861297,-3.8129650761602E-05));
#1708=CARTESIAN_POINT('',(-0.418954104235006,-1.80822168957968,-4.43190668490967E-06));
#1709=CARTESIAN_POINT('',(-0.416328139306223,-1.81625840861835,1.14841261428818E-06));
#1710=CARTESIAN_POINT('',(-0.4158199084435,-1.81792234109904,3.31765982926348E-07));
#1711=CARTESIAN_POINT('',(-0.415150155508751,-1.82027510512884,-1.3478125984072E-07));
#1712=CARTESIAN_POINT('',(-0.414961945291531,-1.82095630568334,-1.8953669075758E-07));
#1713=CARTESIAN_POINT('',(-0.414778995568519,-1.82163895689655,0.));
#1714=B_SPLINE_CURVE_WITH_KNOTS('',3,(#1692,#1693,#1694,#1695,#1696,#1697,#1698,#1699,#1700,
#1701,#1702,#1703,#1704,#1705,#1706,#1707,#1708,#1709,#1710,#1711,#1712,#1713),.UNSPECIFIED.,
.F.,.F.,(4,2,2,2,2,2,2,2,2,2,4),(0.,0.0162017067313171,0.0323131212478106,0.0483867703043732,
0.0644803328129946,0.0820684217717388,0.0996710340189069,0.119845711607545,0.139985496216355,
0.145204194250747,0.147324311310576),.UNSPECIFIED.);
#1715=EDGE_CURVE('E300',#1009,#449,#1714,.T.);
#1716=ORIENTED_EDGE('',*,*,#1715,.F.);
#1717=ORIENTED_EDGE('',*,*,#1242,.F.);
#1718=EDGE_LOOP('',(#1690,#1691,#1716,#1717));
#1719=FACE_BOUND('',#1718,.T.);
#1720=ADVANCED_FACE('F276',(#1719),#554,.F.);
#1721=ORIENTED_EDGE('',*,*,#1658,.T.);
#1722=ORIENTED_EDGE('',*,*,#1426,.F.);
#1723=CARTESIAN_POINT('',(-0.518922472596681,1.73205080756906,-3.08918533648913E-12));
#1724=CARTESIAN_POINT('',(-0.513508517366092,1.73204584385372,1.87464189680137E-06));
#1725=CARTESIAN_POINT('',(-0.508105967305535,1.73255109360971,1.37416775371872E-06));
#1726=CARTESIAN_POINT('',(-0.497499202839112,1.7344889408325,-5.54598573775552E-08));
#1727=CARTESIAN_POINT('',(-0.492294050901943,1.73591635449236,-9.82208748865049E-07));
#1728=CARTESIAN_POINT('',(-0.482205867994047,1.7396030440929,9.79906432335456E-07));
#1729=CARTESIAN_POINT('',(-0.477322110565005,1.74186036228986,3.85983172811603E-06));
#1730=CARTESIAN_POINT('',(-0.467950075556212,1.74709117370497,2.40367461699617E-06));
#1731=CARTESIAN_POINT('',(-0.463462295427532,1.75006555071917,-1.94135203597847E-06));
#1732=CARTESIAN_POINT('',(-0.454566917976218,1.75693200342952,2.12163542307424E-06));
#1733=CARTESIAN_POINT('',(-0.450205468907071,1.76088365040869,1.17514298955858E-05));
#1734=CARTESIAN_POINT('',(-0.442097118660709,1.76937570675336,7.73031006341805E-06));
#1735=CARTESIAN_POINT('',(-0.438350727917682,1.77391659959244,-5.93983475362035E-06));
#1736=CARTESIAN_POINT('',(-0.431027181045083,1.7841729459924,6.80775383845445E-06));
#1737=CARTESIAN_POINT('',(-0.427554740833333,1.78996307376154,3.93749290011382E-05));
#1738=CARTESIAN_POINT('',(-0.421518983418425,1.80198783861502,3.81296509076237E-05));
#1739=CARTESIAN_POINT('',(-0.418954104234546,1.80822168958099,4.43190669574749E-06));
#1740=CARTESIAN_POINT('',(-0.416328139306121,1.81625840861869,-1.14841261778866E-06));
#1741=CARTESIAN_POINT('',(-0.415819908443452,1.81792234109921,-3.31765980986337E-07));
#1742=CARTESIAN_POINT('',(-0.415150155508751,1.82027510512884,1.34781262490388E-07));
#1743=CARTESIAN_POINT('',(-0.41496194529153,1.82095630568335,1.8953669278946E-07));
#1744=CARTESIAN_POINT('',(-0.414778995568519,1.82163895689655,0.));
#1745=B_SPLINE_CURVE_WITH_KNOTS('',3,(#1723,#1724,#1725,#1726,#1727,#1728,#1729,#1730,#1731,
#1732,#1733,#1734,#1735,#1736,#1737,#1738,#1739,#1740,#1741,#1742,#1743,#1744),.UNSPECIFIED.,
.F.,.F.,(4,2,2,2,2,2,2,2,2,2,4),(0.,0.0162017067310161,0.0323131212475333,0.048386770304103,
0.0644803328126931,0.0820684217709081,0.0996710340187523,0.119845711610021,0.139985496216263,
0.145204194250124,0.147324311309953),.UNSPECIFIED.);
#1746=EDGE_CURVE('E327',#163,#1386,#1745,.F.);
#1747=ORIENTED_EDGE('',*,*,#1746,.F.);
#1748=ORIENTED_EDGE('',*,*,#874,.F.);
#1749=EDGE_LOOP('',(#1721,#1722,#1747,#1748));
#1750=FACE_BOUND('',#1749,.T.);
#1751=ADVANCED_FACE('F307',(#1750),#838,.F.);
#1752=ORIENTED_EDGE('',*,*,#1715,.T.);
#1753=ORIENTED_EDGE('',*,*,#450,.F.);
#1754=CARTESIAN_POINT('',(-0.518922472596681,-0.866025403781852,1.5000000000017));
#1755=CARTESIAN_POINT('',(-0.513508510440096,-0.86602457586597,1.49999472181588));
#1756=CARTESIAN_POINT('',(-0.508105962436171,-0.866276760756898,1.50043253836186));
#1757=CARTESIAN_POINT('',(-0.497499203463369,-0.867244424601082,1.50211150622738));
#1758=CARTESIAN_POINT('',(-0.492294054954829,-0.867957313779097,1.50334816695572));
#1759=CARTESIAN_POINT('',(-0.482205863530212,-0.869802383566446,1.50653992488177));
#1760=CARTESIAN_POINT('',(-0.477322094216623,-0.870933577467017,1.50849333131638));
#1761=CARTESIAN_POINT('',(-0.467950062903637,-0.873547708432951,1.51302408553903));
#1762=CARTESIAN_POINT('',(-0.463462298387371,-0.87503107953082,1.51560220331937));
#1763=CARTESIAN_POINT('',(-0.454566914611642,-0.878467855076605,1.52154667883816));
#1764=CARTESIAN_POINT('',(-0.450205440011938,-0.880452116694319,1.52496400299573));
#1765=CARTESIAN_POINT('',(-0.442097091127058,-0.884694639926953,1.5323203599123));
#1766=CARTESIAN_POINT('',(-0.438350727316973,-0.886953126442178,1.53625982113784));
#1767=CARTESIAN_POINT('',(-0.431027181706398,-0.892092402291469,1.54513567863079));
#1768=CARTESIAN_POINT('',(-0.427554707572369,-0.895015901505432,1.55013363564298));
#1769=CARTESIAN_POINT('',(-0.421518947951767,-0.901027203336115,1.56054800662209));
#1770=CARTESIAN_POINT('',(-0.41895410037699,-0.904114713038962,1.56596368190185));
#1771=CARTESIAN_POINT('',(-0.416328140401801,-0.908128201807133,1.57292650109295));
#1772=CARTESIAN_POINT('',(-0.415819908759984,-0.908960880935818,1.5743670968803));
#1773=CARTESIAN_POINT('',(-0.415150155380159,-0.910137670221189,1.57640441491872));
#1774=CARTESIAN_POINT('',(-0.414961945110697,-0.910478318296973,1.57699432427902));
#1775=CARTESIAN_POINT('',(-0.414778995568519,-0.910819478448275,1.5775856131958));
#1776=B_SPLINE_CURVE_WITH_KNOTS('',3,(#1754,#1755,#1756,#1757,#1758,#1759,#1760,#1761,#1762,
#1763,#1764,#1765,#1766,#1767,#1768,#1769,#1770,#1771,#1772,#1773,#1774,#1775),.UNSPECIFIED.,
.F.,.F.,(4,2,2,2,2,2,2,2,2,2,4),(0.,0.0162017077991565,0.032313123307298,0.0483867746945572,
0.0644803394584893,0.0820684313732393,0.0996710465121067,0.119845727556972,0.139985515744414,
0.145204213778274,0.147324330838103),.UNSPECIFIED.);
#1777=EDGE_CURVE('E421',#1050,#307,#1776,.T.);
#1778=ORIENTED_EDGE('',*,*,#1777,.F.);
#1779=ORIENTED_EDGE('',*,*,#1051,.F.);
#1780=EDGE_LOOP('',(#1752,#1753,#1778,#1779));
#1781=FACE_BOUND('',#1780,.T.);
#1782=ADVANCED_FACE('F313',(#1781),#412,.F.);
#1783=ORIENTED_EDGE('',*,*,#1746,.T.);
#1784=ORIENTED_EDGE('',*,*,#1498,.F.);
#1785=CARTESIAN_POINT('',(-0.518922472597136,0.866025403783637,1.49999999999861));
#1786=CARTESIAN_POINT('',(-0.513508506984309,0.866021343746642,1.49999657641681));
#1787=CARTESIAN_POINT('',(-0.508105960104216,0.866274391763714,1.50043389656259));
#1788=CARTESIAN_POINT('',(-0.49749920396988,0.867244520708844,1.50211144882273));
#1789=CARTESIAN_POINT('',(-0.492294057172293,0.867959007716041,1.50334719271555));
#1790=CARTESIAN_POINT('',(-0.482205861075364,0.869800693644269,1.50654089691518));
#1791=CARTESIAN_POINT('',(-0.477322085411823,0.870926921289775,1.50849715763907));
#1792=CARTESIAN_POINT('',(-0.467950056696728,0.87354356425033,1.51302646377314));
#1793=CARTESIAN_POINT('',(-0.463462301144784,0.875034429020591,1.51560027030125));
#1794=CARTESIAN_POINT('',(-0.454566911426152,0.878464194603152,1.52154879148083));
#1795=CARTESIAN_POINT('',(-0.450205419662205,0.88043184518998,1.52497568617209));
#1796=CARTESIAN_POINT('',(-0.442097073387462,0.884681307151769,1.53232803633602));
#1797=CARTESIAN_POINT('',(-0.438350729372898,0.886963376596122,1.53625390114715));
#1798=CARTESIAN_POINT('',(-0.431027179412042,0.892080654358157,1.54514246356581));
#1799=CARTESIAN_POINT('',(-0.427554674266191,0.894947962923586,1.55017284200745));
#1800=CARTESIAN_POINT('',(-0.421518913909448,0.900961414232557,1.56058596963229));
#1801=CARTESIAN_POINT('',(-0.418954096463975,0.904107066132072,1.56596809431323));
#1802=CARTESIAN_POINT('',(-0.416328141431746,0.908130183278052,1.57292535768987));
#1803=CARTESIAN_POINT('',(-0.415819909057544,0.908961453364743,1.57436676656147));
#1804=CARTESIAN_POINT('',(-0.415150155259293,0.910137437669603,1.57640454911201));
#1805=CARTESIAN_POINT('',(-0.41496194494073,0.91047799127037,1.57699451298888));
#1806=CARTESIAN_POINT('',(-0.414778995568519,0.910819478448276,1.5775856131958));
#1807=B_SPLINE_CURVE_WITH_KNOTS('',3,(#1785,#1786,#1787,#1788,#1789,#1790,#1791,#1792,#1793,
#1794,#1795,#1796,#1797,#1798,#1799,#1800,#1801,#1802,#1803,#1804,#1805,#1806),.UNSPECIFIED.,
.F.,.F.,(4,2,2,2,2,2,2,2,2,2,4),(0.,0.0162017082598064,0.0323131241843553,0.0483867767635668,
0.0644803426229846,0.0820684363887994,0.0996710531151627,0.119845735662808,0.139985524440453,
0.145204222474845,0.147324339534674),.UNSPECIFIED.);
#1808=EDGE_CURVE('E515',#165,#1131,#1807,.F.);
#1809=ORIENTED_EDGE('',*,*,#1808,.F.);
#1810=ORIENTED_EDGE('',*,*,#166,.F.);
#1811=EDGE_LOOP('',(#1783,#1784,#1809,#1810));
#1812=FACE_BOUND('',#1811,.T.);
#1813=ADVANCED_FACE('F398',(#1812),#126,.F.);
#1814=ORIENTED_EDGE('',*,*,#1777,.T.);
#1815=ORIENTED_EDGE('',*,*,#308,.F.);
#1816=ORIENTED_EDGE('',*,*,#1808,.T.);
#1817=ORIENTED_EDGE('',*,*,#1132,.F.);
#1818=EDGE_LOOP('',(#1814,#1815,#1816,#1817));
#1819=FACE_BOUND('',#1818,.T.);
#1820=ADVANCED_FACE('F392',(#1819),#270,.F.);
#1821=CLOSED_SHELL('',(#889,#909,#929,#949,#969,#989,#998,#1088,#1191,#1272,#1375,#1456,#1528,
#1545,#1552,#1559,#1566,#1573,#1580,#1597,#1617,#1634,#1689,#1720,#1751,#1782,#1813,#1820));
#1822=MANIFOLD_SOLID_BREP('B2',#1821);
#1823=ADVANCED_BREP_SHAPE_REPRESENTATION('',(#18,#1822),#14);
#1824=SHAPE_DEFINITION_REPRESENTATION(#9,#1823);
ENDSEC;
END-ISO-10303-21;
